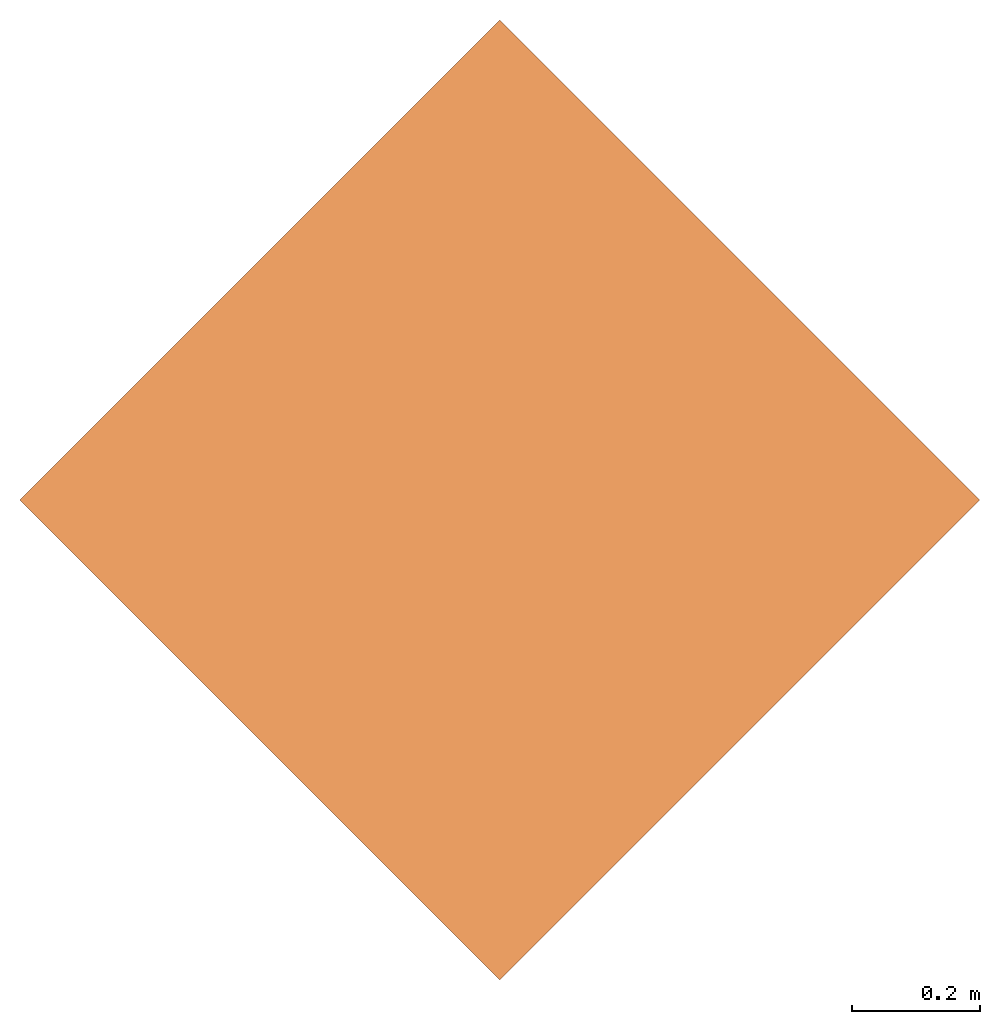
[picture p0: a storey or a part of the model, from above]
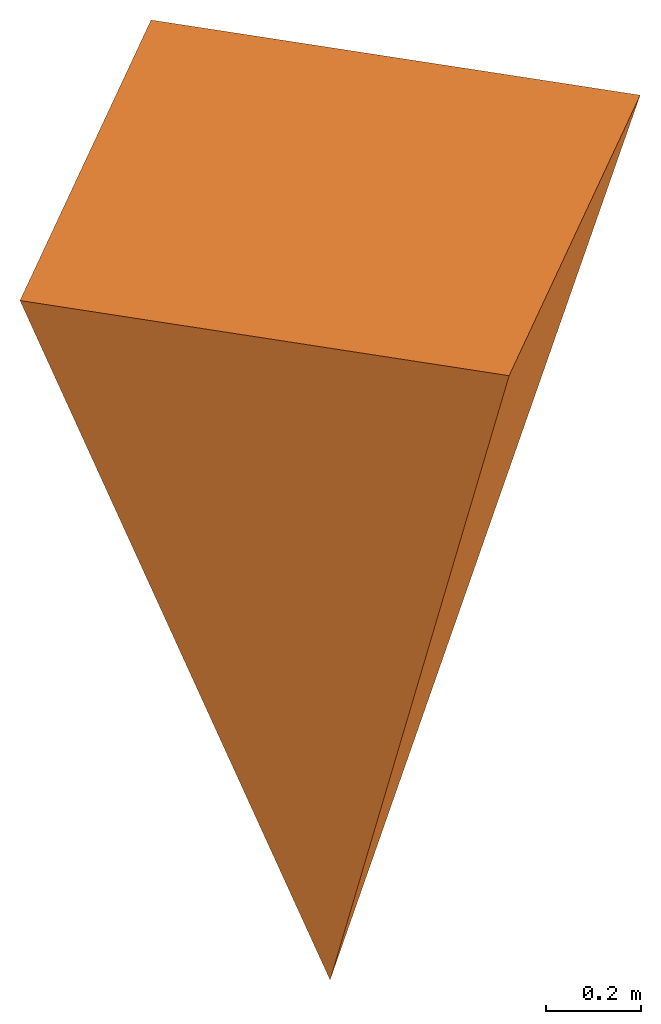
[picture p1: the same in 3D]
Properties of the parts of a building model (IFC4), part 1 of 4

# File
Description: no view
File name: 6-300-WUN-H1-000-000-FMO-V-00#260608.ifc
Time: 2026-06-08T13:36:47
Author: Tschörner Christoph, a|sh
Organization: No Organization
Written by: ODA SDAI 25.4
Authorization: christoph.tschoerner

# IfcProject, 40271-01 Psychiatrie Neubau Wunstorf LPH5
AllplanAttributes - Normalhöhennull: 43.1 m; Projektvorlage: ash_20210624

# IfcSite, Psychiatrie Neubau Wunstorf
RefLatitude: 48, 8, 10, 320000; RefLongitude: 11, 41, 19, 320000; RefElevation: 43.1 m

# IfcBuildingStorey (3)
In: Neubau H1 Sozialzentrum
Name | Elevation (m)
H1 Ebene +1 | 4.45
H1 Ebene 0 | 0.7
H1 Gründung | 0.2

# IfcSpace (38)
AllplanAttributes - Raumumschließung: R; Flächenart_DIN277: N; Flächenart_Wohnfläche: WO; Ortscode_Geschoßbezeichnung: Ebene 0; Raum unter Treppe (Wohnfl erst ab 2m): 0; Faktor_Wohnfläche_Raum: 1; Faktor_DIN277: 1; Bauteil: H2; Raumzone (nach DIN 18599): Ne; Raumprogramm Soll: 0 m2; Abrechnungsart: m²; Objektname: Raum
Name | In | LongName | Status | Nutzungsart_Din277 | ash_lichte Raumhöhe | OKFF | Allright_Bauteil_ID
WUN-H1-E01 | H1 Ebene +1 | Technik hoch | Neubau | TF | 6.455376 | 0 | 1616Rau0000076425 | AllplanAttributes - Raumnr. Bauherr: Technik
WUN-H1-E01 | H1 Ebene +1 | Hausanschluss |  | TF | 7.074000 | 0 | 1616Rau0000076258 | AllplanAttributes - Raumnr. Bauherr: Technik
WUN-H1-E01 | H1 Ebene +1 | AV | Neubau | TF | 7.074000 | 0 | 1616Rau0000076249 | AllplanAttributes - Raumnr. Bauherr: Technik
WUN-H1-E01 | H1 Ebene +1 | SV | Neubau | TF | 7.074000 | 0 | 1616Rau0000076252 | AllplanAttributes - Raumnr. Bauherr: Technik
WUN-H1-E01 | H1 Ebene +1 | EDV | Neubau | TF | 7.074000 | 0 | 1616Rau0000076301 | AllplanAttributes - Raumnr. Bauherr: Technik
WUN-H1-E01 | H1 Ebene +1 | Sicherheitsbeleuchtung | Neubau | TF | 7.074000 | 0 | 1616Rau0000076255 | AllplanAttributes - Raumnr. Bauherr: Technik
WUN-H1-E01 | H1 Ebene +1 | Flur | Neubau | TF | 7.074000 | 0 | 1616Rau0000076314
WUN-H1-E01 | H1 Ebene +1 | Luft | Neubau | TF | 7.224589 | 0 | 1616Rau0000076370 | AllplanAttributes - Raumnr. Bauherr: Technik
WUN-H1-E00 | H1 Ebene 0 | Flur | Neubau | TF | 3.450000 | 0.7 | 1565Rau0000038403
WUN-H1-E00 | H1 Ebene 0 | Flur | Neubau | TF | 4.100000 | 0.7 | 1565Rau0000038449
WUN-H1-E00 | H1 Ebene 0 | Mehrzweckraum | Neubau | TF | 5.221026 | 0.7 | 1566Rau0811551557
WUN-H1-E00 | H1 Ebene 0 | Speiseraum | Neubau | TF | 6.938287 | 0.7 | 1566Rau0811551560
WUN-H1-E00 | H1 Ebene 0 | Ausgabe | Neubau | TF | 5.361132 | 0.7 | 1566Rau0811551551
WUN-H1-E00 | H1 Ebene 0 | Windfang | Neubau | TF | 3.450000 | 0.7 | 1566Rau0811551566
WUN-H1-E00 | H1 Ebene 0 | WC BH | Neubau | TF | 3.477853 | 0.7 | 1566Rau0811551610
WUN-H1-E00 | H1 Ebene 0 | WC Pers. |  | NUF | (4100-36+764+100)/1000- | 0.7 | 1566Rau0811551584
WUN-H1-E00 | H1 Ebene 0 | WC H |  | TF | 3.200000 | 0.7 | 1566Rau0811551572
WUN-H1-E00 | H1 Ebene 0 | WC D |  | TF | 3.200000 | 0.7 | 1566Rau0811551575
WUN-H1-E00 | H1 Ebene 0 | WC BH |  | TF | 3.200000 | 0.7 | 1566Rau0811551599
WUN-H1-E00 | H1 Ebene 0 | Umkleideraum |  | NUF | (4100-36+514+100)/1000- | 0.7 | 1566Rau0811551545
WUN-H1-E00 | H1 Ebene 0 | PuMi. |  | TF | (4100-36+614+100)/1000- | 0.7 | 1566Rau0811551542
WUN-H1-E00 | H1 Ebene 0 | Büro | Neubau | NUF | 3.450000 | 0.7 | 1566Rau0811551524
WUN-H1-E00 | H1 Ebene 0 | Anlieferung | Neubau | NUF | 3.450000 | 0.7 | 1566Rau0811551563
WUN-H1-E00 | H1 Ebene 0 | Lager |  | NUF | (4100-36+514+100)/1000- | 0.7 | 1566Rau0811551536
WUN-H1-E00 | H1 Ebene 0 | Leergutlager | Neubau | NUF | (4100-36+514+100)/1000- | 0.7 | 1566Rau0811551530
WUN-H1-E00 | H1 Ebene 0 | Getränkelager | Neubau | NUF | (4100-36+514+100)/1000- | 0.7 | 1566Rau0811551596
WUN-H1-E00 | H1 Ebene 0 | Konfiskatkühler | Neubau | TF | 3.450000 | 0.7 | 1566Rau0811551539
WUN-H1-E00 | H1 Ebene 0 | Hausanschluss |  | TF | (4100-36+614+100)/1000- | 0.7 | 1566Rau0811551548 | AllplanAttributes - Raumnr. Bauherr: Technik
WUN-H1-E00 | H1 Ebene 0 | Abst. Stühle / Tische | Neubau | TF | 4.005791 | 0.7 | 1566Rau0811551607
WUN-H1-E00 | H1 Ebene 0 | Therapiegerät | Neubau | TF | 4.334275 | 0.7 | 1566Rau0811551601
WUN-H1-E00 | H1 Ebene 0 | Abst. Stühle / Tische |  | TF | (4100-36+764+100)/1000- | 0.7 | 1566Rau0811551554
WUN-H1-E00 | H1 Ebene 0 | Garderobe | Neubau | TF | 3.717910 | 0.7 | 1566Rau0811551604
WUN-H1-E00 | H1 Ebene 0 | Enzo | Neubau | TF | 3.500000 | 0.7 | 1566Rau0811551578
WUN-H1-E00 | H1 Ebene 0 | Küche | Neubau | TF | 3.500000 | 0.7 | 1566Rau0811551527
WUN-H1-E00 | H1 Ebene 0 | Mini Bakery | Neubau | TF | 3.500000 | 0.7 | 1566Rau0811551533
WUN-H1-E00 | H1 Ebene 0 | Spülraum |  | TF | 4.580000 | 0.7 | 1566Rau0811551581 | AllplanAttributes - Raumnr. Bauherr: Technik
WUN-H1-E00 | H1 Ebene 0 | NK | Neubau | NUF | (4100-36+514+100)/1000- | 0.7 | 1566Rau0811551593
WUN-H1-E00 | H1 Ebene 0 | TK | Neubau | NUF | (4100-36+514+100)/1000- | 0.7 | 1566Rau0811551590

# IfcBeam (2)
In: H1 Ebene 0
Material: Holz
AllplanAttributes - 2D Interaktion: yes; Gewerk: Zimmer- und Holzbauarbeiten; Material: Holz; OKFF: 0; Abrechnungsart: m³; Objektname: Unterzug
Pset_BeamCommon - Status: NEW; IsExternal: no; ThermalTransmittance: 0 W/K/m2
Name | Allright_Bauteil_ID
 | 1564Unz0000004217
 | 1564Unz0000004201

# IfcBuildingElementProxy, Nullpunkt
In: Modellreferenzen
AllplanAttributes - UK: 0 m; OK: 0 m; V6: 0 m; V7: 0 m; V8: 0 m; V9: 0; Bezeichnung: Nullpunkt; Allright_Bauteil_ID: 5981Mak0000010864; Abrechnungsart: St; Objektname: Makro

# IfcColumn (14)
PredefinedType: COLUMN
AllplanAttributes - Gewerk: Zimmer- und Holzbauarbeiten; Abrechnungsart: m; Objektname: Stütze
Name | In | Material = AllplanAttributes, Material | 2D Interaktion | Codetext = Reference | OKFF | Allright_Bauteil_ID | Status | LoadBearing = IsExternal | FireRating | ThermalTransmittance (W/K/m2)
 | H1 Ebene +1 | ST-H | yes | Codetext | 5.11 | 1613St 2005708406 | NEW | no | REI 60-A1 - D,s2-d0 /A1 | 0
 | H1 Ebene +1 | ST-H | yes | Codetext | 5.11 | 1613St 2005708246 | NEW | no | REI 60-A1 - D,s2-d0 /A1 | 0
 | H1 Ebene +1 | ST-H | yes | Codetext | 5.11 | 1613St 2005708252 | NEW | no | REI 60-A1 - D,s2-d0 /A1 | 0
 | H1 Ebene +1 | ST-H | yes | Codetext | 5.11 | 1613St 2005708254 | NEW | no | REI 60-A1 - D,s2-d0 /A1 | 0
 | H1 Ebene +1 | ST-Stahl | yes | Codetext | 5.11 | 1613St 2005708322 | NEW | no | REI 60-A1 - D,s2-d0 /A1 | 0
 | H1 Ebene +1 | ST-Stahl | yes | Codetext | 5.11 | 1613St 2005708312 | NEW | no | REI 60-A1 - D,s2-d0 /A1 | 0
 | H1 Ebene +1 | ST-Stahl | yes | Codetext | 5.11 | 1613St 2005708325 | NEW | no | REI 60-A1 - D,s2-d0 /A1 | 0
 | H1 Ebene +1 | ST-H | yes | Codetext | 5.11 | 1613St 2005708331 | NEW | no | REI 60-A1 - D,s2-d0 /A1 | 0
 | H1 Ebene +1 | ST-Stahl | yes | Codetext | 5.11 | 1613St 2005708383 | NEW | no | REI 60-A1 - D,s2-d0 /A1 | 0
 | H1 Ebene 0 | ST-H | yes | Codetext | 5.11 | 1563St 0813612477 | NEW | no | REI 60-A1 - D,s2-d0 /A1 | 0
 | H1 Ebene 0 | ST-ST |  |  |  | 1563St 0813612442
 | H1 Ebene 0 | ST-ST |  |  |  | 1563St 0813612436
 | H1 Ebene 0 | ST-ST |  |  |  | 1563St 0813612299
 | H1 Ebene 0 | ST-ST |  |  |  | 1563St 0813612460

# IfcCovering (135)
Name | In | PredefinedType | Material | Allright_Bauteil_ID | Abrechnungsart | Schichtnummer | Schichtdicke (m) | Dicke (m) = Bezugshöhe = Deltahöhe | Faktor | Objektname | AllplanAttributes, Material | Status | Gewerk | Bezeichnung | D_lichte Raumhöhe [Zahl] (m)
 | WUN-H1-E01 | FLOORING | FB 0.15 m | 1616Bfl0000076427/01 | m² | 1 | 0.15 | 0 | 1 | Bodenfläche | FB | NEW | AllplanAttributes - Bauteil-ID: 301
Gipsfaserplatten 2-lagig (BSK) | WUN-H1-E01 | CEILING | C/C 0.036 m | 1616Dfl0000076426/01 | m² | 1 | 0.036 | 0 | 1 | Deckenfläche | C/C | NEW | Trockenbauarbeiten | Gipsfaserplatten 2-lagig (BSK) | 3.364 | AllplanAttributes - RoomName: SV
Gipsfaserplatten 2-lagig (BSK) | WUN-H1-E01 | CEILING | D4 0.001 m | 1616Dfl0000076426/02 | m² | 2 | 0.001 | 0 | 1 | Deckenfläche | D4 | NEW | Maler- und Lackierarbeiten
PVC | WUN-H1-E01 | FLOORING | Ku3 0.15 m | 1616Bfl0000076357/01 | m² | 1 | 0.15 | 0 | 1 | Bodenfläche | Ku3 | NEW | Bodenbelagsarbeiten | PVC | AllplanAttributes - Bauteil-ID: 301; Raumnr. Bauherr: 2.11_A2_02; ash B_Aufbau: B1; ash B_Rutschhemmung: R9
Gipsfaserplatten 2-lagig (BSK) | WUN-H1-E01 | CEILING | C/C 0.036 m | 1616Dfl0000076418/01 | m² | 1 | 0.036 | 0 | 1 | Deckenfläche | C/C | NEW | Trockenbauarbeiten | Gipsfaserplatten 2-lagig (BSK) | 3.364 | AllplanAttributes - RoomName: SV
Gipsfaserplatten 2-lagig (BSK) | WUN-H1-E01 | CEILING | D4 0.001 m | 1616Dfl0000076418/02 | m² | 2 | 0.001 | 0 | 1 | Deckenfläche | D4 | NEW | Maler- und Lackierarbeiten
PVC | WUN-H1-E01 | FLOORING | Ku3 0.15 m | 1616Bfl0000076354/01 | m² | 1 | 0.15 | 0 | 1 | Bodenfläche | Ku3 | NEW | Bodenbelagsarbeiten | PVC | AllplanAttributes - Bauteil-ID: 301; Raumnr. Bauherr: 2.11_A2_02; ash B_Aufbau: B1; ash B_Rutschhemmung: R9
Gipsfaserplatten 2-lagig (BSK) | WUN-H1-E01 | CEILING | C/C 0.036 m | 1616Dfl0000076419/01 | m² | 1 | 0.036 | 0 | 1 | Deckenfläche | C/C | NEW | Trockenbauarbeiten | Gipsfaserplatten 2-lagig (BSK) | 3.364 | AllplanAttributes - RoomName: SV
Gipsfaserplatten 2-lagig (BSK) | WUN-H1-E01 | CEILING | D4 0.001 m | 1616Dfl0000076419/02 | m² | 2 | 0.001 | 0 | 1 | Deckenfläche | D4 | NEW | Maler- und Lackierarbeiten
PVC | WUN-H1-E01 | FLOORING | Ku3 0.15 m | 1616Bfl0000076355/01 | m² | 1 | 0.15 | 0 | 1 | Bodenfläche | Ku3 | NEW | Bodenbelagsarbeiten | PVC | AllplanAttributes - Bauteil-ID: 301; Raumnr. Bauherr: 2.11_A2_02; ash B_Aufbau: B1; ash B_Rutschhemmung: R9
Gipsfaserplatten 2-lagig (BSK) | WUN-H1-E01 | CEILING | C/C 0.036 m | 1616Dfl0000076420/01 | m² | 1 | 0.036 | 0 | 1 | Deckenfläche | C/C | NEW | Trockenbauarbeiten | Gipsfaserplatten 2-lagig (BSK) | 3.364 | AllplanAttributes - RoomName: SV
Gipsfaserplatten 2-lagig (BSK) | WUN-H1-E01 | CEILING | D4 0.001 m | 1616Dfl0000076420/02 | m² | 2 | 0.001 | 0 | 1 | Deckenfläche | D4 | NEW | Maler- und Lackierarbeiten
PVC | WUN-H1-E01 | FLOORING | Ku3 0.15 m | 1616Bfl0000076358/01 | m² | 1 | 0.15 | 0 | 1 | Bodenfläche | Ku3 | NEW | Bodenbelagsarbeiten | PVC | AllplanAttributes - Bauteil-ID: 301; Raumnr. Bauherr: 2.11_A2_02; ash B_Aufbau: B1; ash B_Rutschhemmung: R9
Gipsfaserplatten 2-lagig (BSK) | WUN-H1-E01 | CEILING | C/C 0.036 m | 1616Dfl0000076421/01 | m² | 1 | 0.036 | 0 | 1 | Deckenfläche | C/C | NEW | Trockenbauarbeiten | Gipsfaserplatten 2-lagig (BSK) | 3.364 | AllplanAttributes - RoomName: SV
Gipsfaserplatten 2-lagig (BSK) | WUN-H1-E01 | CEILING | D4 0.001 m | 1616Dfl0000076421/02 | m² | 2 | 0.001 | 0 | 1 | Deckenfläche | D4 | NEW | Maler- und Lackierarbeiten
PVC | WUN-H1-E01 | FLOORING | Ku3 0.15 m | 1616Bfl0000076356/01 | m² | 1 | 0.15 | 0 | 1 | Bodenfläche | Ku3 | NEW | Bodenbelagsarbeiten | PVC | AllplanAttributes - Bauteil-ID: 301; Raumnr. Bauherr: 2.11_A2_02; ash B_Aufbau: B1; ash B_Rutschhemmung: R9
Gipsfaserplatten 2-lagig (BSK) | WUN-H1-E01 | CEILING | C/C 0.036 m | 1616Dfl0000076422/01 | m² | 1 | 0.036 | 0 | 1 | Deckenfläche | C/C | NEW | Trockenbauarbeiten | Gipsfaserplatten 2-lagig (BSK) | 3.364 | AllplanAttributes - RoomName: SV
Gipsfaserplatten 2-lagig (BSK) | WUN-H1-E01 | CEILING | D4 0.001 m | 1616Dfl0000076422/02 | m² | 2 | 0.001 | 0 | 1 | Deckenfläche | D4 | NEW | Maler- und Lackierarbeiten
PVC | WUN-H1-E01 | FLOORING | Ku3 0.15 m | 1616Bfl0000076359/01 | m² | 1 | 0.15 | 0 | 1 | Bodenfläche | Ku3 | NEW | Bodenbelagsarbeiten | PVC | AllplanAttributes - Bauteil-ID: 301; Raumnr. Bauherr: 2.11_A2_02; ash B_Aufbau: B1; ash B_Rutschhemmung: R9
Gipsfaserplatten 2-lagig (BSK) | WUN-H1-E01 | CEILING | C/C 0.036 m | 1616Dfl0000076424/01 | m² | 1 | 0.036 | 0 | 1 | Deckenfläche | C/C | NEW | Trockenbauarbeiten | Gipsfaserplatten 2-lagig (BSK) | 3.364 | AllplanAttributes - RoomName: SV
Gipsfaserplatten 2-lagig (BSK) | WUN-H1-E01 | CEILING | D4 0.001 m | 1616Dfl0000076424/02 | m² | 2 | 0.001 | 0 | 1 | Deckenfläche | D4 | NEW | Maler- und Lackierarbeiten
PVC | WUN-H1-E01 | FLOORING | Ku3 0.15 m | 1616Bfl0000076371/01 | m² | 1 | 0.15 | 0 | 1 | Bodenfläche | Ku3 | NEW | Bodenbelagsarbeiten | PVC | AllplanAttributes - Bauteil-ID: 301; Raumnr. Bauherr: 2.11_A2_02; ash B_Aufbau: B1; ash B_Rutschhemmung: R9
Gipsfaserplatten 2-lagig (BSK) | WUN-H1-E01 | CEILING | C/C 0.036 m | 1616Dfl0000076423/01 | m² | 1 | 0.036 | 0 | 1 | Deckenfläche | C/C | NEW | Trockenbauarbeiten | Gipsfaserplatten 2-lagig (BSK) | 3.364 | AllplanAttributes - RoomName: SV
Gipsfaserplatten 2-lagig (BSK) | WUN-H1-E01 | CEILING | D4 0.001 m | 1616Dfl0000076423/02 | m² | 2 | 0.001 | 0 | 1 | Deckenfläche | D4 | NEW | Maler- und Lackierarbeiten
Gipsfaserplatten 2-lagig (BSK) | H1 Ebene 0 | CEILING | layer 0.036 m | 1565Dfl0000038394/01 | m² | 1 | 0.036 | 0 | 1 | Deckenfläche |  | NEW | Trockenbauarbeiten | Gipsfaserplatten 2-lagig (BSK) | 2.5
Gipsfaserplatten 2-lagig (BSK) | H1 Ebene 0 | CEILING | Installationshöhe 0.994 m | 1565Dfl0000038394/02 | m² | 2 | 0.994 | 0 | 1 | Bekleidung | Installationshöhe | NEW | Trockenbauarbeiten |  | 2.5 | AllplanAttributes - ash_lichte Raumhöhe: 2.750000; OKFF: 0; Pset_CoveringCommon - FireRating: für korrekte FläVisu
Gipsfaserplatten 2-lagig (BSK) | H1 Ebene 0 | CEILING | A1 0.1 m | 1565Dfl0000038394/03 | m² | 3 | 0.1 | 0 | 1 | Bekleidung | A1 | NEW | Trockenbauarbeiten |  | 2.5 | AllplanAttributes - ash_lichte Raumhöhe: 2.750000; OKFF: 0; Pset_CoveringCommon - FireRating: -; AcousticRating: -
Gipsfaserplatten 2-lagig (BSK) | H1 Ebene 0 | CEILING | D1 0.001 m | 1565Dfl0000038394/04 | m² | 4 | 0.001 | 0 | 1 | Bekleidung | D1 | NEW | Maler- und Lackierarbeiten |  | 2.5 | AllplanAttributes - ash_lichte Raumhöhe: 2.750000; OKFF: 0
Fliesen Großformat | WUN-H1-E00 | FLOORING | Fl12 0.2 m | 1565Bfl0000038399/01 | m² | 1 | 0.2 | 0 | 1 | Bodenfläche | Fl12 | NEW | Bodenbelagsarbeiten | Fliesen Großformat | AllplanAttributes - Bauteil-ID: 301; Raumnr. Bauherr: 2.11_A2_02; ash B_Aufbau: B4; ash B_Rutschhemmung: R10
Gipsfaserplatten 2-lagig (BSK) | WUN-H1-E00 | CEILING | layer 0.036 m | 1565Dfl0000038401/01 | m² | 1 | 0.036 | 0 | 1 | Deckenfläche |  | NEW | Trockenbauarbeiten | Gipsfaserplatten 2-lagig (BSK) | 2.5
 | WUN-H1-E00 | CEILING | Installationshöhe 0.514 m | 1565Dfl0000038401/02 | m² | 2 | 0.514 | 0 | 1 | Bekleidung | Installationshöhe | NEW | Trockenbauarbeiten |  | 2.5 | AllplanAttributes - ash_lichte Raumhöhe: 2.750000; Pset_CoveringCommon - FireRating: für korrekte FläVisu
 | WUN-H1-E00 | CEILING | A1 0.1 m | 1565Dfl0000038401/03 | m² | 3 | 0.1 | 0 | 1 | Bekleidung | A1 | NEW | Trockenbauarbeiten |  | 2.5 | AllplanAttributes - ash_lichte Raumhöhe: 2.750000; Pset_CoveringCommon - AcousticRating: -
 | WUN-H1-E00 | CEILING | D1 0.001 m | 1565Dfl0000038401/04 | m² | 4 | 0.001 | 0 | 1 | Bekleidung | D1 | NEW | Maler- und Lackierarbeiten |  | 2.5 | AllplanAttributes - ash_lichte Raumhöhe: 2.750000
Gipsfaserplatten 2-lagig (BSK) | WUN-H1-E00 | CEILING | layer 0.036 m | 1565Dfl0000038357/01 | m² | 1 | 0.036 | 0 | 1 | Deckenfläche |  | NEW | Trockenbauarbeiten | Gipsfaserplatten 2-lagig (BSK) | 2.5
Gipsfaserplatten 2-lagig (BSK) | WUN-H1-E00 | CEILING | Installationshöhe 0.514 m | 1565Dfl0000038357/02 | m² | 2 | 0.514 | 0 | 1 | Bekleidung | Installationshöhe | NEW | Trockenbauarbeiten |  | 2.5 | AllplanAttributes - ash_lichte Raumhöhe: 2.750000; OKFF: 0; Pset_CoveringCommon - FireRating: für korrekte FläVisu
Gipsfaserplatten 2-lagig (BSK) | WUN-H1-E00 | CEILING | A1 0.1 m | 1565Dfl0000038357/03 | m² | 3 | 0.1 | 0 | 1 | Bekleidung | A1 | NEW | Trockenbauarbeiten |  | 2.5 | AllplanAttributes - ash_lichte Raumhöhe: 2.750000; OKFF: 0; Pset_CoveringCommon - FireRating: -; AcousticRating: -
Gipsfaserplatten 2-lagig (BSK) | WUN-H1-E00 | CEILING | D1 0.001 m | 1565Dfl0000038357/04 | m² | 4 | 0.001 | 0 | 1 | Bekleidung | D1 | NEW | Maler- und Lackierarbeiten |  | 2.5 | AllplanAttributes - ash_lichte Raumhöhe: 2.750000; OKFF: 0
PVC Bahnenware Uni | WUN-H1-E00 | FLOORING | Ku2 0.2 m | 1565Bfl0000038447/01 | m² | 1 | 0.2 | 0 | 1 | Bodenfläche | Ku2 | NEW | Bodenbelagsarbeiten | PVC Bahnenware Uni | AllplanAttributes - Bauteil-ID: 301; Raumnr. Bauherr: 2.11_A2_02; ash B_Aufbau: B1; ash B_Rutschhemmung: R9
Fliesen Großformat | WUN-H1-E00 | FLOORING | Fl12 0.2 m | 1566Bfl0811551861/01 | m² | 1 | 0.2 | 0 | 1 | Bodenfläche | Fl12 | NEW | Bodenbelagsarbeiten | Fliesen Großformat | AllplanAttributes - Bauteil-ID: 301; Raumnr. Bauherr: 2.11_A2_02; ash B_Aufbau: B4; ash B_Rutschhemmung: R10
Fliesen Großformat | WUN-H1-E00 | FLOORING | Fl12 0.2 m | 1566Bfl0811551866/01 | m² | 1 | 0.2 | 0 | 1 | Bodenfläche | Fl12 | NEW | Bodenbelagsarbeiten | Fliesen Großformat | AllplanAttributes - Bauteil-ID: 301; Raumnr. Bauherr: 2.11_A2_02; ash B_Aufbau: B4; ash B_Rutschhemmung: R10
Fliesen Großformat | WUN-H1-E00 | FLOORING | Fl12 0.2 m | 1566Bfl0811551889/01 | m² | 1 | 0.2 | 0 | 1 | Bodenfläche | Fl12 | NEW | Bodenbelagsarbeiten | Fliesen Großformat | AllplanAttributes - Bauteil-ID: 301; Raumnr. Bauherr: 2.11_A2_02; ash B_Aufbau: B4; ash B_Rutschhemmung: R10
Fliesen Großformat | WUN-H1-E00 | FLOORING | Fl12 0.2 m | 1566Bfl0811551860/01 | m² | 1 | 0.2 | 0 | 1 | Bodenfläche | Fl12 | NEW | Bodenbelagsarbeiten | Fliesen Großformat | AllplanAttributes - Bauteil-ID: 301; Raumnr. Bauherr: 2.11_A2_02; ash B_Aufbau: B4; ash B_Rutschhemmung: R10
Fliesen | WUN-H1-E00 | FLOORING | Fl1 0.2 m | 1566Bfl0811551862/01 | m² | 1 | 0.2 | 0 | 1 | Bodenfläche | Fl1 | NEW | Bodenbelagsarbeiten | Fliesen | AllplanAttributes - Bauteil-ID: 301; Raumnr. Bauherr: 2.11_A2_02; ash B_Aufbau: B2; ash B_Rutschhemmung: R10
Fliesen | WUN-H1-E00 | FLOORING | Fl1 0.2 m | 1566Bfl0811551872/01 | m² | 1 | 0.2 | 0 | 1 | Bodenfläche | Fl1 | NEW | Bodenbelagsarbeiten | Fliesen | AllplanAttributes - Bauteil-ID: 301; Raumnr. Bauherr: 2.11_A2_02; ash B_Aufbau: B2; ash B_Rutschhemmung: R10
Gipsfaserplatten 2-lagig (BSK) | WUN-H1-E00 | CEILING | layer 0.036 m | 1566Dfl0811551925/01 | m² | 1 | 0.036 | 0 | 1 | Bekleidung |  | NEW | Trockenbauarbeiten | Gipsfaserplatten 2-lagig (BSK) | 2.5 | AllplanAttributes - ash_lichte Raumhöhe: 2.5; Attributset-Objekt: Covering; Pset_CoveringCommon - FireRating: für korrekte FläVisu
Gipsfaserplatten 2-lagig (BSK) | WUN-H1-E00 | CEILING | Installationshöhe 0.764 m | 1566Dfl0811551925/02 | m² | 2 | 0.764 | 0 | 1 | Bekleidung | Installationshöhe | NEW | Trockenbauarbeiten |  | 2.5 | AllplanAttributes - ash_lichte Raumhöhe: (4100-36+764+100)/1000-0.7; Attributset-Objekt: Covering; Pset_CoveringCommon - FireRating: für korrekte FläVisu; Reference: Reference
Rasterdecke | WUN-H1-E00 | CEILING | E3 0.1 m | 1566Dfl0811551925/03 | m² | 3 | 0.1 | 0 | 1 | Bekleidung | E3 | NEW | Trockenbauarbeiten | Rasterdecke | 2.5 | AllplanAttributes - ash_lichte Raumhöhe: (4100-36+764+100)/1000-0.7; Attributset-Objekt: Covering; Pset_CoveringCommon - FireRating: -; AcousticRating: -
Fliesen | WUN-H1-E00 | FLOORING | Fl1 0.2 m | 1566Bfl0811551874/01 | m² | 1 | 0.2 | 0 | 1 | Bodenfläche | Fl1 |  | Bodenbelagsarbeiten | Fliesen | AllplanAttributes - Bauteil-ID: 301; Raumnr. Bauherr: 2.11_A2_02; ash B_Aufbau: B2; ash B_Rutschhemmung: R10
Gipsfaserplatten 2-lagig (BSK) | WUN-H1-E00 | CEILING | layer 0.036 m | 1566Dfl0811551927/01 | m² | 1 | 0.036 | 0 | 1 | Deckenfläche |  |  | Trockenbauarbeiten | Gipsfaserplatten 2-lagig (BSK) | 2.5
Gipsfaserplatten 2-lagig (BSK) | WUN-H1-E00 | CEILING | Installationshöhe 0.764 m | 1566Dfl0811551927/02 | m² | 2 | 0.764 | 0 | 1 | Bekleidung | Installationshöhe |  | Trockenbauarbeiten |  | 2.5 | AllplanAttributes - ash_lichte Raumhöhe: 2.500000; OKFF: 0; Pset_CoveringCommon - FireRating: für korrekte FläVisu
Gipskarton, imprägniert | WUN-H1-E00 | CEILING | B 0.1 m | 1566Dfl0811551927/03 | m² | 3 | 0.1 | 0 | 1 | Bekleidung | B |  | Trockenbauarbeiten | Gipskarton, imprägniert | 2.5 | AllplanAttributes - ash_lichte Raumhöhe: 2.500000; OKFF: 0; Pset_CoveringCommon - FireRating: -; AcousticRating: -
Gipsfaserplatten 2-lagig (BSK) | WUN-H1-E00 | CEILING | D1 0.001 m | 1566Dfl0811551927/04 | m² | 4 | 0.001 | 0 | 1 | Bekleidung | D1 |  | Maler- und Lackierarbeiten |  | 2.5 | AllplanAttributes - ash_lichte Raumhöhe: 2.500000; OKFF: 0
Fliesen | WUN-H1-E00 | FLOORING | Fl1 0.2 m | 1566Bfl0811551873/01 | m² | 1 | 0.2 | 0 | 1 | Bodenfläche | Fl1 |  | Bodenbelagsarbeiten | Fliesen | AllplanAttributes - Bauteil-ID: 301; Raumnr. Bauherr: 2.11_A2_02; ash B_Aufbau: B2; ash B_Rutschhemmung: R10
Gipsfaserplatten 2-lagig (BSK) | WUN-H1-E00 | CEILING | layer 0.036 m | 1566Dfl0811551926/01 | m² | 1 | 0.036 | 0 | 1 | Deckenfläche |  |  | Trockenbauarbeiten | Gipsfaserplatten 2-lagig (BSK) | 2.5
Gipsfaserplatten 2-lagig (BSK) | WUN-H1-E00 | CEILING | Installationshöhe 0.764 m | 1566Dfl0811551926/02 | m² | 2 | 0.764 | 0 | 1 | Bekleidung | Installationshöhe |  | Trockenbauarbeiten |  | 2.5 | AllplanAttributes - ash_lichte Raumhöhe: 2.500000; OKFF: 0; Pset_CoveringCommon - FireRating: für korrekte FläVisu
Gipskarton, imprägniert | WUN-H1-E00 | CEILING | B 0.1 m | 1566Dfl0811551926/03 | m² | 3 | 0.1 | 0 | 1 | Bekleidung | B |  | Trockenbauarbeiten | Gipskarton, imprägniert | 2.5 | AllplanAttributes - ash_lichte Raumhöhe: 2.500000; OKFF: 0; Pset_CoveringCommon - FireRating: -; AcousticRating: -
Gipsfaserplatten 2-lagig (BSK) | WUN-H1-E00 | CEILING | D1 0.001 m | 1566Dfl0811551926/04 | m² | 4 | 0.001 | 0 | 1 | Bekleidung | D1 |  | Maler- und Lackierarbeiten |  | 2.5 | AllplanAttributes - ash_lichte Raumhöhe: 2.500000; OKFF: 0
Fliesen | WUN-H1-E00 | FLOORING | Fl1 0.2 m | 1566Bfl0811551867/01 | m² | 1 | 0.2 | 0 | 1 | Bodenfläche | Fl1 |  | Bodenbelagsarbeiten | Fliesen | AllplanAttributes - Bauteil-ID: 301; Raumnr. Bauherr: 2.11_A2_02; ash B_Aufbau: B2; ash B_Rutschhemmung: R10
Gipsfaserplatten 2-lagig (BSK) | WUN-H1-E00 | CEILING | layer 0.036 m | 1566Dfl0811551920/01 | m² | 1 | 0.036 | 0 | 1 | Deckenfläche |  |  | Trockenbauarbeiten | Gipsfaserplatten 2-lagig (BSK) | 2.5
Gipsfaserplatten 2-lagig (BSK) | WUN-H1-E00 | CEILING | Installationshöhe 0.764 m | 1566Dfl0811551920/02 | m² | 2 | 0.764 | 0 | 1 | Bekleidung | Installationshöhe |  | Trockenbauarbeiten |  | 2.5 | AllplanAttributes - ash_lichte Raumhöhe: 2.500000; OKFF: 0; Pset_CoveringCommon - FireRating: für korrekte FläVisu
Gipskarton, imprägniert | WUN-H1-E00 | CEILING | B 0.1 m | 1566Dfl0811551920/03 | m² | 3 | 0.1 | 0 | 1 | Bekleidung | B |  | Trockenbauarbeiten | Gipskarton, imprägniert | 2.5 | AllplanAttributes - ash_lichte Raumhöhe: 2.500000; OKFF: 0; Pset_CoveringCommon - FireRating: -; AcousticRating: -
Gipsfaserplatten 2-lagig (BSK) | WUN-H1-E00 | CEILING | D1 0.001 m | 1566Dfl0811551920/04 | m² | 4 | 0.001 | 0 | 1 | Bekleidung | D1 |  | Maler- und Lackierarbeiten |  | 2.5 | AllplanAttributes - ash_lichte Raumhöhe: 2.500000; OKFF: 0
PVC Bahnenware Uni | WUN-H1-E00 | FLOORING | Ku2 0.2 m | 1566Bfl0811551879/01 | m² | 1 | 0.2 | 0 | 1 | Bodenfläche | Ku2 | NEW | Bodenbelagsarbeiten | PVC Bahnenware Uni | AllplanAttributes - Bauteil-ID: 301; Raumnr. Bauherr: 2.11_A2_02; ash B_Aufbau: B1; ash B_Rutschhemmung: R9
Gipsfaserplatten 2-lagig (BSK) | WUN-H1-E00 | CEILING | layer 0.036 m | 1566Dfl0811551931/01 | m² | 1 | 0.036 | 0 | 1 | Bekleidung |  | NEW | Trockenbauarbeiten | Gipsfaserplatten 2-lagig (BSK) | 2.5 | AllplanAttributes - ash_lichte Raumhöhe: 2.75; Attributset-Objekt: Covering; Pset_CoveringCommon - FireRating: für korrekte FläVisu
Gipsfaserplatten 2-lagig (BSK) | WUN-H1-E00 | CEILING | Installationshöhe 0.514 m | 1566Dfl0811551931/02 | m² | 2 | 0.514 | 0 | 1 | Bekleidung | Installationshöhe | NEW | Trockenbauarbeiten |  | 2.5 | AllplanAttributes - ash_lichte Raumhöhe: (4100-36+514+100)/1000-0.7; Attributset-Objekt: Covering; Pset_CoveringCommon - FireRating: für korrekte FläVisu; Reference: Reference
Rasterdecke | WUN-H1-E00 | CEILING | E3 0.1 m | 1566Dfl0811551931/03 | m² | 3 | 0.1 | 0 | 1 | Bekleidung | E3 | NEW | Trockenbauarbeiten | Rasterdecke | 2.5 | AllplanAttributes - ash_lichte Raumhöhe: (4100-36+514+100)/1000-0.7; Attributset-Objekt: Covering; Pset_CoveringCommon - FireRating: -; AcousticRating: -
PVC Bahnenware Uni | WUN-H1-E00 | FLOORING | Ku2 0.2 m | 1566Bfl0811551880/01 | m² | 1 | 0.2 | 0 | 1 | Bodenfläche | Ku2 | NEW | Bodenbelagsarbeiten | PVC Bahnenware Uni | AllplanAttributes - Bauteil-ID: 301; Raumnr. Bauherr: 2.11_A2_02; ash B_Aufbau: B1; ash B_Rutschhemmung: R9
Gipsfaserplatten 2-lagig (BSK) | WUN-H1-E00 | CEILING | layer 0.036 m | 1566Dfl0811551932/01 | m² | 1 | 0.036 | 0 | 1 | Bekleidung |  | NEW | Trockenbauarbeiten | Gipsfaserplatten 2-lagig (BSK) | 2.5 | AllplanAttributes - ash_lichte Raumhöhe: 2.65; Attributset-Objekt: Covering; Pset_CoveringCommon - FireRating: für korrekte FläVisu
Gipsfaserplatten 2-lagig (BSK) | WUN-H1-E00 | CEILING | Installationshöhe 0.614 m | 1566Dfl0811551932/02 | m² | 2 | 0.614 | 0 | 1 | Bekleidung | Installationshöhe | NEW | Trockenbauarbeiten |  | 2.5 | AllplanAttributes - ash_lichte Raumhöhe: (4100-36+614+100)/1000-0.7; Attributset-Objekt: Covering; Pset_CoveringCommon - FireRating: für korrekte FläVisu; Reference: Reference
Rasterdecke | WUN-H1-E00 | CEILING | E3 0.1 m | 1566Dfl0811551932/03 | m² | 3 | 0.1 | 0 | 1 | Bekleidung | E3 | NEW | Trockenbauarbeiten | Rasterdecke | 2.5 | AllplanAttributes - ash_lichte Raumhöhe: (4100-36+614+100)/1000-0.7; Attributset-Objekt: Covering; Pset_CoveringCommon - FireRating: -; AcousticRating: -
PVC Bahnenware Uni | WUN-H1-E00 | FLOORING | Ku2 0.2 m | 1566Bfl0811551884/01 | m² | 1 | 0.2 | 0 | 1 | Bodenfläche | Ku2 | NEW | Bodenbelagsarbeiten | PVC Bahnenware Uni | AllplanAttributes - Bauteil-ID: 301; Raumnr. Bauherr: 2.11_A2_02; ash B_Aufbau: B1; ash B_Rutschhemmung: R9
Gipsfaserplatten 2-lagig (BSK) | WUN-H1-E00 | CEILING | layer 0.036 m | 1566Dfl0811551936/01 | m² | 1 | 0.036 | 0 | 1 | Deckenfläche |  | NEW | Trockenbauarbeiten | Gipsfaserplatten 2-lagig (BSK) | 2.5
Gipsfaserplatten 2-lagig (BSK) | WUN-H1-E00 | CEILING | Installationshöhe 0.514 m | 1566Dfl0811551936/02 | m² | 2 | 0.514 | 0 | 1 | Bekleidung | Installationshöhe | NEW | Trockenbauarbeiten |  | 2.5 | AllplanAttributes - ash_lichte Raumhöhe: 2.750000; OKFF: 0; Pset_CoveringCommon - FireRating: für korrekte FläVisu
Gipsfaserplatten 2-lagig (BSK) | WUN-H1-E00 | CEILING | A1 0.1 m | 1566Dfl0811551936/03 | m² | 3 | 0.1 | 0 | 1 | Bekleidung | A1 | NEW | Trockenbauarbeiten |  | 2.5 | AllplanAttributes - ash_lichte Raumhöhe: 2.750000; OKFF: 0; Pset_CoveringCommon - FireRating: -; AcousticRating: -
Gipsfaserplatten 2-lagig (BSK) | WUN-H1-E00 | CEILING | D1 0.001 m | 1566Dfl0811551936/04 | m² | 4 | 0.001 | 0 | 1 | Bekleidung | D1 | NEW | Maler- und Lackierarbeiten |  | 2.5 | AllplanAttributes - ash_lichte Raumhöhe: 2.750000; OKFF: 0
PVC Bahnenware Uni | WUN-H1-E00 | FLOORING | Ku2 0.2 m | 1566Bfl0811551876/01 | m² | 1 | 0.2 | 0 | 1 | Bodenfläche | Ku2 | NEW | Bodenbelagsarbeiten | PVC Bahnenware Uni | AllplanAttributes - Bauteil-ID: 301; Raumnr. Bauherr: 2.11_A2_02; ash B_Aufbau: B1; ash B_Rutschhemmung: R9
Gipsfaserplatten 2-lagig (BSK) | WUN-H1-E00 | CEILING | layer 0.036 m | 1566Dfl0811551928/01 | m² | 1 | 0.036 | 0 | 1 | Deckenfläche |  | NEW | Trockenbauarbeiten | Gipsfaserplatten 2-lagig (BSK) | 2.5
Gipsfaserplatten 2-lagig (BSK) | WUN-H1-E00 | CEILING | Installationshöhe 0.514 m | 1566Dfl0811551928/02 | m² | 2 | 0.514 | 0 | 1 | Bekleidung | Installationshöhe | NEW | Trockenbauarbeiten |  | 2.5 | AllplanAttributes - ash_lichte Raumhöhe: 2.750000; OKFF: 0; Pset_CoveringCommon - FireRating: für korrekte FläVisu
Gipsfaserplatten 2-lagig (BSK) | WUN-H1-E00 | CEILING | A1 0.1 m | 1566Dfl0811551928/03 | m² | 3 | 0.1 | 0 | 1 | Bekleidung | A1 | NEW | Trockenbauarbeiten |  | 2.5 | AllplanAttributes - ash_lichte Raumhöhe: 2.750000; OKFF: 0; Pset_CoveringCommon - FireRating: -; AcousticRating: -
Gipsfaserplatten 2-lagig (BSK) | WUN-H1-E00 | CEILING | D1 0.001 m | 1566Dfl0811551928/04 | m² | 4 | 0.001 | 0 | 1 | Bekleidung | D1 | NEW | Maler- und Lackierarbeiten |  | 2.5 | AllplanAttributes - ash_lichte Raumhöhe: 2.750000; OKFF: 0
PVC Bahnenware Uni | WUN-H1-E00 | FLOORING | Ku2 0.2 m | 1566Bfl0811551882/01 | m² | 1 | 0.2 | 0 | 1 | Bodenfläche | Ku2 | NEW | Bodenbelagsarbeiten | PVC Bahnenware Uni | AllplanAttributes - Bauteil-ID: 301; Raumnr. Bauherr: 2.11_A2_02; ash B_Aufbau: B1; ash B_Rutschhemmung: R9
Gipsfaserplatten 2-lagig (BSK) | WUN-H1-E00 | CEILING | layer 0.036 m | 1566Dfl0811551934/01 | m² | 1 | 0.036 | 0 | 1 | Bekleidung |  | NEW | Trockenbauarbeiten | Gipsfaserplatten 2-lagig (BSK) | 2.5 | AllplanAttributes - ash_lichte Raumhöhe: 2.75; Attributset-Objekt: Covering; Pset_CoveringCommon - FireRating: für korrekte FläVisu
Gipsfaserplatten 2-lagig (BSK) | WUN-H1-E00 | CEILING | Installationshöhe 0.514 m | 1566Dfl0811551934/02 | m² | 2 | 0.514 | 0 | 1 | Bekleidung | Installationshöhe | NEW | Trockenbauarbeiten |  | 2.5 | AllplanAttributes - ash_lichte Raumhöhe: (4100-36+514+100)/1000-0.7; Attributset-Objekt: Covering; Pset_CoveringCommon - FireRating: für korrekte FläVisu; Reference: Reference
Rasterdecke | WUN-H1-E00 | CEILING | E3 0.1 m | 1566Dfl0811551934/03 | m² | 3 | 0.1 | 0 | 1 | Bekleidung | E3 | NEW | Trockenbauarbeiten | Rasterdecke | 2.5 | AllplanAttributes - ash_lichte Raumhöhe: (4100-36+514+100)/1000-0.7; Attributset-Objekt: Covering; Pset_CoveringCommon - FireRating: -; AcousticRating: -
PVC Bahnenware Uni | WUN-H1-E00 | FLOORING | Ku2 0.2 m | 1566Bfl0811551883/01 | m² | 1 | 0.2 | 0 | 1 | Bodenfläche | Ku2 | NEW | Bodenbelagsarbeiten | PVC Bahnenware Uni | AllplanAttributes - Bauteil-ID: 301; Raumnr. Bauherr: 2.11_A2_02; ash B_Aufbau: B1; ash B_Rutschhemmung: R9
Gipsfaserplatten 2-lagig (BSK) | WUN-H1-E00 | CEILING | layer 0.036 m | 1566Dfl0811551935/01 | m² | 1 | 0.036 | 0 | 1 | Bekleidung |  | NEW | Trockenbauarbeiten | Gipsfaserplatten 2-lagig (BSK) | 2.5 | AllplanAttributes - ash_lichte Raumhöhe: 2.75; Attributset-Objekt: Covering; Pset_CoveringCommon - FireRating: für korrekte FläVisu
Gipsfaserplatten 2-lagig (BSK) | WUN-H1-E00 | CEILING | Installationshöhe 0.514 m | 1566Dfl0811551935/02 | m² | 2 | 0.514 | 0 | 1 | Bekleidung | Installationshöhe | NEW | Trockenbauarbeiten |  | 2.5 | AllplanAttributes - ash_lichte Raumhöhe: (4100-36+514+100)/1000-0.7; Attributset-Objekt: Covering; Pset_CoveringCommon - FireRating: für korrekte FläVisu; Reference: Reference
Rasterdecke | WUN-H1-E00 | CEILING | E3 0.1 m | 1566Dfl0811551935/03 | m² | 3 | 0.1 | 0 | 1 | Bekleidung | E3 | NEW | Trockenbauarbeiten | Rasterdecke | 2.5 | AllplanAttributes - ash_lichte Raumhöhe: (4100-36+514+100)/1000-0.7; Attributset-Objekt: Covering; Pset_CoveringCommon - FireRating: -; AcousticRating: -
PVC Bahnenware Uni | WUN-H1-E00 | FLOORING | Ku2 0.2 m | 1566Bfl0811551868/01 | m² | 1 | 0.2 | 0 | 1 | Bodenfläche | Ku2 | NEW | Bodenbelagsarbeiten | PVC Bahnenware Uni | AllplanAttributes - Bauteil-ID: 301; Raumnr. Bauherr: 2.11_A2_02; ash B_Aufbau: B1; ash B_Rutschhemmung: R9
Gipsfaserplatten 2-lagig (BSK) | WUN-H1-E00 | CEILING | layer 0.036 m | 1566Dfl0811551921/01 | m² | 1 | 0.036 | 0 | 1 | Bekleidung |  | NEW | Trockenbauarbeiten | Gipsfaserplatten 2-lagig (BSK) | 2.5 | AllplanAttributes - ash_lichte Raumhöhe: 2.75; Attributset-Objekt: Covering; Pset_CoveringCommon - FireRating: für korrekte FläVisu
Gipsfaserplatten 2-lagig (BSK) | WUN-H1-E00 | CEILING | Installationshöhe 0.514 m | 1566Dfl0811551921/02 | m² | 2 | 0.514 | 0 | 1 | Bekleidung | Installationshöhe | NEW | Trockenbauarbeiten |  | 2.5 | AllplanAttributes - ash_lichte Raumhöhe: (4100-36+514+100)/1000-0.7; Attributset-Objekt: Covering; Pset_CoveringCommon - FireRating: für korrekte FläVisu; Reference: Reference
Rasterdecke | WUN-H1-E00 | CEILING | E3 0.1 m | 1566Dfl0811551921/03 | m² | 3 | 0.1 | 0 | 1 | Bekleidung | E3 | NEW | Trockenbauarbeiten | Rasterdecke | 2.5 | AllplanAttributes - ash_lichte Raumhöhe: (4100-36+514+100)/1000-0.7; Attributset-Objekt: Covering; Pset_CoveringCommon - FireRating: -; AcousticRating: -
PVC | WUN-H1-E00 | FLOORING | Ku3 0.2 m | 1566Bfl0811551881/01 | m² | 1 | 0.2 | 0 | 1 | Bodenfläche | Ku3 | NEW | Bodenbelagsarbeiten | PVC | AllplanAttributes - Bauteil-ID: 301; Raumnr. Bauherr: 2.11_A2_02; ash B_Aufbau: B1; ash B_Rutschhemmung: R9
a-sh Deckenbelag | WUN-H1-E00 | CEILING | Installationshöhe 0.55 m | 1566Dfl0811551933/01 | m² | 1 | 0.55 | 0 | 1 | Bekleidung | Installationshöhe | NEW | Trockenbauarbeiten | a-sh Deckenbelag | AllplanAttributes - ash_lichte Raumhöhe: 2.75; Attributset-Objekt: Covering; Pset_CoveringCommon - FireRating: für korrekte FläVisu
a-sh Deckenbelag | WUN-H1-E00 | CEILING | A 0.1 m | 1566Dfl0811551933/02 | m² | 2 | 0.1 | 0 | 1 | Bekleidung | A | NEW | Trockenbauarbeiten | a-sh Deckenbelag | Pset_CoveringCommon - FireRating: -; Reference: Reference; AllplanAttributes - Attributset-Objekt: Covering
a-sh Deckenbelag | WUN-H1-E00 | CEILING | - 0.001 m | 1566Dfl0811551933/03 | m² | 3 | 0.001 | 0 | 1 | Bekleidung | - | NEW | Maler- und Lackierarbeiten | a-sh Deckenbelag | Pset_CoveringCommon - FireRating: -; AllplanAttributes - Attributset-Objekt: Covering
PVC | WUN-H1-E00 | FLOORING | Ku3 0.2 m | 1566Bfl0811551878/01 | m² | 1 | 0.2 | 0 | 1 | Bodenfläche | Ku3 | NEW | Bodenbelagsarbeiten | PVC | AllplanAttributes - Bauteil-ID: 301; Raumnr. Bauherr: 2.11_A2_02; ash B_Aufbau: B1; ash B_Rutschhemmung: R9
Gipsfaserplatten 2-lagig (BSK) | WUN-H1-E00 | CEILING | layer 0.036 m | 1566Dfl0811551930/01 | m² | 1 | 0.036 | 0 | 1 | Bekleidung |  | NEW | Trockenbauarbeiten | Gipsfaserplatten 2-lagig (BSK) | 2.5 | AllplanAttributes - ash_lichte Raumhöhe: 2.65; Attributset-Objekt: Covering; Pset_CoveringCommon - FireRating: für korrekte FläVisu
Gipsfaserplatten 2-lagig (BSK) | WUN-H1-E00 | CEILING | Installationshöhe 0.614 m | 1566Dfl0811551930/02 | m² | 2 | 0.614 | 0 | 1 | Bekleidung | Installationshöhe | NEW | Trockenbauarbeiten |  | 2.5 | AllplanAttributes - ash_lichte Raumhöhe: (4100-36+614+100)/1000-0.7; Attributset-Objekt: Covering; Pset_CoveringCommon - FireRating: für korrekte FläVisu; Reference: Reference
Rasterdecke | WUN-H1-E00 | CEILING | E3 0.1 m | 1566Dfl0811551930/03 | m² | 3 | 0.1 | 0 | 1 | Bekleidung | E3 | NEW | Trockenbauarbeiten | Rasterdecke | 2.5 | AllplanAttributes - ash_lichte Raumhöhe: (4100-36+614+100)/1000-0.7; Attributset-Objekt: Covering; Pset_CoveringCommon - FireRating: -; AcousticRating: -
PVC Bahnenware Uni | WUN-H1-E00 | FLOORING | Ku2 0.2 m | 1566Bfl0811551863/01 | m² | 1 | 0.2 | 0 | 1 | Bodenfläche | Ku2 | NEW | Bodenbelagsarbeiten | PVC Bahnenware Uni | AllplanAttributes - Bauteil-ID: 301; Raumnr. Bauherr: 2.11_A2_02; ash B_Aufbau: B1; ash B_Rutschhemmung: R9
PVC Bahnenware Uni | WUN-H1-E00 | FLOORING | Ku2 0.2 m | 1566Bfl0811551865/01 | m² | 1 | 0.2 | 0 | 1 | Bodenfläche | Ku2 | NEW | Bodenbelagsarbeiten | PVC Bahnenware Uni | AllplanAttributes - Bauteil-ID: 301; Raumnr. Bauherr: 2.11_A2_02; ash B_Aufbau: B1; ash B_Rutschhemmung: R9
PVC Bahnenware Uni | WUN-H1-E00 | FLOORING | Ku2 0.2 m | 1566Bfl0811551877/01 | m² | 1 | 0.2 | 0 | 1 | Bodenfläche | Ku2 | NEW | Bodenbelagsarbeiten | PVC Bahnenware Uni | AllplanAttributes - Bauteil-ID: 301; Raumnr. Bauherr: 2.11_A2_02; ash B_Aufbau: B1; ash B_Rutschhemmung: R9
Gipsfaserplatten 2-lagig (BSK) | WUN-H1-E00 | CEILING | layer 0.036 m | 1566Dfl0811551929/01 | m² | 1 | 0.036 | 0 | 1 | Bekleidung |  | NEW | Trockenbauarbeiten | Gipsfaserplatten 2-lagig (BSK) | 2.5 | AllplanAttributes - ash_lichte Raumhöhe: 2.5; Attributset-Objekt: Covering; Pset_CoveringCommon - FireRating: für korrekte FläVisu
Gipsfaserplatten 2-lagig (BSK) | WUN-H1-E00 | CEILING | Installationshöhe 0.764 m | 1566Dfl0811551929/02 | m² | 2 | 0.764 | 0 | 1 | Bekleidung | Installationshöhe | NEW | Trockenbauarbeiten |  | 2.5 | AllplanAttributes - ash_lichte Raumhöhe: (4100-36+764+100)/1000-0.7; Attributset-Objekt: Covering; Pset_CoveringCommon - FireRating: für korrekte FläVisu; Reference: Reference
Rasterdecke | WUN-H1-E00 | CEILING | E3 0.1 m | 1566Dfl0811551929/03 | m² | 3 | 0.1 | 0 | 1 | Bekleidung | E3 | NEW | Trockenbauarbeiten | Rasterdecke | 2.5 | AllplanAttributes - ash_lichte Raumhöhe: (4100-36+764+100)/1000-0.7; Attributset-Objekt: Covering; Pset_CoveringCommon - FireRating: -; AcousticRating: -
Fliesen Großformat | WUN-H1-E00 | FLOORING | Fl12 0.2 m | 1566Bfl0811551864/01 | m² | 1 | 0.2 | 0 | 1 | Bodenfläche | Fl12 | NEW | Bodenbelagsarbeiten | Fliesen Großformat | AllplanAttributes - Bauteil-ID: 301; Raumnr. Bauherr: 2.11_A2_02; ash B_Aufbau: B4; ash B_Rutschhemmung: R10
Fliesen Großformat | WUN-H1-E00 | FLOORING | Fl12 0.2 m | 1566Bfl0811551886/01 | m² | 1 | 0.2 | 0 | 1 | Bodenfläche | Fl12 | NEW | Bodenbelagsarbeiten | Fliesen Großformat | AllplanAttributes - Bauteil-ID: 301; Raumnr. Bauherr: 2.11_A2_02; ash B_Aufbau: B4; ash B_Rutschhemmung: R10
a-sh Deckenbelag | WUN-H1-E00 | CEILING | Installationshöhe 0.73 m | 1566Dfl0811551938/01 | m² | 1 | 0.73 | 0 | 1 | Bekleidung | Installationshöhe | NEW | Trockenbauarbeiten | a-sh Deckenbelag | AllplanAttributes - ash_lichte Raumhöhe: 2.8; Attributset-Objekt: Covering; Pset_CoveringCommon - FireRating: für korrekte FläVisu
a-sh Deckenbelag | WUN-H1-E00 | CEILING | A 0.35 m | 1566Dfl0811551938/02 | m² | 2 | 0.35 | 0 | 1 | Bekleidung | A | NEW | Trockenbauarbeiten | a-sh Deckenbelag | Pset_CoveringCommon - FireRating: -; Reference: Reference; AllplanAttributes - Attributset-Objekt: Covering
a-sh Deckenbelag | WUN-H1-E00 | CEILING | - 0.001 m | 1566Dfl0811551938/03 | m² | 3 | 0.001 | 0 | 1 | Bekleidung | - | NEW | Maler- und Lackierarbeiten | a-sh Deckenbelag | Pset_CoveringCommon - FireRating: -; AllplanAttributes - Attributset-Objekt: Covering
Fliesen Großformat | WUN-H1-E00 | FLOORING | Fl12 0.2 m | 1566Bfl0811551888/01 | m² | 1 | 0.2 | 0 | 1 | Bodenfläche | Fl12 | NEW | Bodenbelagsarbeiten | Fliesen Großformat | AllplanAttributes - Bauteil-ID: 301; Raumnr. Bauherr: 2.11_A2_02; ash B_Aufbau: B4; ash B_Rutschhemmung: R10
a-sh Deckenbelag | WUN-H1-E00 | CEILING | Installationshöhe 0.73 m | 1566Dfl0811551940/01 | m² | 1 | 0.73 | 0 | 1 | Bekleidung | Installationshöhe | NEW | Trockenbauarbeiten | a-sh Deckenbelag | AllplanAttributes - ash_lichte Raumhöhe: 2.8; Attributset-Objekt: Covering; Pset_CoveringCommon - FireRating: für korrekte FläVisu
a-sh Deckenbelag | WUN-H1-E00 | CEILING | A 0.35 m | 1566Dfl0811551940/02 | m² | 2 | 0.35 | 0 | 1 | Bekleidung | A | NEW | Trockenbauarbeiten | a-sh Deckenbelag | Pset_CoveringCommon - FireRating: -; Reference: Reference; AllplanAttributes - Attributset-Objekt: Covering
a-sh Deckenbelag | WUN-H1-E00 | CEILING | - 0.001 m | 1566Dfl0811551940/03 | m² | 3 | 0.001 | 0 | 1 | Bekleidung | - | NEW | Maler- und Lackierarbeiten | a-sh Deckenbelag | Pset_CoveringCommon - FireRating: -; AllplanAttributes - Attributset-Objekt: Covering
Fliesen Großformat | WUN-H1-E00 | FLOORING | Fl12 0.2 m | 1566Bfl0811551885/01 | m² | 1 | 0.2 | 0 | 1 | Bodenfläche | Fl12 | NEW | Bodenbelagsarbeiten | Fliesen Großformat | AllplanAttributes - Bauteil-ID: 301; Raumnr. Bauherr: 2.11_A2_02; ash B_Aufbau: B4; ash B_Rutschhemmung: R10
a-sh Deckenbelag | WUN-H1-E00 | CEILING | Installationshöhe 0.73 m | 1566Dfl0811551937/01 | m² | 1 | 0.73 | 0 | 1 | Bekleidung | Installationshöhe | NEW | Trockenbauarbeiten | a-sh Deckenbelag | AllplanAttributes - ash_lichte Raumhöhe: 2.8; Attributset-Objekt: Covering; Pset_CoveringCommon - FireRating: für korrekte FläVisu
a-sh Deckenbelag | WUN-H1-E00 | CEILING | A 0.35 m | 1566Dfl0811551937/02 | m² | 2 | 0.35 | 0 | 1 | Bekleidung | A | NEW | Trockenbauarbeiten | a-sh Deckenbelag | Pset_CoveringCommon - FireRating: -; Reference: Reference; AllplanAttributes - Attributset-Objekt: Covering
a-sh Deckenbelag | WUN-H1-E00 | CEILING | - 0.001 m | 1566Dfl0811551937/03 | m² | 3 | 0.001 | 0 | 1 | Bekleidung | - | NEW | Maler- und Lackierarbeiten | a-sh Deckenbelag | Pset_CoveringCommon - FireRating: -; AllplanAttributes - Attributset-Objekt: Covering
Gipsfaserplatten 2-lagig (BSK) | WUN-H1-E00 | CEILING | layer 0.036 m | 1566Dfl0811554171/01 | m² | 1 | 0.036 | 0 | 1 | Bekleidung |  | NEW | Trockenbauarbeiten | Gipsfaserplatten 2-lagig (BSK) | 2.5 | AllplanAttributes - ash_lichte Raumhöhe: 2.75; Attributset-Objekt: Covering; Pset_CoveringCommon - FireRating: für korrekte FläVisu
Gipsfaserplatten 2-lagig (BSK) | WUN-H1-E00 | CEILING | Installationshöhe 0.514 m | 1566Dfl0811554171/02 | m² | 2 | 0.514 | 0 | 1 | Bekleidung | Installationshöhe | NEW | Trockenbauarbeiten |  | 2.5 | AllplanAttributes - ash_lichte Raumhöhe: (4100-36+514+100)/1000-0.7; Attributset-Objekt: Covering; Pset_CoveringCommon - FireRating: für korrekte FläVisu; Reference: Reference
Rasterdecke | WUN-H1-E00 | CEILING | E3 0.1 m | 1566Dfl0811554171/03 | m² | 3 | 0.1 | 0 | 1 | Bekleidung | E3 | NEW | Trockenbauarbeiten | Rasterdecke | 2.5 | AllplanAttributes - ash_lichte Raumhöhe: (4100-36+514+100)/1000-0.7; Attributset-Objekt: Covering; Pset_CoveringCommon - FireRating: -; AcousticRating: -
Gipsfaserplatten 2-lagig (BSK) | WUN-H1-E00 | CEILING | layer 0.036 m | 1566Dfl0811554168/01 | m² | 1 | 0.036 | 0 | 1 | Bekleidung |  | NEW | Trockenbauarbeiten | Gipsfaserplatten 2-lagig (BSK) | 2.5 | AllplanAttributes - ash_lichte Raumhöhe: 2.75; Attributset-Objekt: Covering; Pset_CoveringCommon - FireRating: für korrekte FläVisu
Gipsfaserplatten 2-lagig (BSK) | WUN-H1-E00 | CEILING | Installationshöhe 0.994 m | 1566Dfl0811554168/02 | m² | 2 | 0.994 | 0 | 1 | Bekleidung | Installationshöhe | NEW | Trockenbauarbeiten |  | 2.5 | AllplanAttributes - ash_lichte Raumhöhe: (4580-36+994+100)/1000-0.7; Attributset-Objekt: Covering; Pset_CoveringCommon - FireRating: für korrekte FläVisu; Reference: Reference
Rasterdecke | WUN-H1-E00 | CEILING | E3 0.1 m | 1566Dfl0811554168/03 | m² | 3 | 0.1 | 0 | 1 | Bekleidung | E3 | NEW | Trockenbauarbeiten | Rasterdecke | 2.5 | AllplanAttributes - ash_lichte Raumhöhe: (4580-36+994+100)/1000-0.7; Attributset-Objekt: Covering; Pset_CoveringCommon - FireRating: -; AcousticRating: -
PVC Bahnenware Uni | WUN-H1-E00 | FLOORING | Ku2 0.2 m | 1566Bfl0811551887/01 | m² | 1 | 0.2 | 0 | 1 | Bodenfläche | Ku2 | NEW | Bodenbelagsarbeiten | PVC Bahnenware Uni | AllplanAttributes - Bauteil-ID: 301; Raumnr. Bauherr: 2.11_A2_02; ash B_Aufbau: B1; ash B_Rutschhemmung: R9
PVC Bahnenware Uni | WUN-H1-E00 | FLOORING | Ku2 0.2 m | 1566Bfl0811551869/01 | m² | 1 | 0.2 | 0 | 1 | Bodenfläche | Ku2 | NEW | Bodenbelagsarbeiten | PVC Bahnenware Uni | AllplanAttributes - Bauteil-ID: 301; Raumnr. Bauherr: 2.11_A2_02; ash B_Aufbau: B1; ash B_Rutschhemmung: R9
Gipsfaserplatten 2-lagig (BSK) | WUN-H1-E00 | CEILING | layer 0.036 m | 1566Dfl0811551922/01 | m² | 1 | 0.036 | 0 | 1 | Bekleidung |  | NEW | Trockenbauarbeiten | Gipsfaserplatten 2-lagig (BSK) | 2.5 | AllplanAttributes - ash_lichte Raumhöhe: 2.75; Attributset-Objekt: Covering; Pset_CoveringCommon - FireRating: für korrekte FläVisu
Gipsfaserplatten 2-lagig (BSK) | WUN-H1-E00 | CEILING | Installationshöhe 0.514 m | 1566Dfl0811551922/02 | m² | 2 | 0.514 | 0 | 1 | Bekleidung | Installationshöhe | NEW | Trockenbauarbeiten |  | 2.5 | AllplanAttributes - ash_lichte Raumhöhe: (4100-36+514+100)/1000-0.7; Attributset-Objekt: Covering; Pset_CoveringCommon - FireRating: für korrekte FläVisu; Reference: Reference
Rasterdecke | WUN-H1-E00 | CEILING | E3 0.1 m | 1566Dfl0811551922/03 | m² | 3 | 0.1 | 0 | 1 | Bekleidung | E3 | NEW | Trockenbauarbeiten | Rasterdecke | 2.5 | AllplanAttributes - ash_lichte Raumhöhe: (4100-36+514+100)/1000-0.7; Attributset-Objekt: Covering; Pset_CoveringCommon - FireRating: -; AcousticRating: -
PVC Bahnenware Uni | WUN-H1-E00 | FLOORING | Ku2 0.2 m | 1566Bfl0811551870/01 | m² | 1 | 0.2 | 0 | 1 | Bodenfläche | Ku2 | NEW | Bodenbelagsarbeiten | PVC Bahnenware Uni | AllplanAttributes - Bauteil-ID: 301; Raumnr. Bauherr: 2.11_A2_02; ash B_Aufbau: B1; ash B_Rutschhemmung: R9
Gipsfaserplatten 2-lagig (BSK) | WUN-H1-E00 | CEILING | layer 0.036 m | 1566Dfl0811551923/01 | m² | 1 | 0.036 | 0 | 1 | Bekleidung |  | NEW | Trockenbauarbeiten | Gipsfaserplatten 2-lagig (BSK) | 2.5 | AllplanAttributes - ash_lichte Raumhöhe: 2.75; Attributset-Objekt: Covering; Pset_CoveringCommon - FireRating: für korrekte FläVisu
Gipsfaserplatten 2-lagig (BSK) | WUN-H1-E00 | CEILING | Installationshöhe 0.514 m | 1566Dfl0811551923/02 | m² | 2 | 0.514 | 0 | 1 | Bekleidung | Installationshöhe | NEW | Trockenbauarbeiten |  | 2.5 | AllplanAttributes - ash_lichte Raumhöhe: (4100-36+514+100)/1000-0.7; Attributset-Objekt: Covering; Pset_CoveringCommon - FireRating: für korrekte FläVisu; Reference: Reference
Rasterdecke | WUN-H1-E00 | CEILING | E3 0.1 m | 1566Dfl0811551923/03 | m² | 3 | 0.1 | 0 | 1 | Bekleidung | E3 | NEW | Trockenbauarbeiten | Rasterdecke | 2.5 | AllplanAttributes - ash_lichte Raumhöhe: (4100-36+514+100)/1000-0.7; Attributset-Objekt: Covering; Pset_CoveringCommon - FireRating: -; AcousticRating: -
Streifenfundament | H1 Gründung |  | STB | 1511SFu0000003843 | m |  |  |  |  | Fundament | STB | NEW | Betonarbeiten | Streifenfundament | Pset_CoveringCommon - Reference: Codetext; IsExternal: yes; AllplanAttributes - 2D Interaktion: yes; Codetext: Codetext; Tragendes Bauteil: yes

# IfcDoor (2)
In: H1 Ebene 0
PredefinedType: DOOR; OperationType: USERDEFINED; Material: TI-1F-UZ-ZK
AllplanAttributes (SMT) - Gewerk: Metallbau-, Schlosserarbeiten; V6: 0 m; V7: 0 m; V8: 0 m; V9: 0; Ortscode_Geschoßbezeichnung: E00; Programmversion: 3.1; Objektname: Türmakro; Text1: 39; Bezeichnung: SMT; Material: TI-1F-UZ-ZK; Plugin_Bezeichnung: MainObject; Plugin_Objektname: SmartPartCompressed; Glasanteil_berücksichtigen: 100; Version: 7.21; ash T_Sichtschutz: -; ash R_Verweis Wandansicht: -; ash T_Zulage Schachttür: no; ash T_Dichtschließend: no; ash T_Panik: -; ash T_Zarge_Typ: UZ; ash T_Türschließer: OTS; ash T_Gewerk Los: -; ash T_Erforderl. Durchgangsbreite: 0 m; ash T_Türblatt sichtbar 2D: ja; ash T_Zusatzfunktion Panikschloss: -; ash T_Fluchtwegsicherung: -; ash T_Standflügel-Betätigung: -; ash T_Zusatzfunktion Türschließer: -; ash T_Türschließer-Montage: -; ash T_Feststellanlage (FSA): -; ash T_Zusätzliche Rauchmelder: -; ash T_Zusätzl. Anschluss an BMA: -; ash T_Impulsgeber: -; ash T_Sicherheits-Sensorleisten: -; ash T_Anschl. an Einbruchmeld.anl.: -; ash T_Klemmschutz: -; ash T_LV-Positions-Nr.: -; ash T_Plan-Nr.: -; ash T_Sonstiges, Bemerkungen: -; OKFF: 0; ash T_Bodentürstopper: -; ash T_nicht abschließbar: no; ash T_Material Seitenteil: -; ash T_Strahlenschutz: 0.000000; ash T_Tür-Nr.: E00-028-001-39; ash T_Kantengeometrie: 2F; ash T_Kantenmaterial: PU; ash T_Blatt_Oberfläche: HPL; ash T_Erford. Durgangshöhe: 0 m; ash T_Rammschutz: BL; ash T_Fluchtwegrichtung: -; ash T_Anschlag Gangflügel: -; ash T_Bodendichtung: -; ash T_Lüftungsgitter: 0 m2; ash T_Feuchtebeständigkeit: -; ash T_E_Öffner: -; ash T_Automatik_Antrieb: -; ash T_Sturz: -; ash T_Blatt_Material: HO; ash T_Schlossfunktion: -; ash T_Schliesszylinder: PZ; ash T_Beschlag: KD; ash T_Glasausschnitt: -; ash T_Sonder_Wandmaterial: -; ash T_Anz_Reedkontakte: 0; ash T_Anz_Riegelkontakte: 0; ash T_Schallschutz: -; ash T_Zarge_Material: ST; ash T_Bodeneinstand: -; ash T_Raum zugehörigkeit: BGS; ash T_Blatt_Farbe: -; Positionsnummer_Text: S68; Attributset-Objekt: Door; P_ID: 1115Rau0000005119; Abrechnungsart: St
AllplanQuantities - HeightWindowSillOutside: 0; HeightWindowSillInside: 0; OffsetOpeningBottom: 200; OffsetOpeningTop: 0; OffsetOpeningLeft: 0; OffsetOpeningRight: 0; DeductionOpeningBottom: 100; DeductionOpeningLeft: 40; DeductionOpeningRight: 40; DeductionOpeningTop: 40
Pset_DoorCommon - Status: NEW; IsExternal: no; FireRating: EI2 30; ThermalTransmittance: 0 W/K/m2; HandicapAccessible: no; SmokeStop: yes; SelfClosing: yes; FireExit: no
Name | OverallHeight (m) | OverallWidth (m) | Allright_Bauteil_ID | GlassSurface
SMT | 2.75 | 1.99997 | 1555Mak0811456250 | 4.00115
SMT | 2.95 | 2.99999 | 1555Mak0811452219 | 6.90699

# IfcDoor: SMT
In: H1 Ebene 0
Type - PredefinedType: DOOR; OperationType: DOUBLE_DOOR_SINGLE_SWING; ParameterTakesPrecedence: no
Type - IfcDoorLiningProperties - LiningDepth: 0.15 m; LiningThickness: 0.07 m
OverallHeight: 2.95 m; OverallWidth: 2.5 m; Material: TI-1F-UZ-ZK
AllplanAttributes (SMT) - Gewerk: Metallbau-, Schlosserarbeiten; V6: 0 m; V7: 0 m; V8: 0 m; V9: 0; Ortscode_Geschoßbezeichnung: E00; Programmversion: 3.1; Objektname: Türmakro; Text1: 39; Bezeichnung: SMT; Material: TI-1F-UZ-ZK; Plugin_Bezeichnung: MainObject; Plugin_Objektname: SmartPartCompressed; Glasanteil_berücksichtigen: 100; Version: 7.21; ash T_Sichtschutz: -; ash R_Verweis Wandansicht: -; ash T_Zulage Schachttür: no; ash T_Dichtschließend: no; ash T_Panik: -; ash T_Zarge_Typ: UZ; ash T_Türschließer: OTS; ash T_Gewerk Los: -; ash T_Erforderl. Durchgangsbreite: 0 m; ash T_Türblatt sichtbar 2D: ja; ash T_Zusatzfunktion Panikschloss: -; ash T_Fluchtwegsicherung: -; ash T_Standflügel-Betätigung: -; ash T_Zusatzfunktion Türschließer: -; ash T_Türschließer-Montage: -; ash T_Feststellanlage (FSA): -; ash T_Zusätzliche Rauchmelder: -; ash T_Zusätzl. Anschluss an BMA: -; ash T_Impulsgeber: -; ash T_Sicherheits-Sensorleisten: -; ash T_Anschl. an Einbruchmeld.anl.: -; ash T_Klemmschutz: -; ash T_LV-Positions-Nr.: -; ash T_Plan-Nr.: -; ash T_Sonstiges, Bemerkungen: -; OKFF: 0; ash T_Bodentürstopper: -; ash T_nicht abschließbar: no; ash T_Material Seitenteil: -; ash T_Strahlenschutz: 0.000000; ash T_Tür-Nr.: E00-028-001-39; ash T_Kantengeometrie: 2F; ash T_Kantenmaterial: PU; ash T_Blatt_Oberfläche: HPL; ash T_Erford. Durgangshöhe: 0 m; ash T_Rammschutz: BL; ash T_Fluchtwegrichtung: -; ash T_Anschlag Gangflügel: -; ash T_Bodendichtung: -; ash T_Lüftungsgitter: 0 m2; ash T_Feuchtebeständigkeit: -; ash T_E_Öffner: -; ash T_Automatik_Antrieb: -; ash T_Sturz: -; ash T_Blatt_Material: HO; ash T_Schlossfunktion: -; ash T_Schliesszylinder: PZ; ash T_Beschlag: KD; ash T_Glasausschnitt: -; ash T_Sonder_Wandmaterial: -; ash T_Anz_Reedkontakte: 0; ash T_Anz_Riegelkontakte: 0; ash T_Schallschutz: -; ash T_Zarge_Material: ST; ash T_Bodeneinstand: -; ash T_Raum zugehörigkeit: BGS; ash T_Blatt_Farbe: -; Positionsnummer_Text: S68; Attributset-Objekt: Door; P_ID: 1115Rau0000005119; Allright_Bauteil_ID: 1555Mak0811452218; Abrechnungsart: St
AllplanQuantities - GlassSurface: 5.84379; HeightWindowSillOutside: 0; HeightWindowSillInside: 0; OffsetOpeningBottom: 200; OffsetOpeningTop: 0; OffsetOpeningLeft: 0; OffsetOpeningRight: 0; DeductionOpeningBottom: 100; DeductionOpeningLeft: 40; DeductionOpeningRight: 40; DeductionOpeningTop: 40
Pset_DoorCommon - Status: NEW; IsExternal: no; FireRating: EI2 30; ThermalTransmittance: 0 W/K/m2; HandicapAccessible: no; SmokeStop: yes; SelfClosing: yes; FireExit: no

# IfcDoor: SMT
In: H1 Ebene 0
Type - PredefinedType: DOOR; OperationType: SINGLE_SWING_LEFT; ParameterTakesPrecedence: no
Type - IfcDoorLiningProperties - LiningDepth: 0.262 m; LiningThickness: 0.04 m
OverallHeight: 2.46 m; OverallWidth: 1.135 m; Material: TI-1F-UZ-ZK
AllplanAttributes (SMT) - Gewerk: Metallbau-, Schlosserarbeiten; V6: 0 m; V7: 0 m; V8: 0 m; V9: 0; Ortscode_Geschoßbezeichnung: E00; Programmversion: 3.1; Objektname: Türmakro; Text1: 39; Bezeichnung: SMT; Material: TI-1F-UZ-ZK; Plugin_Bezeichnung: MainObject; Plugin_Objektname: SmartPartCompressed; Glasanteil_berücksichtigen: 100; Version: 7.21; ash T_Sichtschutz: -; ash R_Verweis Wandansicht: -; ash T_Zulage Schachttür: no; ash T_Dichtschließend: no; ash T_Panik: -; ash T_Zarge_Typ: UZ; ash T_Türschließer: OTS; ash T_Gewerk Los: -; ash T_Erforderl. Durchgangsbreite: 0 m; ash T_Türblatt sichtbar 2D: ja; ash T_Zusatzfunktion Panikschloss: -; ash T_Fluchtwegsicherung: -; ash T_Standflügel-Betätigung: -; ash T_Zusatzfunktion Türschließer: -; ash T_Türschließer-Montage: -; ash T_Feststellanlage (FSA): -; ash T_Zusätzliche Rauchmelder: -; ash T_Zusätzl. Anschluss an BMA: -; ash T_Impulsgeber: -; ash T_Sicherheits-Sensorleisten: -; ash T_Anschl. an Einbruchmeld.anl.: -; ash T_Klemmschutz: -; ash T_LV-Positions-Nr.: -; ash T_Plan-Nr.: -; ash T_Sonstiges, Bemerkungen: -; OKFF: 0; ash T_Bodentürstopper: -; ash T_nicht abschließbar: no; ash T_Material Seitenteil: -; ash T_Strahlenschutz: 0.000000; ash T_Tür-Nr.: E00-028-001-39; ash T_Kantengeometrie: 2F; ash T_Kantenmaterial: PU; ash T_Blatt_Oberfläche: HPL; ash T_Erford. Durgangshöhe: 0 m; ash T_Rammschutz: BL; ash T_Fluchtwegrichtung: -; ash T_Anschlag Gangflügel: -; ash T_Bodendichtung: -; ash T_Lüftungsgitter: 0 m2; ash T_Feuchtebeständigkeit: -; ash T_E_Öffner: -; ash T_Automatik_Antrieb: -; ash T_Sturz: -; ash T_Blatt_Material: HO; ash T_Schlossfunktion: -; ash T_Schliesszylinder: PZ; ash T_Beschlag: KD; ash T_Glasausschnitt: -; ash T_Sonder_Wandmaterial: -; ash T_Anz_Reedkontakte: 0; ash T_Anz_Riegelkontakte: 0; ash T_Schallschutz: -; ash T_Zarge_Material: ST; ash T_Bodeneinstand: -; ash T_Raum zugehörigkeit: BGS; ash T_Blatt_Farbe: -; Positionsnummer_Text: S68; Attributset-Objekt: Door; P_ID: 1115Rau0000005119; Allright_Bauteil_ID: 1563Mak0813612187; Abrechnungsart: St
AllplanQuantities - GlassSurface: 0; HeightWindowSillOutside: 0; HeightWindowSillInside: 0; OffsetOpeningBottom: 200; OffsetOpeningTop: 0; OffsetOpeningLeft: 0; OffsetOpeningRight: 0; DeductionOpeningBottom: 100; DeductionOpeningLeft: 40; DeductionOpeningRight: 40; DeductionOpeningTop: 40
Pset_DoorCommon - Status: NEW; IsExternal: no; FireRating: EI2 30; ThermalTransmittance: 0 W/K/m2; HandicapAccessible: no; SmokeStop: yes; SelfClosing: yes; FireExit: no

# IfcDoor: SMT (3)
In: H1 Ebene 0
Type - PredefinedType: DOOR; OperationType: SINGLE_SWING_RIGHT; ParameterTakesPrecedence: no
Type - IfcDoorLiningProperties - LiningDepth: 0.07 m; LiningThickness: 0.04 m
OverallHeight: 2.46 m; OverallWidth: 0.76 m; Material: TI-1F-UZ-ZK
AllplanAttributes (SMT) - Gewerk: Metallbau-, Schlosserarbeiten; V6: 0 m; V7: 0 m; V8: 0 m; V9: 0; Ortscode_Geschoßbezeichnung: E00; Programmversion: 3.1; Objektname: Türmakro; Text1: 39; Bezeichnung: SMT; Material: TI-1F-UZ-ZK; Plugin_Bezeichnung: MainObject; Plugin_Objektname: SmartPartCompressed; Glasanteil_berücksichtigen: 100; Version: 7.21; ash T_Sichtschutz: -; ash R_Verweis Wandansicht: -; ash T_Zulage Schachttür: no; ash T_Dichtschließend: no; ash T_Panik: -; ash T_Zarge_Typ: UZ; ash T_Türschließer: OTS; ash T_Gewerk Los: -; ash T_Erforderl. Durchgangsbreite: 0 m; ash T_Türblatt sichtbar 2D: ja; ash T_Zusatzfunktion Panikschloss: -; ash T_Fluchtwegsicherung: -; ash T_Standflügel-Betätigung: -; ash T_Zusatzfunktion Türschließer: -; ash T_Türschließer-Montage: -; ash T_Feststellanlage (FSA): -; ash T_Zusätzliche Rauchmelder: -; ash T_Zusätzl. Anschluss an BMA: -; ash T_Impulsgeber: -; ash T_Sicherheits-Sensorleisten: -; ash T_Anschl. an Einbruchmeld.anl.: -; ash T_Klemmschutz: -; ash T_LV-Positions-Nr.: -; ash T_Plan-Nr.: -; ash T_Sonstiges, Bemerkungen: -; OKFF: 0; ash T_Bodentürstopper: -; ash T_nicht abschließbar: no; ash T_Material Seitenteil: -; ash T_Strahlenschutz: 0.000000; ash T_Tür-Nr.: E00-028-001-39; ash T_Kantengeometrie: 2F; ash T_Kantenmaterial: PU; ash T_Blatt_Oberfläche: HPL; ash T_Erford. Durgangshöhe: 0 m; ash T_Rammschutz: BL; ash T_Fluchtwegrichtung: -; ash T_Anschlag Gangflügel: -; ash T_Bodendichtung: -; ash T_Lüftungsgitter: 0 m2; ash T_Feuchtebeständigkeit: -; ash T_E_Öffner: -; ash T_Automatik_Antrieb: -; ash T_Sturz: -; ash T_Blatt_Material: HO; ash T_Schlossfunktion: -; ash T_Schliesszylinder: PZ; ash T_Beschlag: KD; ash T_Glasausschnitt: -; ash T_Sonder_Wandmaterial: -; ash T_Anz_Reedkontakte: 0; ash T_Anz_Riegelkontakte: 0; ash T_Schallschutz: -; ash T_Zarge_Material: ST; ash T_Bodeneinstand: -; ash T_Raum zugehörigkeit: BGS; ash T_Blatt_Farbe: -; Positionsnummer_Text: S68; Attributset-Objekt: Door; P_ID: 1115Rau0000005119; Abrechnungsart: St
AllplanQuantities - GlassSurface: 0; HeightWindowSillOutside: 0; HeightWindowSillInside: 0; OffsetOpeningBottom: 200; OffsetOpeningTop: 0; OffsetOpeningLeft: 0; OffsetOpeningRight: 0; DeductionOpeningBottom: 100; DeductionOpeningLeft: 40; DeductionOpeningRight: 40; DeductionOpeningTop: 40
Pset_DoorCommon - Status: NEW; IsExternal: no; FireRating: EI2 30; ThermalTransmittance: 0 W/K/m2; HandicapAccessible: no; SmokeStop: yes; SelfClosing: yes; FireExit: no
Name | Allright_Bauteil_ID
SMT | 1563Mak0813612195
SMT | 1563Mak0813612198
SMT | 1563Mak0813612191

# IfcDoor: SMT (4)
In: H1 Ebene 0
Type - PredefinedType: DOOR; OperationType: SINGLE_SWING_RIGHT; ParameterTakesPrecedence: no
Type - IfcDoorLiningProperties - LiningDepth: 0.08 m; LiningThickness: 0.07 m
Material: TA-1F-AG-D
AllplanAttributes (SMT) - Gewerk: Metallbau-, Schlosserarbeiten; V6: 0 m; V7: 0 m; V8: 0 m; V9: 0; Ortscode_Geschoßbezeichnung: E00; Programmversion: 3.1; Objektname: Türmakro; Text1: 3; Bezeichnung: SMT; Material: TA-1F-AG-D; Plugin_Bezeichnung: MainObject; Plugin_Objektname: SmartPartCompressed; Glasanteil_berücksichtigen: 100; Version: 7.21; ash T_Sichtschutz: -; ash T_Zulage Schachttür: no; ash T_Dichtschließend: no; ash T_Panik: -; ash T_Zarge_Typ: -; ash T_Türschließer: OTS; ash T_Gewerk Los: -; ash T_Erforderl. Durchgangsbreite: 0 m; ash T_Türblatt sichtbar 2D: ja; ash T_Zusatzfunktion Panikschloss: -; ash T_Fluchtwegsicherung: -; ash T_Standflügel-Betätigung: -; ash T_Zusatzfunktion Türschließer: -; ash T_Türschließer-Montage: -; ash T_Feststellanlage (FSA): -; ash T_Zusätzliche Rauchmelder: -; ash T_Zusätzl. Anschluss an BMA: -; ash T_Impulsgeber: -; ash T_Sicherheits-Sensorleisten: -; ash T_Anschl. an Zuttrittskontrolle: -; ash T_Anschl. an Einbruchmeld.anl.: -; ash T_Klemmschutz: -; ash T_LV-Positions-Nr.: -; ash T_Plan-Nr.: -; ash T_Sonstiges, Bemerkungen: -; OKFF: 0; ash T_Bodentürstopper: -; ash T_nicht abschließbar: no; ash T_Türtyp Nr.: -; ash T_Material Seitenteil: -; ash T_Strahlenschutz: 0.000000; ash T_Tür-Nr.: TA-1FL-D-E00-011; ash T_Kantengeometrie: -; ash T_Kantenmaterial: -; ash T_Blatt_Oberfläche: -; ash T_Erford. Durgangshöhe: 0 m; ash T_Laserschutz: -; ash T_Rammschutz: -; ash T_Fluchtwegrichtung: -; ash T_Anschlag Gangflügel: -; ash T_Bodendichtung: -; ash T_Lüftungsgitter: 0 m2; ash T_Feuchtebeständigkeit: -; ash T_E_Öffner: -; ash T_Automatik_Antrieb: -; ash T_Sturz: -; ash T_Blatt_Material: -; ash T_Schlossfunktion: SVP; ash T_Schliesszylinder: PZ; ash T_Beschlag: KD; ash T_Material Oberlicht: -; ash T_Glasausschnitt: -; ash T_Sonder_Wandmaterial: -; ash T_Anz_Reedkontakte: 0; ash T_Anz_Riegelkontakte: 0; ash T_Schallschutz: -; ash T_Zarge_Material: S; ash T_Bodeneinstand: -; ash T_Raum zugehörigkeit: BS; ash T_Blatt_Farbe: -; ash D_Detailverweis: Typ9; ash D_Plannummer: D1756; g-Wert: 0,51; Positionsnummer_Text: U23; Attributset-Objekt: Door; P_ID: 1115Rau0000005069; Abrechnungsart: St
AllplanQuantities - HeightWindowSillOutside: 0; HeightWindowSillInside: 0; OffsetOpeningBottom: 200; OffsetOpeningTop: 0; OffsetOpeningLeft: 0; OffsetOpeningRight: 0; DeductionOpeningBottom: 10; DeductionOpeningLeft: 70; DeductionOpeningRight: 70; DeductionOpeningTop: 70
Pset_DoorCommon - Status: NEW; IsExternal: yes; FireRating: 0; ThermalTransmittance: 1 W/K/m2; AcousticRating: 32; SmokeStop: no; SelfClosing: no; SecurityRating: RC 2; Reference: T_Typ9
Name | OverallHeight (m) | OverallWidth (m) | Allright_Bauteil_ID | GlassSurface
SMT | 2.95 | 1.26 | 1555Mak0811452140 | 2.4
SMT | 2.95 | 1.26 | 1555Mak0811452144 | 2.4
SMT | 3.85 | 1.85 | 1555Mak0811452226 | 5.1292
SMT | 3.85 | 1.85 | 1555Mak0811452227 | 5.1292

# IfcDoor: SMT
In: H1 Ebene 0
Type - PredefinedType: DOOR; OperationType: SINGLE_SWING_RIGHT; ParameterTakesPrecedence: no
Type - IfcDoorLiningProperties - LiningDepth: 0.13 m; LiningThickness: 0.04 m
OverallHeight: 2.46 m; OverallWidth: 1 m; Material: TI-1F-UZ-ZK
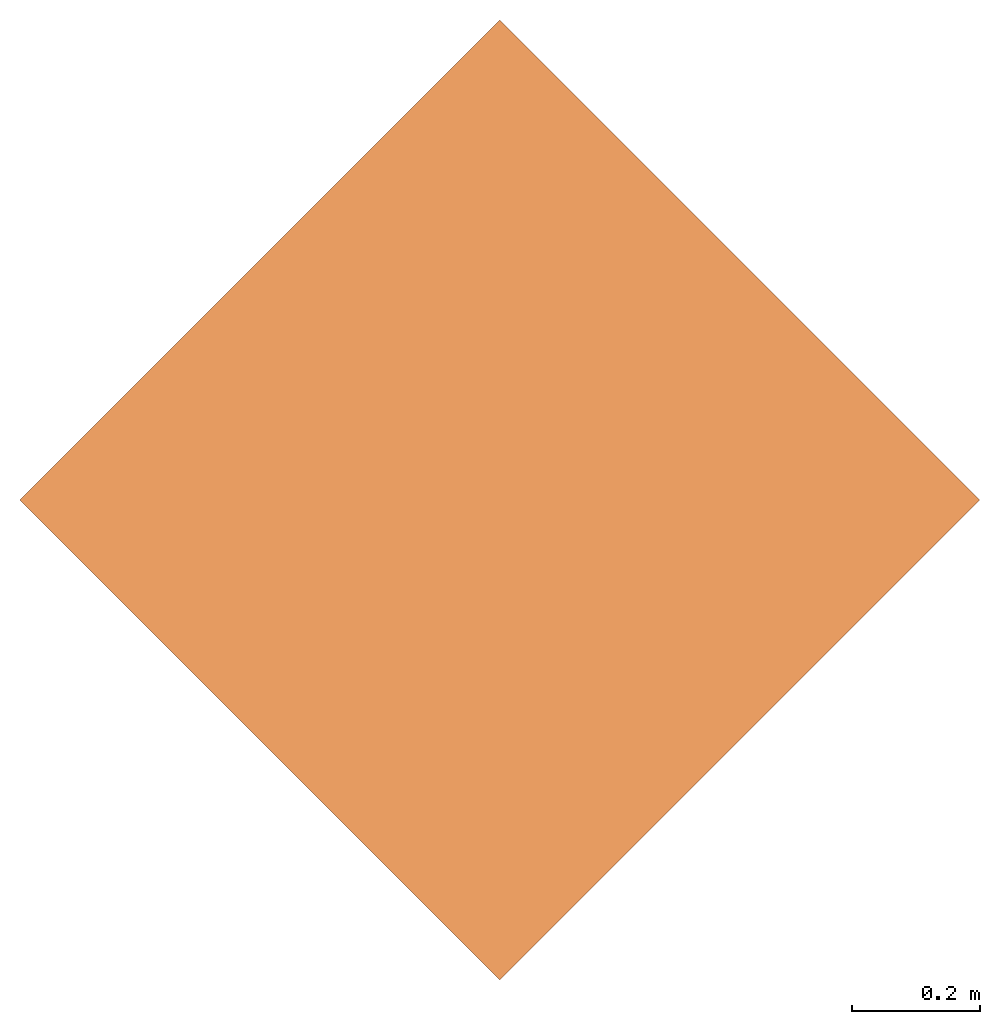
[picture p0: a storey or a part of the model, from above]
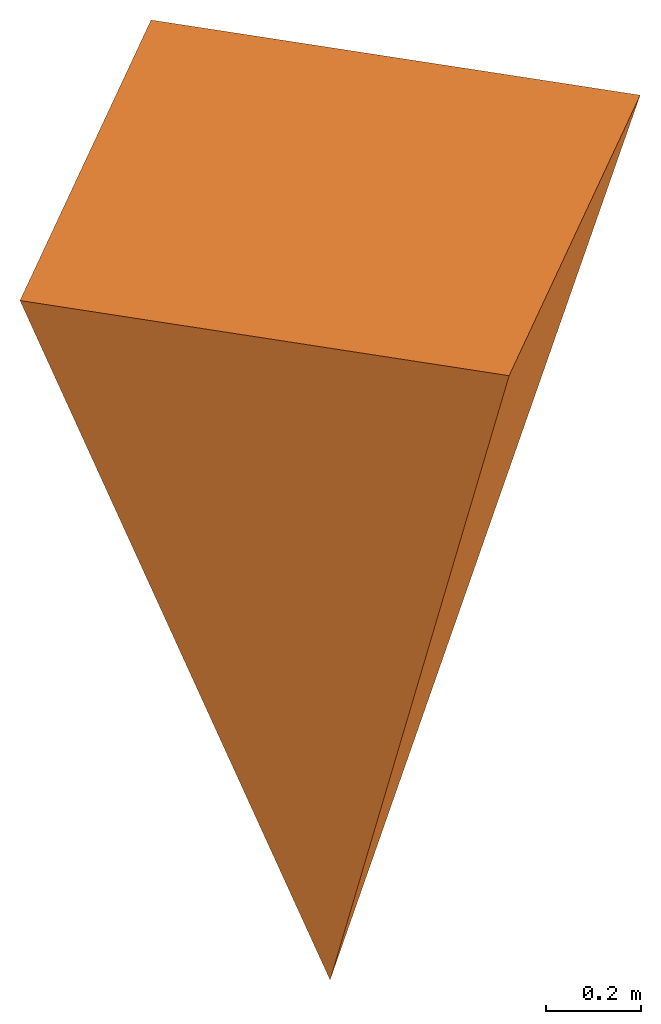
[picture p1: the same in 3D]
Properties of the parts of a building model (IFC4), part 2 of 4

# IfcDoor: SMT
AllplanAttributes (SMT) - Gewerk: Metallbau-, Schlosserarbeiten; V6: 0 m; V7: 0 m; V8: 0 m; V9: 0; Ortscode_Geschoßbezeichnung: E00; Programmversion: 3.1; Objektname: Türmakro; Text1: 39; Bezeichnung: SMT; Material: TI-1F-UZ-ZK; Plugin_Bezeichnung: MainObject; Plugin_Objektname: SmartPartCompressed; Glasanteil_berücksichtigen: 100; Version: 7.21; ash T_Sichtschutz: -; ash R_Verweis Wandansicht: -; ash T_Zulage Schachttür: no; ash T_Dichtschließend: no; ash T_Panik: -; ash T_Zarge_Typ: UZ; ash T_Türschließer: OTS; ash T_Gewerk Los: -; ash T_Erforderl. Durchgangsbreite: 0 m; ash T_Türblatt sichtbar 2D: ja; ash T_Zusatzfunktion Panikschloss: -; ash T_Fluchtwegsicherung: -; ash T_Standflügel-Betätigung: -; ash T_Zusatzfunktion Türschließer: -; ash T_Türschließer-Montage: -; ash T_Feststellanlage (FSA): -; ash T_Zusätzliche Rauchmelder: -; ash T_Zusätzl. Anschluss an BMA: -; ash T_Impulsgeber: -; ash T_Sicherheits-Sensorleisten: -; ash T_Anschl. an Einbruchmeld.anl.: -; ash T_Klemmschutz: -; ash T_LV-Positions-Nr.: -; ash T_Plan-Nr.: -; ash T_Sonstiges, Bemerkungen: -; OKFF: 0; ash T_Bodentürstopper: -; ash T_nicht abschließbar: no; ash T_Material Seitenteil: -; ash T_Strahlenschutz: 0.000000; ash T_Tür-Nr.: E00-028-001-39; ash T_Kantengeometrie: 2F; ash T_Kantenmaterial: PU; ash T_Blatt_Oberfläche: HPL; ash T_Erford. Durgangshöhe: 0 m; ash T_Rammschutz: BL; ash T_Fluchtwegrichtung: -; ash T_Anschlag Gangflügel: -; ash T_Bodendichtung: -; ash T_Lüftungsgitter: 0 m2; ash T_Feuchtebeständigkeit: -; ash T_E_Öffner: -; ash T_Automatik_Antrieb: -; ash T_Sturz: -; ash T_Blatt_Material: HO; ash T_Schlossfunktion: -; ash T_Schliesszylinder: PZ; ash T_Beschlag: KD; ash T_Glasausschnitt: -; ash T_Sonder_Wandmaterial: -; ash T_Anz_Reedkontakte: 0; ash T_Anz_Riegelkontakte: 0; ash T_Schallschutz: -; ash T_Zarge_Material: ST; ash T_Bodeneinstand: -; ash T_Raum zugehörigkeit: BGS; ash T_Blatt_Farbe: -; Positionsnummer_Text: S68; Attributset-Objekt: Door; P_ID: 1115Rau0000005119; Allright_Bauteil_ID: 1563Mak0813612252; Abrechnungsart: St
AllplanQuantities - GlassSurface: 0; HeightWindowSillOutside: 0; HeightWindowSillInside: 0; OffsetOpeningBottom: 200; OffsetOpeningTop: 0; OffsetOpeningLeft: 0; OffsetOpeningRight: 0; DeductionOpeningBottom: 100; DeductionOpeningLeft: 40; DeductionOpeningRight: 40; DeductionOpeningTop: 40
Pset_DoorCommon - Status: NEW; IsExternal: no; FireRating: EI2 30; ThermalTransmittance: 0 W/K/m2; HandicapAccessible: no; SmokeStop: yes; SelfClosing: yes; FireExit: no

# IfcDoor: SMT (27)
Type - PredefinedType: DOOR; OperationType: SINGLE_SWING_RIGHT; ParameterTakesPrecedence: no
Type - IfcDoorLiningProperties - LiningDepth: 0.18 m; LiningThickness: 0.04 m
Material: TI-1F-UZ-ZK
AllplanAttributes (SMT) - Gewerk: Metallbau-, Schlosserarbeiten; V6: 0 m; V7: 0 m; V8: 0 m; V9: 0; Programmversion: 3.1; Objektname: Türmakro; Bezeichnung: SMT; Material: TI-1F-UZ-ZK; Plugin_Bezeichnung: MainObject; Plugin_Objektname: SmartPartCompressed; Glasanteil_berücksichtigen: 100; Version: 7.21; ash T_Sichtschutz: -; ash R_Verweis Wandansicht: -; ash T_Zulage Schachttür: no; ash T_Panik: -; ash T_Zarge_Typ: UZ; ash T_Gewerk Los: -; ash T_Erforderl. Durchgangsbreite: 0 m; ash T_Türblatt sichtbar 2D: ja; ash T_Zusatzfunktion Panikschloss: -; ash T_Fluchtwegsicherung: -; ash T_Standflügel-Betätigung: -; ash T_Zusatzfunktion Türschließer: -; ash T_Türschließer-Montage: -; ash T_Feststellanlage (FSA): -; ash T_Zusätzliche Rauchmelder: -; ash T_Zusätzl. Anschluss an BMA: -; ash T_Impulsgeber: -; ash T_Sicherheits-Sensorleisten: -; ash T_Anschl. an Einbruchmeld.anl.: -; ash T_Klemmschutz: -; ash T_LV-Positions-Nr.: -; ash T_Plan-Nr.: -; ash T_Sonstiges, Bemerkungen: -; ash T_Bodentürstopper: -; ash T_nicht abschließbar: no; ash T_Material Seitenteil: -; ash T_Strahlenschutz: 0.000000; ash T_Kantengeometrie: 2F; ash T_Kantenmaterial: PU; ash T_Blatt_Oberfläche: HPL; ash T_Erford. Durgangshöhe: 0 m; ash T_Rammschutz: BL; ash T_Fluchtwegrichtung: -; ash T_Anschlag Gangflügel: -; ash T_Lüftungsgitter: 0 m2; ash T_Feuchtebeständigkeit: -; ash T_E_Öffner: -; ash T_Automatik_Antrieb: -; ash T_Sturz: -; ash T_Blatt_Material: HO; ash T_Schlossfunktion: -; ash T_Schliesszylinder: PZ; ash T_Glasausschnitt: -; ash T_Sonder_Wandmaterial: -; ash T_Anz_Reedkontakte: 0; ash T_Anz_Riegelkontakte: 0; ash T_Zarge_Material: ST; ash T_Bodeneinstand: -; ash T_Blatt_Farbe: -; Attributset-Objekt: Door; Abrechnungsart: St
AllplanQuantities - GlassSurface: 0; HeightWindowSillOutside: 0; HeightWindowSillInside: 0; OffsetOpeningTop: 0; OffsetOpeningLeft: 0; OffsetOpeningRight: 0; DeductionOpeningBottom: 100; DeductionOpeningLeft: 40; DeductionOpeningRight: 40; DeductionOpeningTop: 40
Pset_DoorCommon - Status: NEW; IsExternal: no; ThermalTransmittance: 0 W/K/m2; HandicapAccessible: no; FireExit: no
Name | In | OverallHeight (m) | OverallWidth (m) | Ortscode_Geschoßbezeichnung | Text1 | ash T_Dichtschließend | ash T_Türschließer | OKFF | ash T_Tür-Nr. | ash T_Bodendichtung | ash T_Beschlag | ash T_Schallschutz | ash T_Raum zugehörigkeit | Positionsnummer_Text | P_ID | Allright_Bauteil_ID | OffsetOpeningBottom | SmokeStop = SelfClosing | FireRating
SMT | H1 Ebene +1 | 2.41 | 1.01 | E01 | 41 | yes | - | 3.75 | E01-037-001-41 | Ja | DK | 27 dB | BS | U100 | 1166Rau0000033512 | 1613Mak2005708159 | 150 | no | AllplanAttributes (SMT) - ash T_Anschl. an Zuttrittskontrolle: -
SMT | H1 Ebene +1 | 2.41 | 0.885 | E00 | 39 | no | OTS | 0 | E00-028-001-39 | - | KD | - | BGS | S68 | 1115Rau0000005119 | 1613Mak2005707907 | 150 | yes | EI2 30
SMT | H1 Ebene +1 | 2.41 | 0.885 | E00 | 39 | no | OTS | 0 | E00-028-001-39 | - | KD | - | BGS | S68 | 1115Rau0000005119 | 1613Mak2005707910 | 150 | yes | EI2 30
SMT | H1 Ebene +1 | 2.41 | 0.885 | E00 | 39 | no | OTS | 0 | E00-028-001-39 | - | KD | - | BGS | S68 | 1115Rau0000005119 | 1613Mak2005707913 | 150 | yes | EI2 30
SMT | H1 Ebene +1 | 2.41 | 1.01 | E01 | 41 | yes | - | 3.75 | E01-037-001-41 | Ja | DK | 27 dB | BS | U100 | 1166Rau0000033512 | 1613Mak2005708163 | 150 | no | AllplanAttributes (SMT) - ash T_Anschl. an Zuttrittskontrolle: -
SMT | H1 Ebene 0 | 2.46 | 1.01 | E00 | 39 | no | OTS | 0 | E00-028-001-39 | - | KD | - | BGS | S68 | 1115Rau0000005119 | 1563Mak0813612281 | 200 | yes | EI2 30
SMT | H1 Ebene 0 | 2.46 | 1.135 | E00 | 39 | no | OTS | 0 | E00-028-001-39 | - | KD | - | BGS | S68 | 1115Rau0000005119 | 1563Mak0813612267 | 200 | yes | EI2 30
SMT | H1 Ebene 0 | 2.46 | 0.885 | E00 | 39 | no | OTS | 0 | E00-028-001-39 | - | KD | - | BGS | S68 | 1115Rau0000005119 | 1563Mak0813612270 | 200 | yes | EI2 30
SMT | H1 Ebene 0 | 2.46 | 0.885 | E00 | 39 | no | OTS | 0 | E00-028-001-39 | - | KD | - | BGS | S68 | 1115Rau0000005119 | 1563Mak0813612274 | 200 | yes | EI2 30
SMT | H1 Ebene 0 | 2.46 | 0.885 | E00 | 39 | no | OTS | 0 | E00-028-001-39 | - | KD | - | BGS | S68 | 1115Rau0000005119 | 1563Mak0813612277 | 200 | yes | EI2 30
SMT | H1 Ebene 0 | 2.46 | 0.885 | E00 | 39 | no | OTS | 0 | E00-028-001-39 | - | KD | - | BGS | S68 | 1115Rau0000005119 | 1563Mak0813612228 | 200 | yes | EI2 30
SMT | H1 Ebene 0 | 2.46 | 1.01 | E00 | 39 | no | OTS | 0 | E00-028-001-39 | - | KD | - | BGS | S68 | 1115Rau0000005119 | 1563Mak0813612225 | 200 | yes | EI2 30
SMT | H1 Ebene 0 | 2.46 | 1.01 | E00 | 39 | no | OTS | 0 | E00-028-001-39 | - | KD | - | BGS | S68 | 1115Rau0000005119 | 1563Mak0813612264 | 200 | yes | EI2 30
SMT | H1 Ebene 0 | 2.46 | 1.15 | E00 | 39 | no | OTS | 0 | E00-028-001-39 | - | KD | - | BGS | S68 | 1115Rau0000005119 | 1563Mak0813612248 | 200 | yes | EI2 30
SMT | H1 Ebene 0 | 2.46 | 1.01 | E00 | 39 | no | OTS | 0 | E00-028-001-39 | - | KD | - | BGS | S68 | 1115Rau0000005119 | 1563Mak0813612244 | 200 | yes | EI2 30
SMT | H1 Ebene 0 | 2.46 | 1.01 | E00 | 39 | no | OTS | 0 | E00-028-001-39 | - | KD | - | BGS | S68 | 1115Rau0000005119 | 1563Mak0813612241 | 200 | yes | EI2 30
SMT | H1 Ebene 0 | 2.46 | 0.885 | E00 | 39 | no | OTS | 0 | E00-028-001-39 | - | KD | - | BGS | S68 | 1115Rau0000005119 | 1563Mak0813612221 | 200 | yes | EI2 30
SMT | H1 Ebene 0 | 2.46 | 0.885 | E00 | 39 | no | OTS | 0 | E00-028-001-39 | - | KD | - | BGS | S68 | 1115Rau0000005119 | 1563Mak0813612217 | 200 | yes | EI2 30
SMT | H1 Ebene 0 | 2.46 | 1.135 | E00 | 39 | no | OTS | 0 | E00-028-001-39 | - | KD | - | BGS | S68 | 1115Rau0000005119 | 1563Mak0813612202 | 200 | yes | EI2 30
SMT | H1 Ebene 0 | 2.46 | 1.135 | E00 | 39 | no | OTS | 0 | E00-028-001-39 | - | KD | - | BGS | S68 | 1115Rau0000005119 | 1563Mak0813612206 | 200 | yes | EI2 30
SMT | H1 Ebene 0 | 2.46 | 1.135 | E00 | 39 | no | OTS | 0 | E00-028-001-39 | - | KD | - | BGS | S68 | 1115Rau0000005119 | 1563Mak0813612209 | 200 | yes | EI2 30
SMT | H1 Ebene 0 | 2.46 | 1.135 | E00 | 39 | no | OTS | 0 | E00-028-001-39 | - | KD | - | BGS | S68 | 1115Rau0000005119 | 1563Mak0813612213 | 200 | yes | EI2 30
SMT | H1 Ebene 0 | 2.46 | 0.885 | E00 | 39 | no | OTS | 0 | E00-028-001-39 | - | KD | - | BGS | S68 | 1115Rau0000005119 | 1563Mak0813612238 | 200 | yes | EI2 30
SMT | H1 Ebene 0 | 2.46 | 1.01 | E00 | 39 | no | OTS | 0 | E00-028-001-39 | - | KD | - | BGS | S68 | 1115Rau0000005119 | 1563Mak0813612235 | 200 | yes | EI2 30
SMT | H1 Ebene 0 | 2.46 | 1.01 | E00 | 39 | no | OTS | 0 | E00-028-001-39 | - | KD | - | BGS | S68 | 1115Rau0000005119 | 1563Mak0813612232 | 200 | yes | EI2 30
SMT | H1 Ebene 0 | 2.46 | 1 | E00 | 39 | no | OTS | 0 | E00-028-001-39 | - | KD | - | BGS | S68 | 1115Rau0000005119 | 1563Mak0813612260 | 200 | yes | EI2 30
SMT | H1 Ebene 0 | 2.46 | 1.01 | E00 | 39 | no | OTS | 0 | E00-028-001-39 | - | KD | - | BGS | S68 | 1115Rau0000005119 | 1563Mak0813612256 | 200 | yes | EI2 30

# IfcElementAssembly (4)
Name | In
Fachwerkträger | H1 Ebene +1 | AllplanAttributes - Allright_Bauteil_ID: 1613Elg2005708133; Abrechnungsart: St; Objektname: Elementgruppe
2 x Innenwand 1-Schalig | H1 Ebene 0
 | H1 Ebene 0 | AllplanAttributes - Allright_Bauteil_ID: 1563Elg0813612177; Abrechnungsart: St; Objektname: Elementgruppe

# IfcFooting (17)
In: H1 Gründung
PredefinedType: STRIP_FOOTING; Material: STB
AllplanAttributes - 2D Interaktion: yes; Codetext: Codetext; Gewerk: Betonarbeiten; Objektname: Fundament; Bezeichnung: Streifenfundament; Material: STB; Außenliegend: yes; Abrechnungsart: m
Pset_FootingCommon - Status: NEW; LoadBearing: yes; Reference: Codetext
Name | Allright_Bauteil_ID
Streifenfundament | 1511SFu0000003841
Streifenfundament | 1511SFu0000003839
Streifenfundament | 1511SFu0000003899
Streifenfundament | 1511SFu0000003888
Streifenfundament | 1511SFu0000003886
Streifenfundament | 1511SFu0000003884
Streifenfundament | 1511SFu0000003882
Streifenfundament | 1511SFu0000003880
Streifenfundament | 1511SFu0000003872
Streifenfundament | 1511SFu0000003865
Streifenfundament | 1511SFu0000003863
Streifenfundament | 1511SFu0000003837
Streifenfundament | 1511SFu0000003835
Streifenfundament | 1511SFu0000003813
Streifenfundament | 1511SFu0000003811
Streifenfundament | 1511SFu0000003809
Streifenfundament | 1511SFu0000003791

# IfcOpeningElement: Opening (238)
Pset_OpeningElementCommon - Status: NEW
Name | In | Allright_Bauteil_ID | Abrechnungsart | Gewerk | Objektname | OKFF | Versatz_oben = Versatz_unten
7 x Fensteröffnung | H1 Ebene +1 | AllplanAttributes - Object Layer Attributes #1, Gewerk: Wärmedämm-Verbundsysteme; Object Layer Attributes #1, Objektname: Wand; Object Layer Attributes #1, Material: Fensterelement; Object Layer Attributes #1, Tragendes Bauteil: no; Object Layer Attributes #1, OKFF: -4.5; Object Layer Attributes #1, Allright_Bauteil_ID: 1605Fen0000069415; Object Layer Attributes #1, Abrechnungsart: m²; Object Layer Attributes #2, Status: Neubau; Object Layer Attributes #2, Versatz_oben: 0; Object Layer Attributes #2, Gewerk: Wärmedämm-Verbundsysteme; Object Layer Attributes #2, Material: Fensterelement; Object Layer Attributes #2, Außenliegend: yes; Object Layer Attributes #2, Feuerwiderstandsklasse: 0; Object Layer Attributes #2, U-Wert: 0.9; Object Layer Attributes #2, Versatz_unten: 0; Object Layer Attributes #2, Schallschutzklasse: -; Object Layer Attributes #2, Sicherheitsklasse: -; Object Layer Attributes #2, OKFF: 7.5; Object Layer Attributes #2, Sonnenschutztyp: Movable; Object Layer Attributes #2, g-Wert: 0,51; Object Layer Attributes #2, Allright_Bauteil_ID: 1605Fen0000069414; Object Layer Attributes #2, Abrechnungsart: m³; Object Layer Attributes #2, Objektname: Fensteröffnung; Object Layer Attributes #3, Status: Neubau; Object Layer Attributes #3, Versatz_oben: 0; Object Layer Attributes #3, Gewerk: Wärmedämm-Verbundsysteme; Object Layer Attributes #3, Feuerwiderstandsklasse: 0; Object Layer Attributes #3, U-Wert: 0.9; Object Layer Attributes #3, Versatz_unten: 0; Object Layer Attributes #3, Schallschutzklasse: -; Object Layer Attributes #3, Sicherheitsklasse: -; Object Layer Attributes #3, OKFF: 7.5; Object Layer Attributes #3, Sonnenschutztyp: Movable; Object Layer Attributes #3, g-Wert: 0,51; Object Layer Attributes #3, Allright_Bauteil_ID: 1605Fen0000069413; Object Layer Attributes #3, Abrechnungsart: m³; Object Layer Attributes #3, Objektname: Fensteröffnung; Object Layer Attributes #4, Status: Neubau; Object Layer Attributes #4, Versatz_oben: 0; Object Layer Attributes #4, Gewerk: Wärmedämm-Verbundsysteme; Object Layer Attributes #4, Feuerwiderstandsklasse: 0; Object Layer Attributes #4, U-Wert: 0.9; Object Layer Attributes #4, Versatz_unten: 0; Object Layer Attributes #4, Schallschutzklasse: -; Object Layer Attributes #4, Sicherheitsklasse: -; Object Layer Attributes #4, OKFF: 7.5; Object Layer Attributes #4, Sonnenschutztyp: Movable; Object Layer Attributes #4, g-Wert: 0,51; Object Layer Attributes #4, Allright_Bauteil_ID: 1605Fen0000069412; Object Layer Attributes #4, Abrechnungsart: m²; Object Layer Attributes #4, Objektname: Fensteröffnung; Object Layer Attributes #5, Status: Neubau; Object Layer Attributes #5, Versatz_oben: 0; Object Layer Attributes #5, Gewerk: Wärmedämm-Verbundsysteme; Object Layer Attributes #5, Feuerwiderstandsklasse: 0; Object Layer Attributes #5, U-Wert: 0.9; Object Layer Attributes #5, Versatz_unten: 0; Object Layer Attributes #5, Schallschutzklasse: -; Object Layer Attributes #5, Sicherheitsklasse: -; Object Layer Attributes #5, OKFF: 7.5; Object Layer Attributes #5, Sonnenschutztyp: Movable; Object Layer Attributes #5, g-Wert: 0,51; Object Layer Attributes #5, Allright_Bauteil_ID: 1605Fen0000069411; Object Layer Attributes #5, Abrechnungsart: m²; Object Layer Attributes #5, Objektname: Fensteröffnung; Object Layer Attributes #6, Status: Neubau; Object Layer Attributes #6, Versatz_oben: 0; Object Layer Attributes #6, Gewerk: Wärmedämm-Verbundsysteme; Object Layer Attributes #6, Feuerwiderstandsklasse: 0; Object Layer Attributes #6, U-Wert: 0.9; Object Layer Attributes #6, Versatz_unten: 0; Object Layer Attributes #6, Schallschutzklasse: -; Object Layer Attributes #6, Sicherheitsklasse: -; Object Layer Attributes #6, OKFF: 7.5; Object Layer Attributes #6, Sonnenschutztyp: Movable; Object Layer Attributes #6, g-Wert: 0,51; Object Layer Attributes #6, Allright_Bauteil_ID: 1605Fen0000069410; Object Layer Attributes #6, Abrechnungsart: m²; Object Layer Attributes #6, Objektname: Fensteröffnung; Object Layer Attributes #7, Status: Neubau; Object Layer Attributes #7, Versatz_oben: 0; Object Layer Attributes #7, Gewerk: Wärmedämm-Verbundsysteme; Object Layer Attributes #7, Feuerwiderstandsklasse: 0; Object Layer Attributes #7, U-Wert: 0.9; Object Layer Attributes #7, Versatz_unten: 0; Object Layer Attributes #7, Schallschutzklasse: -; Object Layer Attributes #7, Sicherheitsklasse: -; Object Layer Attributes #7, OKFF: 7.5; Object Layer Attributes #7, Sonnenschutztyp: Movable; Object Layer Attributes #7, g-Wert: 0,51; Object Layer Attributes #7, Allright_Bauteil_ID: 1605Fen0000069409; Object Layer Attributes #7, Abrechnungsart: m²; Object Layer Attributes #7, Objektname: Fensteröffnung
7 x Fensteröffnung | H1 Ebene +1 | AllplanAttributes - Object Layer Attributes #1, Gewerk: Wärmedämm-Verbundsysteme; Object Layer Attributes #1, Objektname: Wand; Object Layer Attributes #1, Material: Fensterelement; Object Layer Attributes #1, Tragendes Bauteil: no; Object Layer Attributes #1, OKFF: -4.5; Object Layer Attributes #1, Allright_Bauteil_ID: 1605Fen0000069893; Object Layer Attributes #1, Abrechnungsart: m²; Object Layer Attributes #2, Status: Neubau; Object Layer Attributes #2, Versatz_oben: 0; Object Layer Attributes #2, Gewerk: Wärmedämm-Verbundsysteme; Object Layer Attributes #2, Material: Fensterelement; Object Layer Attributes #2, Außenliegend: yes; Object Layer Attributes #2, Feuerwiderstandsklasse: 0; Object Layer Attributes #2, U-Wert: 0.9; Object Layer Attributes #2, Versatz_unten: 0; Object Layer Attributes #2, Schallschutzklasse: -; Object Layer Attributes #2, Sicherheitsklasse: -; Object Layer Attributes #2, OKFF: 7.5; Object Layer Attributes #2, Sonnenschutztyp: Movable; Object Layer Attributes #2, g-Wert: 0,51; Object Layer Attributes #2, Allright_Bauteil_ID: 1605Fen0000069892; Object Layer Attributes #2, Abrechnungsart: m³; Object Layer Attributes #2, Objektname: Fensteröffnung; Object Layer Attributes #3, Status: Neubau; Object Layer Attributes #3, Versatz_oben: 0; Object Layer Attributes #3, Gewerk: Wärmedämm-Verbundsysteme; Object Layer Attributes #3, Feuerwiderstandsklasse: 0; Object Layer Attributes #3, U-Wert: 0.9; Object Layer Attributes #3, Versatz_unten: 0; Object Layer Attributes #3, Schallschutzklasse: -; Object Layer Attributes #3, Sicherheitsklasse: -; Object Layer Attributes #3, OKFF: 7.5; Object Layer Attributes #3, Sonnenschutztyp: Movable; Object Layer Attributes #3, g-Wert: 0,51; Object Layer Attributes #3, Allright_Bauteil_ID: 1605Fen0000069891; Object Layer Attributes #3, Abrechnungsart: m³; Object Layer Attributes #3, Objektname: Fensteröffnung; Object Layer Attributes #4, Status: Neubau; Object Layer Attributes #4, Versatz_oben: 0; Object Layer Attributes #4, Gewerk: Wärmedämm-Verbundsysteme; Object Layer Attributes #4, Feuerwiderstandsklasse: 0; Object Layer Attributes #4, U-Wert: 0.9; Object Layer Attributes #4, Versatz_unten: 0; Object Layer Attributes #4, Schallschutzklasse: -; Object Layer Attributes #4, Sicherheitsklasse: -; Object Layer Attributes #4, OKFF: 7.5; Object Layer Attributes #4, Sonnenschutztyp: Movable; Object Layer Attributes #4, g-Wert: 0,51; Object Layer Attributes #4, Allright_Bauteil_ID: 1605Fen0000069890; Object Layer Attributes #4, Abrechnungsart: m²; Object Layer Attributes #4, Objektname: Fensteröffnung; Object Layer Attributes #5, Status: Neubau; Object Layer Attributes #5, Versatz_oben: 0; Object Layer Attributes #5, Gewerk: Wärmedämm-Verbundsysteme; Object Layer Attributes #5, Feuerwiderstandsklasse: 0; Object Layer Attributes #5, U-Wert: 0.9; Object Layer Attributes #5, Versatz_unten: 0; Object Layer Attributes #5, Schallschutzklasse: -; Object Layer Attributes #5, Sicherheitsklasse: -; Object Layer Attributes #5, OKFF: 7.5; Object Layer Attributes #5, Sonnenschutztyp: Movable; Object Layer Attributes #5, g-Wert: 0,51; Object Layer Attributes #5, Allright_Bauteil_ID: 1605Fen0000069889; Object Layer Attributes #5, Abrechnungsart: m²; Object Layer Attributes #5, Objektname: Fensteröffnung; Object Layer Attributes #6, Status: Neubau; Object Layer Attributes #6, Versatz_oben: 0; Object Layer Attributes #6, Gewerk: Wärmedämm-Verbundsysteme; Object Layer Attributes #6, Feuerwiderstandsklasse: 0; Object Layer Attributes #6, U-Wert: 0.9; Object Layer Attributes #6, Versatz_unten: 0; Object Layer Attributes #6, Schallschutzklasse: -; Object Layer Attributes #6, Sicherheitsklasse: -; Object Layer Attributes #6, OKFF: 7.5; Object Layer Attributes #6, Sonnenschutztyp: Movable; Object Layer Attributes #6, g-Wert: 0,51; Object Layer Attributes #6, Allright_Bauteil_ID: 1605Fen0000069888; Object Layer Attributes #6, Abrechnungsart: m²; Object Layer Attributes #6, Objektname: Fensteröffnung; Object Layer Attributes #7, Status: Neubau; Object Layer Attributes #7, Versatz_oben: 0; Object Layer Attributes #7, Gewerk: Wärmedämm-Verbundsysteme; Object Layer Attributes #7, Feuerwiderstandsklasse: 0; Object Layer Attributes #7, U-Wert: 0.9; Object Layer Attributes #7, Versatz_unten: 0; Object Layer Attributes #7, Schallschutzklasse: -; Object Layer Attributes #7, Sicherheitsklasse: -; Object Layer Attributes #7, OKFF: 7.5; Object Layer Attributes #7, Sonnenschutztyp: Movable; Object Layer Attributes #7, g-Wert: 0,51; Object Layer Attributes #7, Allright_Bauteil_ID: 1605Fen0000069887; Object Layer Attributes #7, Abrechnungsart: m²; Object Layer Attributes #7, Objektname: Fensteröffnung
7 x Fensteröffnung | H1 Ebene +1 | AllplanAttributes - Object Layer Attributes #1, Gewerk: Wärmedämm-Verbundsysteme; Object Layer Attributes #1, Objektname: Wand; Object Layer Attributes #1, Material: Fensterelement; Object Layer Attributes #1, Tragendes Bauteil: no; Object Layer Attributes #1, OKFF: -4.5; Object Layer Attributes #1, Allright_Bauteil_ID: 1605Fen0000070814; Object Layer Attributes #1, Abrechnungsart: m²; Object Layer Attributes #2, Status: Neubau; Object Layer Attributes #2, Versatz_oben: 0; Object Layer Attributes #2, Gewerk: Wärmedämm-Verbundsysteme; Object Layer Attributes #2, Material: Fensterelement; Object Layer Attributes #2, Außenliegend: yes; Object Layer Attributes #2, Feuerwiderstandsklasse: 0; Object Layer Attributes #2, U-Wert: 0.9; Object Layer Attributes #2, Versatz_unten: 0; Object Layer Attributes #2, Schallschutzklasse: -; Object Layer Attributes #2, Sicherheitsklasse: -; Object Layer Attributes #2, OKFF: 7.5; Object Layer Attributes #2, Sonnenschutztyp: Movable; Object Layer Attributes #2, g-Wert: 0,51; Object Layer Attributes #2, Allright_Bauteil_ID: 1605Fen0000070815; Object Layer Attributes #2, Abrechnungsart: m³; Object Layer Attributes #2, Objektname: Fensteröffnung; Object Layer Attributes #3, Status: Neubau; Object Layer Attributes #3, Versatz_oben: 0; Object Layer Attributes #3, Gewerk: Wärmedämm-Verbundsysteme; Object Layer Attributes #3, Feuerwiderstandsklasse: 0; Object Layer Attributes #3, U-Wert: 0.9; Object Layer Attributes #3, Versatz_unten: 0; Object Layer Attributes #3, Schallschutzklasse: -; Object Layer Attributes #3, Sicherheitsklasse: -; Object Layer Attributes #3, OKFF: 7.5; Object Layer Attributes #3, Sonnenschutztyp: Movable; Object Layer Attributes #3, g-Wert: 0,51; Object Layer Attributes #3, Allright_Bauteil_ID: 1605Fen0000070816; Object Layer Attributes #3, Abrechnungsart: m³; Object Layer Attributes #3, Objektname: Fensteröffnung; Object Layer Attributes #4, Status: Neubau; Object Layer Attributes #4, Versatz_oben: 0; Object Layer Attributes #4, Gewerk: Wärmedämm-Verbundsysteme; Object Layer Attributes #4, Feuerwiderstandsklasse: 0; Object Layer Attributes #4, U-Wert: 0.9; Object Layer Attributes #4, Versatz_unten: 0; Object Layer Attributes #4, Schallschutzklasse: -; Object Layer Attributes #4, Sicherheitsklasse: -; Object Layer Attributes #4, OKFF: 7.5; Object Layer Attributes #4, Sonnenschutztyp: Movable; Object Layer Attributes #4, g-Wert: 0,51; Object Layer Attributes #4, Allright_Bauteil_ID: 1605Fen0000070817; Object Layer Attributes #4, Abrechnungsart: m²; Object Layer Attributes #4, Objektname: Fensteröffnung; Object Layer Attributes #5, Status: Neubau; Object Layer Attributes #5, Versatz_oben: 0; Object Layer Attributes #5, Gewerk: Wärmedämm-Verbundsysteme; Object Layer Attributes #5, Feuerwiderstandsklasse: 0; Object Layer Attributes #5, U-Wert: 0.9; Object Layer Attributes #5, Versatz_unten: 0; Object Layer Attributes #5, Schallschutzklasse: -; Object Layer Attributes #5, Sicherheitsklasse: -; Object Layer Attributes #5, OKFF: 7.5; Object Layer Attributes #5, Sonnenschutztyp: Movable; Object Layer Attributes #5, g-Wert: 0,51; Object Layer Attributes #5, Allright_Bauteil_ID: 1605Fen0000070818; Object Layer Attributes #5, Abrechnungsart: m²; Object Layer Attributes #5, Objektname: Fensteröffnung; Object Layer Attributes #6, Status: Neubau; Object Layer Attributes #6, Versatz_oben: 0; Object Layer Attributes #6, Gewerk: Wärmedämm-Verbundsysteme; Object Layer Attributes #6, Feuerwiderstandsklasse: 0; Object Layer Attributes #6, U-Wert: 0.9; Object Layer Attributes #6, Versatz_unten: 0; Object Layer Attributes #6, Schallschutzklasse: -; Object Layer Attributes #6, Sicherheitsklasse: -; Object Layer Attributes #6, OKFF: 7.5; Object Layer Attributes #6, Sonnenschutztyp: Movable; Object Layer Attributes #6, g-Wert: 0,51; Object Layer Attributes #6, Allright_Bauteil_ID: 1605Fen0000070819; Object Layer Attributes #6, Abrechnungsart: m²; Object Layer Attributes #6, Objektname: Fensteröffnung; Object Layer Attributes #7, Status: Neubau; Object Layer Attributes #7, Versatz_oben: 0; Object Layer Attributes #7, Gewerk: Wärmedämm-Verbundsysteme; Object Layer Attributes #7, Feuerwiderstandsklasse: 0; Object Layer Attributes #7, U-Wert: 0.9; Object Layer Attributes #7, Versatz_unten: 0; Object Layer Attributes #7, Schallschutzklasse: -; Object Layer Attributes #7, Sicherheitsklasse: -; Object Layer Attributes #7, OKFF: 7.5; Object Layer Attributes #7, Sonnenschutztyp: Movable; Object Layer Attributes #7, g-Wert: 0,51; Object Layer Attributes #7, Allright_Bauteil_ID: 1605Fen0000070820; Object Layer Attributes #7, Abrechnungsart: m²; Object Layer Attributes #7, Objektname: Fensteröffnung
7 x Fensteröffnung | H1 Ebene +1 | AllplanAttributes - Object Layer Attributes #1, Gewerk: Trockenbauarbeiten; Object Layer Attributes #1, Objektname: Fensteröffnung; Object Layer Attributes #1, Allright_Bauteil_ID: 1605Fen0000070870; Object Layer Attributes #1, Abrechnungsart: m²; Object Layer Attributes #2, Status: Neubau; Object Layer Attributes #2, Versatz_oben: 0; Object Layer Attributes #2, Gewerk: Trockenbauarbeiten; Object Layer Attributes #2, Versatz_unten: 0; Object Layer Attributes #2, Allright_Bauteil_ID: 1605Fen0000070869; Object Layer Attributes #2, Abrechnungsart: m³; Object Layer Attributes #2, Objektname: Fensteröffnung; Object Layer Attributes #3, Status: Neubau; Object Layer Attributes #3, Versatz_oben: 0; Object Layer Attributes #3, Gewerk: Trockenbauarbeiten; Object Layer Attributes #3, Versatz_unten: 0; Object Layer Attributes #3, Allright_Bauteil_ID: 1605Fen0000070868; Object Layer Attributes #3, Abrechnungsart: m³; Object Layer Attributes #3, Objektname: Fensteröffnung; Object Layer Attributes #4, Status: Neubau; Object Layer Attributes #4, Versatz_oben: 0; Object Layer Attributes #4, Gewerk: Trockenbauarbeiten; Object Layer Attributes #4, Versatz_unten: 0; Object Layer Attributes #4, Allright_Bauteil_ID: 1605Fen0000070867; Object Layer Attributes #4, Abrechnungsart: m²; Object Layer Attributes #4, Objektname: Fensteröffnung; Object Layer Attributes #5, Status: Neubau; Object Layer Attributes #5, Versatz_oben: 0; Object Layer Attributes #5, Gewerk: Trockenbauarbeiten; Object Layer Attributes #5, Versatz_unten: 0; Object Layer Attributes #5, Allright_Bauteil_ID: 1605Fen0000070866; Object Layer Attributes #5, Abrechnungsart: m²; Object Layer Attributes #5, Objektname: Fensteröffnung; Object Layer Attributes #6, Status: Neubau; Object Layer Attributes #6, Versatz_oben: 0; Object Layer Attributes #6, Gewerk: Trockenbauarbeiten; Object Layer Attributes #6, Versatz_unten: 0; Object Layer Attributes #6, Allright_Bauteil_ID: 1605Fen0000070865; Object Layer Attributes #6, Abrechnungsart: m²; Object Layer Attributes #6, Objektname: Fensteröffnung; Object Layer Attributes #7, Status: Neubau; Object Layer Attributes #7, Versatz_oben: 0; Object Layer Attributes #7, Gewerk: Trockenbauarbeiten; Object Layer Attributes #7, Versatz_unten: 0; Object Layer Attributes #7, Allright_Bauteil_ID: 1605Fen0000071236; Object Layer Attributes #7, Abrechnungsart: m²; Object Layer Attributes #7, Objektname: Fensteröffnung
7 x Fensteröffnung | H1 Ebene +1 | AllplanAttributes - Object Layer Attributes #1, Gewerk: Wärmedämm-Verbundsysteme; Object Layer Attributes #1, Objektname: Wand; Object Layer Attributes #1, Material: Fensterelement; Object Layer Attributes #1, Tragendes Bauteil: no; Object Layer Attributes #1, OKFF: -4.5; Object Layer Attributes #1, Allright_Bauteil_ID: 1605Fen0000070585; Object Layer Attributes #1, Abrechnungsart: m²; Object Layer Attributes #2, Status: Neubau; Object Layer Attributes #2, Versatz_oben: 0; Object Layer Attributes #2, Gewerk: Wärmedämm-Verbundsysteme; Object Layer Attributes #2, Material: Fensterelement; Object Layer Attributes #2, Außenliegend: yes; Object Layer Attributes #2, Feuerwiderstandsklasse: 0; Object Layer Attributes #2, U-Wert: 0.9; Object Layer Attributes #2, Versatz_unten: 0; Object Layer Attributes #2, Schallschutzklasse: -; Object Layer Attributes #2, Sicherheitsklasse: -; Object Layer Attributes #2, OKFF: 7.5; Object Layer Attributes #2, Sonnenschutztyp: Movable; Object Layer Attributes #2, g-Wert: 0,51; Object Layer Attributes #2, Allright_Bauteil_ID: 1605Fen0000070584; Object Layer Attributes #2, Abrechnungsart: m³; Object Layer Attributes #2, Objektname: Fensteröffnung; Object Layer Attributes #3, Status: Neubau; Object Layer Attributes #3, Versatz_oben: 0; Object Layer Attributes #3, Gewerk: Wärmedämm-Verbundsysteme; Object Layer Attributes #3, Feuerwiderstandsklasse: 0; Object Layer Attributes #3, U-Wert: 0.9; Object Layer Attributes #3, Versatz_unten: 0; Object Layer Attributes #3, Schallschutzklasse: -; Object Layer Attributes #3, Sicherheitsklasse: -; Object Layer Attributes #3, OKFF: 7.5; Object Layer Attributes #3, Sonnenschutztyp: Movable; Object Layer Attributes #3, g-Wert: 0,51; Object Layer Attributes #3, Allright_Bauteil_ID: 1605Fen0000070583; Object Layer Attributes #3, Abrechnungsart: m³; Object Layer Attributes #3, Objektname: Fensteröffnung; Object Layer Attributes #4, Status: Neubau; Object Layer Attributes #4, Versatz_oben: 0; Object Layer Attributes #4, Gewerk: Wärmedämm-Verbundsysteme; Object Layer Attributes #4, Feuerwiderstandsklasse: 0; Object Layer Attributes #4, U-Wert: 0.9; Object Layer Attributes #4, Versatz_unten: 0; Object Layer Attributes #4, Schallschutzklasse: -; Object Layer Attributes #4, Sicherheitsklasse: -; Object Layer Attributes #4, OKFF: 7.5; Object Layer Attributes #4, Sonnenschutztyp: Movable; Object Layer Attributes #4, g-Wert: 0,51; Object Layer Attributes #4, Allright_Bauteil_ID: 1605Fen0000070582; Object Layer Attributes #4, Abrechnungsart: m²; Object Layer Attributes #4, Objektname: Fensteröffnung; Object Layer Attributes #5, Status: Neubau; Object Layer Attributes #5, Versatz_oben: 0; Object Layer Attributes #5, Gewerk: Wärmedämm-Verbundsysteme; Object Layer Attributes #5, Feuerwiderstandsklasse: 0; Object Layer Attributes #5, U-Wert: 0.9; Object Layer Attributes #5, Versatz_unten: 0; Object Layer Attributes #5, Schallschutzklasse: -; Object Layer Attributes #5, Sicherheitsklasse: -; Object Layer Attributes #5, OKFF: 7.5; Object Layer Attributes #5, Sonnenschutztyp: Movable; Object Layer Attributes #5, g-Wert: 0,51; Object Layer Attributes #5, Allright_Bauteil_ID: 1605Fen0000070581; Object Layer Attributes #5, Abrechnungsart: m²; Object Layer Attributes #5, Objektname: Fensteröffnung; Object Layer Attributes #6, Status: Neubau; Object Layer Attributes #6, Versatz_oben: 0; Object Layer Attributes #6, Gewerk: Wärmedämm-Verbundsysteme; Object Layer Attributes #6, Feuerwiderstandsklasse: 0; Object Layer Attributes #6, U-Wert: 0.9; Object Layer Attributes #6, Versatz_unten: 0; Object Layer Attributes #6, Schallschutzklasse: -; Object Layer Attributes #6, Sicherheitsklasse: -; Object Layer Attributes #6, OKFF: 7.5; Object Layer Attributes #6, Sonnenschutztyp: Movable; Object Layer Attributes #6, g-Wert: 0,51; Object Layer Attributes #6, Allright_Bauteil_ID: 1605Fen0000070580; Object Layer Attributes #6, Abrechnungsart: m²; Object Layer Attributes #6, Objektname: Fensteröffnung; Object Layer Attributes #7, Status: Neubau; Object Layer Attributes #7, Versatz_oben: 0; Object Layer Attributes #7, Gewerk: Wärmedämm-Verbundsysteme; Object Layer Attributes #7, Feuerwiderstandsklasse: 0; Object Layer Attributes #7, U-Wert: 0.9; Object Layer Attributes #7, Versatz_unten: 0; Object Layer Attributes #7, Schallschutzklasse: -; Object Layer Attributes #7, Sicherheitsklasse: -; Object Layer Attributes #7, OKFF: 7.5; Object Layer Attributes #7, Sonnenschutztyp: Movable; Object Layer Attributes #7, g-Wert: 0,51; Object Layer Attributes #7, Allright_Bauteil_ID: 1605Fen0000070579; Object Layer Attributes #7, Abrechnungsart: m²; Object Layer Attributes #7, Objektname: Fensteröffnung
14 x Fensteröffnung | H1 Ebene +1 | AllplanAttributes - Object Layer Attributes #1, Gewerk: Trockenbauarbeiten; Object Layer Attributes #1, Objektname: Fensteröffnung; Object Layer Attributes #1, Allright_Bauteil_ID: 1605Fen0000070925; Object Layer Attributes #1, Abrechnungsart: m²; Object Layer Attributes #2, Status: Neubau; Object Layer Attributes #2, Versatz_oben: 0; Object Layer Attributes #2, Gewerk: Zimmer- und Holzbauarbeiten; Object Layer Attributes #2, Versatz_unten: 0; Object Layer Attributes #2, Allright_Bauteil_ID: 1605Fen0000070924; Object Layer Attributes #2, Abrechnungsart: m³; Object Layer Attributes #2, Objektname: Fensteröffnung; Object Layer Attributes #3, Status: Neubau; Object Layer Attributes #3, Versatz_oben: 0; Object Layer Attributes #3, Gewerk: Zimmer- und Holzbauarbeiten; Object Layer Attributes #3, Versatz_unten: 0; Object Layer Attributes #3, Allright_Bauteil_ID: 1605Fen0000070923; Object Layer Attributes #3, Abrechnungsart: m³; Object Layer Attributes #3, Objektname: Fensteröffnung; Object Layer Attributes #4, Status: Neubau; Object Layer Attributes #4, Versatz_oben: 0; Object Layer Attributes #4, Gewerk: Trockenbauarbeiten; Object Layer Attributes #4, Versatz_unten: 0; Object Layer Attributes #4, Allright_Bauteil_ID: 1605Fen0000070922; Object Layer Attributes #4, Abrechnungsart: m²; Object Layer Attributes #4, Objektname: Fensteröffnung; Object Layer Attributes #5, Status: Neubau; Object Layer Attributes #5, Versatz_oben: 0; Object Layer Attributes #5, Gewerk: Zimmer- und Holzbauarbeiten; Object Layer Attributes #5, Versatz_unten: 0; Object Layer Attributes #5, Allright_Bauteil_ID: 1605Fen0000070921; Object Layer Attributes #5, Abrechnungsart: m²; Object Layer Attributes #5, Objektname: Fensteröffnung; Object Layer Attributes #6, Status: Neubau; Object Layer Attributes #6, Versatz_oben: 0; Object Layer Attributes #6, Gewerk: Zimmer- und Holzbauarbeiten; Object Layer Attributes #6, Versatz_unten: 0; Object Layer Attributes #6, Allright_Bauteil_ID: 1605Fen0000070920; Object Layer Attributes #6, Abrechnungsart: m²; Object Layer Attributes #6, Objektname: Fensteröffnung; Object Layer Attributes #7, Status: Neubau; Object Layer Attributes #7, Versatz_oben: 0; Object Layer Attributes #7, Gewerk: Zimmer- und Holzbauarbeiten; Object Layer Attributes #7, Versatz_unten: 0; Object Layer Attributes #7, Allright_Bauteil_ID: 1605Fen0000070919; Object Layer Attributes #7, Abrechnungsart: m²; Object Layer Attributes #7, Objektname: Fensteröffnung
Türöffnung | H1 Ebene +1 | 1613Tür2005708157 | m² | Trockenbauarbeiten | Türöffnung | 3.75 | AllplanAttributes - Codetext: Codetext; Türanschlag: DIN R; Positionsnummer_Text: U100; Attributset-Objekt: OpeningElement; P_ID: 1163Wa 0812444047; Pset_OpeningElementCommon - FireExit: no; Reference: Codetext
Türöffnung | H1 Ebene +1 | 1613Tür2005707905 | m² | Trockenbauarbeiten | Türöffnung | 0 | AllplanAttributes - Codetext: Codetext; Türanschlag: DIN L; Positionsnummer_Text: S68; Attributset-Objekt: OpeningElement; P_ID: 1113Wa 0812742684; Feuerwiderstandsklasse: EI2 30; Rauchschutz: yes; Selbstschließend: yes; ash T_Zulage Schachttür: no; ash T_Dichtschließend: no; ash T_Feststellanlage (FSA): -; ash T_nicht abschließbar: no; W_Deckenanschluss: Gleitender Deckenanschluss Fall 01; Pset_OpeningElementCommon - FireExit: no; Reference: Codetext
Türöffnung | H1 Ebene +1 | 1613Tür2005707909 | m² | Trockenbauarbeiten | Türöffnung | 0 | AllplanAttributes - Codetext: Codetext; Türanschlag: DIN L; Positionsnummer_Text: S68; Attributset-Objekt: OpeningElement; P_ID: 1113Wa 0812742684; Feuerwiderstandsklasse: EI2 30; Rauchschutz: yes; Selbstschließend: yes; ash T_Zulage Schachttür: no; ash T_Dichtschließend: no; ash T_Feststellanlage (FSA): -; ash T_nicht abschließbar: no; W_Deckenanschluss: Gleitender Deckenanschluss Fall 01; Pset_OpeningElementCommon - FireExit: no; Reference: Codetext
Türöffnung | H1 Ebene +1 | 1613Tür2005707912 | m² | Trockenbauarbeiten | Türöffnung | 0 | AllplanAttributes - Codetext: Codetext; Türanschlag: DIN L; Positionsnummer_Text: S68; Attributset-Objekt: OpeningElement; P_ID: 1113Wa 0812742684; Feuerwiderstandsklasse: EI2 30; Rauchschutz: yes; Selbstschließend: yes; ash T_Zulage Schachttür: no; ash T_Dichtschließend: no; ash T_Feststellanlage (FSA): -; ash T_nicht abschließbar: no; W_Deckenanschluss: Gleitender Deckenanschluss Fall 01; Pset_OpeningElementCommon - FireExit: no; Reference: Codetext
Türöffnung | H1 Ebene +1 | 1613Tür2005708161 | m² | Trockenbauarbeiten | Türöffnung | 3.75 | AllplanAttributes - Codetext: Codetext; Türanschlag: DIN L; Positionsnummer_Text: U100; Attributset-Objekt: OpeningElement; P_ID: 1163Wa 0812444047; Pset_OpeningElementCommon - FireExit: no; Reference: Codetext
Türöffnung | H1 Ebene +1 | 1613Tür2005711600 | m² | Trockenbauarbeiten | Türöffnung | 3.75 | AllplanAttributes - Codetext: Codetext; Türanschlag: -; Positionsnummer_Text: U100; Attributset-Objekt: OpeningElement; P_ID: 1163Wa 0812444047; Pset_OpeningElementCommon - FireExit: no; Reference: Codetext
Türöffnung | H1 Ebene 0 | 1555Tür0811452284 | m² | Trockenbauarbeiten | Türöffnung | 0 | AllplanAttributes - Codetext: Codetext; Türanschlag: DIN R; Positionsnummer_Text: S68; Attributset-Objekt: OpeningElement; P_ID: 1113Wa 0812742684; Feuerwiderstandsklasse: EI2 30; Rauchschutz: yes; Selbstschließend: yes; ash T_Zulage Schachttür: no; ash T_Dichtschließend: no; ash T_Feststellanlage (FSA): -; ash T_nicht abschließbar: no; W_Deckenanschluss: Gleitender Deckenanschluss Fall 01; Pset_OpeningElementCommon - FireExit: no; Reference: Codetext
Türöffnung | H1 Ebene 0 | 1555Tür0811452283 | m³ | Trockenbauarbeiten | Türöffnung | 0 | 0 | AllplanAttributes - Türanschlag: DIN R; Positionsnummer_Text: U23; P_ID: 1105Wa 0000035817; Feuerwiderstandsklasse: 0; ash T_Feststellanlage (FSA): -; Sicherheitsklasse: RC 1; g-Wert: 0,51
Türöffnung | H1 Ebene 0 | 1555Tür0811452282 | m³ | Trockenbauarbeiten | Türöffnung | 0 | 0 | AllplanAttributes - Türanschlag: DIN R; Positionsnummer_Text: U23; P_ID: 1105Wa 0000035818; Feuerwiderstandsklasse: 0; ash T_Feststellanlage (FSA): -; Sicherheitsklasse: RC 1; g-Wert: 0,51
Türöffnung | H1 Ebene 0 | 1555Tür0811452281 | m² | Trockenbauarbeiten | Türöffnung | 0 | 0 | AllplanAttributes - Türanschlag: DIN R; Positionsnummer_Text: U23; P_ID: 1105Wa 0000035819; Feuerwiderstandsklasse: 0; ash T_Feststellanlage (FSA): -; Sicherheitsklasse: RC 1; g-Wert: 0,51
Türöffnung | H1 Ebene 0 | 1555Tür0811452280 | m² | Trockenbauarbeiten | Türöffnung | 0 | 0 | AllplanAttributes - Türanschlag: DIN R; Positionsnummer_Text: U23; P_ID: 1105Wa 0000035820; Feuerwiderstandsklasse: 0; ash T_Feststellanlage (FSA): -; Sicherheitsklasse: RC 1; g-Wert: 0,51
Türöffnung | H1 Ebene 0 | 1555Tür0811452279 | m² | Trockenbauarbeiten | Türöffnung |  | 0 | AllplanAttributes - Türanschlag: DIN R; Positionsnummer_Text: U23; P_ID: 1105Wa 0000159880; Feuerwiderstandsklasse: 0; Sicherheitsklasse: RC 1; g-Wert: 0,51
Türöffnung | H1 Ebene 0 | 1555Tür0811452278 | m² | Trockenbauarbeiten | Türöffnung |  | 0 | AllplanAttributes - Türanschlag: DIN R
Türöffnung | H1 Ebene 0 | 1555Tür0811452277 | m² | Zimmer- und Holzbauarbeiten | Türöffnung | 0 | AllplanAttributes - Türanschlag: DIN L; Positionsnummer_Text: U23; P_ID: 1105Wa 0000035816; Feuerwiderstandsklasse: 0; ash T_Feststellanlage (FSA): -; Sicherheitsklasse: RC 1; g-Wert: 0,51
Türöffnung | H1 Ebene 0 | 1555Tür0811452276 | m³ | Zimmer- und Holzbauarbeiten | Türöffnung | 0 | 0 | AllplanAttributes - Türanschlag: DIN L; Positionsnummer_Text: U23; P_ID: 1105Wa 0000035817; Feuerwiderstandsklasse: 0; ash T_Feststellanlage (FSA): -; Sicherheitsklasse: RC 1; g-Wert: 0,51
Türöffnung | H1 Ebene 0 | 1555Tür0811452275 | m³ | Zimmer- und Holzbauarbeiten | Türöffnung | 0 | 0 | AllplanAttributes - Türanschlag: DIN L; Positionsnummer_Text: U23; P_ID: 1105Wa 0000035818; Feuerwiderstandsklasse: 0; ash T_Feststellanlage (FSA): -; Sicherheitsklasse: RC 1; g-Wert: 0,51
Türöffnung | H1 Ebene 0 | 1555Tür0811452274 | m² | Zimmer- und Holzbauarbeiten | Türöffnung | 0 | 0 | AllplanAttributes - Türanschlag: DIN L; Positionsnummer_Text: U23; P_ID: 1105Wa 0000035819; Feuerwiderstandsklasse: 0; ash T_Feststellanlage (FSA): -; Sicherheitsklasse: RC 1; g-Wert: 0,51
Türöffnung | H1 Ebene 0 | 1555Tür0811452273 | m² | Zimmer- und Holzbauarbeiten | Türöffnung | 0 | 0 | AllplanAttributes - Türanschlag: DIN L; Positionsnummer_Text: U23; P_ID: 1105Wa 0000035820; Feuerwiderstandsklasse: 0; ash T_Feststellanlage (FSA): -; Sicherheitsklasse: RC 1; g-Wert: 0,51
Türöffnung | H1 Ebene 0 | 1555Tür0811452272 | m² | Zimmer- und Holzbauarbeiten | Türöffnung |  | 0 | AllplanAttributes - Türanschlag: DIN L; Positionsnummer_Text: U23; P_ID: 1105Wa 0000159880; Feuerwiderstandsklasse: 0; Sicherheitsklasse: RC 1; g-Wert: 0,51
Türöffnung | H1 Ebene 0 | 1555Tür0811452271 | m² | Zimmer- und Holzbauarbeiten | Türöffnung |  | 0 | AllplanAttributes - Türanschlag: DIN L
Fensteröffnung | H1 Ebene 0 | 1555Fen0811452326 | m² | Fensterarbeiten | Fensteröffnung | 3.75
Fensteröffnung | H1 Ebene 0 | 1555Fen0811452327 | m² | Fensterarbeiten | Fensteröffnung | 3.75
Fensteröffnung | H1 Ebene 0 | 1555Fen0811452334 | m² | Fensterarbeiten | Fensteröffnung | 3.75
Fensteröffnung | H1 Ebene 0 | 1555Fen0811452311 | m³ | Fensterarbeiten | Fensteröffnung | 7.5 | 0 | AllplanAttributes - Feuerwiderstandsklasse: 0; Sicherheitsklasse: -; g-Wert: 0,51; Material: Fensterelement; Außenliegend: yes; U-Wert: 0.9; Schallschutzklasse: -; Sonnenschutztyp: Movable
Fensteröffnung | H1 Ebene 0 | 1555Fen0811452310 | m³ | Fensterarbeiten | Fensteröffnung | 7.5 | 0 | AllplanAttributes - Feuerwiderstandsklasse: 0; Sicherheitsklasse: -; g-Wert: 0,51; Material: Fensterelement; Außenliegend: yes; U-Wert: 0.9; Schallschutzklasse: -; Sonnenschutztyp: Movable
Fensteröffnung | H1 Ebene 0 | 1555Fen0811452307 | m³ | Fensterarbeiten | Fensteröffnung | 7.5 | 0 | AllplanAttributes - Feuerwiderstandsklasse: 0; Sicherheitsklasse: -; g-Wert: 0,51; Material: Fensterelement; Außenliegend: yes; U-Wert: 0.9; Schallschutzklasse: -; Sonnenschutztyp: Movable
Fensteröffnung | H1 Ebene 0 | 1555Fen0811452315 | m³ | Fensterarbeiten | Fensteröffnung | 7.5 | 0 | AllplanAttributes - Feuerwiderstandsklasse: 0; Sicherheitsklasse: -; g-Wert: 0,51; U-Wert: 0.9; Schallschutzklasse: -; Sonnenschutztyp: Movable
Fensteröffnung | H1 Ebene 0 | 1555Fen0811452314 | m³ | Fensterarbeiten | Fensteröffnung | 7.5 | 0 | AllplanAttributes - Feuerwiderstandsklasse: 0; Sicherheitsklasse: -; g-Wert: 0,51; U-Wert: 0.9; Schallschutzklasse: -; Sonnenschutztyp: Movable
Fensteröffnung | H1 Ebene 0 | 1555Fen0811452313 | m³ | Fensterarbeiten | Fensteröffnung | 7.5 | 0 | AllplanAttributes - Feuerwiderstandsklasse: 0; Sicherheitsklasse: -; g-Wert: 0,51; U-Wert: 0.9; Schallschutzklasse: -; Sonnenschutztyp: Movable
Fensteröffnung | H1 Ebene 0 | 1555Fen0811452312 | m² | Fensterarbeiten | Fensteröffnung | 7.5 | 0 | AllplanAttributes - Feuerwiderstandsklasse: 0; Sicherheitsklasse: -; g-Wert: 0,51; U-Wert: 0.9; Schallschutzklasse: -; Sonnenschutztyp: Movable
Fensteröffnung | H1 Ebene 0 | 1555Fen0811452309 | m² | Fensterarbeiten | Fensteröffnung | 7.5 | 0 | AllplanAttributes - Feuerwiderstandsklasse: 0; Sicherheitsklasse: -; g-Wert: 0,51; U-Wert: 0.9; Schallschutzklasse: -; Sonnenschutztyp: Movable
Fensteröffnung | H1 Ebene 0 | 1555Fen0811452308 | m² | Fensterarbeiten | Fensteröffnung | 7.5 | 0 | AllplanAttributes - Feuerwiderstandsklasse: 0; Sicherheitsklasse: -; g-Wert: 0,51; U-Wert: 0.9; Schallschutzklasse: -; Sonnenschutztyp: Movable
Fensteröffnung | H1 Ebene 0 | 1555Fen0811452325 | m² | Fensterarbeiten | Fensteröffnung | 7.5 | 0 | AllplanAttributes - Feuerwiderstandsklasse: 0; Sicherheitsklasse: -; g-Wert: 0,51; U-Wert: 0.9; Schallschutzklasse: -; Sonnenschutztyp: Movable
Fensteröffnung | H1 Ebene 0 | 1555Fen0811452328 | m² | Fensterarbeiten | Fensteröffnung | 7.5 | 0 | AllplanAttributes - Feuerwiderstandsklasse: 0; Sicherheitsklasse: -; g-Wert: 0,51; U-Wert: 0.9; Schallschutzklasse: -; Sonnenschutztyp: Movable
Fensteröffnung | H1 Ebene 0 | 1555Fen0811452333 | m² | Fensterarbeiten | Fensteröffnung | 7.5 | 0 | AllplanAttributes - Feuerwiderstandsklasse: 0; Sicherheitsklasse: -; g-Wert: 0,51; U-Wert: 0.9; Schallschutzklasse: -; Sonnenschutztyp: Movable
Fensteröffnung | H1 Ebene 0 | 1555Fen0811452324 | m² | Fensterarbeiten | Fensteröffnung | 7.5 | 0 | AllplanAttributes - Feuerwiderstandsklasse: 0; Sicherheitsklasse: -; g-Wert: 0,51; U-Wert: 0.9; Schallschutzklasse: -; Sonnenschutztyp: Movable
Fensteröffnung | H1 Ebene 0 | 1555Fen0811452329 | m² | Fensterarbeiten | Fensteröffnung | 7.5 | 0 | AllplanAttributes - Feuerwiderstandsklasse: 0; Sicherheitsklasse: -; g-Wert: 0,51; U-Wert: 0.9; Schallschutzklasse: -; Sonnenschutztyp: Movable
Fensteröffnung | H1 Ebene 0 | 1555Fen0811452332 | m² | Fensterarbeiten | Fensteröffnung | 7.5 | 0 | AllplanAttributes - Feuerwiderstandsklasse: 0; Sicherheitsklasse: -; g-Wert: 0,51; U-Wert: 0.9; Schallschutzklasse: -; Sonnenschutztyp: Movable
Fensteröffnung | H1 Ebene 0 | 1555Fen0811452323 | m² | Fensterarbeiten | Fensteröffnung | 7.5 | 0 | AllplanAttributes - Feuerwiderstandsklasse: 0; Sicherheitsklasse: -; g-Wert: 0,51; U-Wert: 0.9; Schallschutzklasse: -; Sonnenschutztyp: Movable
Fensteröffnung | H1 Ebene 0 | 1555Fen0811452330 | m² | Fensterarbeiten | Fensteröffnung | 7.5 | 0 | AllplanAttributes - Feuerwiderstandsklasse: 0; Sicherheitsklasse: -; g-Wert: 0,51; U-Wert: 0.9; Schallschutzklasse: -; Sonnenschutztyp: Movable
Fensteröffnung | H1 Ebene 0 | 1555Fen0811452331 | m² | Fensterarbeiten | Fensteröffnung | 7.5 | 0 | AllplanAttributes - Feuerwiderstandsklasse: 0; Sicherheitsklasse: -; g-Wert: 0,51; U-Wert: 0.9; Schallschutzklasse: -; Sonnenschutztyp: Movable
Fensteröffnung | H1 Ebene 0 | 1555Fen0811455901 | m² | Fensterarbeiten | Fensteröffnung | 3.75
Fensteröffnung | H1 Ebene 0 | 1555Fen0811455880 | m² | Fensterarbeiten | Fensteröffnung | 3.75
Türöffnung | H1 Ebene 0 | 1555Tür0811456249 | m² | Trockenbauarbeiten | Türöffnung | 0 | AllplanAttributes - Codetext: Codetext; Türanschlag: DIN R; Positionsnummer_Text: S68; Attributset-Objekt: OpeningElement; P_ID: 1113Wa 0812742684; Feuerwiderstandsklasse: EI2 30; Rauchschutz: yes; Selbstschließend: yes; ash T_Zulage Schachttür: no; ash T_Dichtschließend: no; ash T_Feststellanlage (FSA): -; ash T_nicht abschließbar: no; W_Deckenanschluss: Gleitender Deckenanschluss Fall 01; Pset_OpeningElementCommon - FireExit: no; Reference: Codetext
Fensteröffnung | H1 Ebene 0 | 1555Fen0811455899 | m³ | Fensterarbeiten | Fensteröffnung | 7.5 | 0 | AllplanAttributes - Feuerwiderstandsklasse: 0; Sicherheitsklasse: -; g-Wert: 0,51; Material: Fensterelement; Außenliegend: yes; U-Wert: 0.9; Schallschutzklasse: -; Sonnenschutztyp: Movable
Fensteröffnung | H1 Ebene 0 | 1555Fen0811455881 | m³ | Fensterarbeiten | Fensteröffnung | 7.5 | 0 | AllplanAttributes - Feuerwiderstandsklasse: 0; Sicherheitsklasse: -; g-Wert: 0,51; Material: Fensterelement; Außenliegend: yes; U-Wert: 0.9; Schallschutzklasse: -; Sonnenschutztyp: Movable
Türöffnung | H1 Ebene 0 | 1555Tür0811456251 | m³ | Trockenbauarbeiten | Türöffnung |  | 0 | AllplanAttributes - Türanschlag: DIN R
Fensteröffnung | H1 Ebene 0 | 1555Fen0811455900 | m³ | Fensterarbeiten | Fensteröffnung | 7.5 | 0 | AllplanAttributes - Feuerwiderstandsklasse: 0; Sicherheitsklasse: -; g-Wert: 0,51; U-Wert: 0.9; Schallschutzklasse: -; Sonnenschutztyp: Movable
Fensteröffnung | H1 Ebene 0 | 1555Fen0811455882 | m³ | Fensterarbeiten | Fensteröffnung | 7.5 | 0 | AllplanAttributes - Feuerwiderstandsklasse: 0; Sicherheitsklasse: -; g-Wert: 0,51; U-Wert: 0.9; Schallschutzklasse: -; Sonnenschutztyp: Movable
Türöffnung | H1 Ebene 0 | 1555Tür0811456252 | m³ | Trockenbauarbeiten | Türöffnung |  | 0 | AllplanAttributes - Türanschlag: DIN R
Fensteröffnung | H1 Ebene 0 | 1555Fen0811455887 | m² | Fensterarbeiten | Fensteröffnung | 7.5 | 0 | AllplanAttributes - Feuerwiderstandsklasse: 0; Sicherheitsklasse: -; g-Wert: 0,51; U-Wert: 0.9; Schallschutzklasse: -; Sonnenschutztyp: Movable
Fensteröffnung | H1 Ebene 0 | 1555Fen0811455883 | m² | Fensterarbeiten | Fensteröffnung | 7.5 | 0 | AllplanAttributes - Feuerwiderstandsklasse: 0; Sicherheitsklasse: -; g-Wert: 0,51; U-Wert: 0.9; Schallschutzklasse: -; Sonnenschutztyp: Movable
Türöffnung | H1 Ebene 0 | 1555Tür0811456253 | m² | Trockenbauarbeiten | Türöffnung |  | 0 | AllplanAttributes - Türanschlag: DIN R
Fensteröffnung | H1 Ebene 0 | 1555Fen0811455888 | m² | Fensterarbeiten | Fensteröffnung | 7.5 | 0 | AllplanAttributes - Feuerwiderstandsklasse: 0; Sicherheitsklasse: -; g-Wert: 0,51; U-Wert: 0.9; Schallschutzklasse: -; Sonnenschutztyp: Movable
Fensteröffnung | H1 Ebene 0 | 1555Fen0811455884 | m² | Fensterarbeiten | Fensteröffnung | 7.5 | 0 | AllplanAttributes - Feuerwiderstandsklasse: 0; Sicherheitsklasse: -; g-Wert: 0,51; U-Wert: 0.9; Schallschutzklasse: -; Sonnenschutztyp: Movable
Türöffnung | H1 Ebene 0 | 1555Tür0811456254 | m² | Trockenbauarbeiten | Türöffnung |  | 0 | AllplanAttributes - Türanschlag: DIN R
Fensteröffnung | H1 Ebene 0 | 1555Fen0811455889 | m² | Fensterarbeiten | Fensteröffnung | 7.5 | 0 | AllplanAttributes - Feuerwiderstandsklasse: 0; Sicherheitsklasse: -; g-Wert: 0,51; U-Wert: 0.9; Schallschutzklasse: -; Sonnenschutztyp: Movable
Fensteröffnung | H1 Ebene 0 | 1555Fen0811455885 | m² | Fensterarbeiten | Fensteröffnung | 7.5 | 0 | AllplanAttributes - Feuerwiderstandsklasse: 0; Sicherheitsklasse: -; g-Wert: 0,51; U-Wert: 0.9; Schallschutzklasse: -; Sonnenschutztyp: Movable
Türöffnung | H1 Ebene 0 | 1555Tür0811456255 | m² | Trockenbauarbeiten | Türöffnung |  | 0 | AllplanAttributes - Türanschlag: DIN R
Fensteröffnung | H1 Ebene 0 | 1555Fen0811455890 | m² | Fensterarbeiten | Fensteröffnung | 7.5 | 0 | AllplanAttributes - Feuerwiderstandsklasse: 0; Sicherheitsklasse: -; g-Wert: 0,51; U-Wert: 0.9; Schallschutzklasse: -; Sonnenschutztyp: Movable
Fensteröffnung | H1 Ebene 0 | 1555Fen0811455886 | m² | Fensterarbeiten | Fensteröffnung | 7.5 | 0 | AllplanAttributes - Feuerwiderstandsklasse: 0; Sicherheitsklasse: -; g-Wert: 0,51; U-Wert: 0.9; Schallschutzklasse: -; Sonnenschutztyp: Movable
Türöffnung | H1 Ebene 0 | 1555Tür0811456256 | m² | Trockenbauarbeiten | Türöffnung |  | 0 | AllplanAttributes - Türanschlag: DIN R
Türöffnung | H1 Ebene 0 | 1555Tür0811452213 | m² | Trockenbauarbeiten | Türöffnung | 0 | AllplanAttributes - Codetext: Codetext; Türanschlag: -; Positionsnummer_Text: S68; Attributset-Objekt: OpeningElement; P_ID: 1113Wa 0812742684; Feuerwiderstandsklasse: EI2 30; Rauchschutz: yes; Selbstschließend: yes; ash T_Zulage Schachttür: no; ash T_Dichtschließend: no; ash T_Feststellanlage (FSA): -; ash T_nicht abschließbar: no; W_Deckenanschluss: Gleitender Deckenanschluss Fall 01; Pset_OpeningElementCommon - FireExit: no; Reference: Codetext
Fensteröffnung | H1 Ebene 0 | 1555Fen0811452250 | m² | Fensterarbeiten | Fensteröffnung | 3.75
Fensteröffnung | H1 Ebene 0 | 1555Fen0811452242 | m² | Fensterarbeiten | Fensteröffnung | 3.75
Fensteröffnung | H1 Ebene 0 | 1555Fen0811452243 | m² | Fensterarbeiten | Fensteröffnung | 3.75
Türöffnung | H1 Ebene 0 | 1555Tür0811452270 | m² | Trockenbauarbeiten | Türöffnung | 0 | AllplanAttributes - Codetext: Codetext; Türanschlag: DIN R; Positionsnummer_Text: S68; Attributset-Objekt: OpeningElement; P_ID: 1113Wa 0812742684; Feuerwiderstandsklasse: EI2 30; Rauchschutz: yes; Selbstschließend: yes; ash T_Zulage Schachttür: no; ash T_Dichtschließend: no; ash T_Feststellanlage (FSA): -; ash T_nicht abschließbar: no; W_Deckenanschluss: Gleitender Deckenanschluss Fall 01; Pset_OpeningElementCommon - FireExit: no; Reference: Codetext
Türöffnung | H1 Ebene 0 | 1555Tür0811452257 | m² | Trockenbauarbeiten | Türöffnung | 0 | AllplanAttributes - Codetext: Codetext; Türanschlag: DIN R; Positionsnummer_Text: S68; Attributset-Objekt: OpeningElement; P_ID: 1113Wa 0812742684; Feuerwiderstandsklasse: EI2 30; Rauchschutz: yes; Selbstschließend: yes; ash T_Zulage Schachttür: no; ash T_Dichtschließend: no; ash T_Feststellanlage (FSA): -; ash T_nicht abschließbar: no; W_Deckenanschluss: Gleitender Deckenanschluss Fall 01; Pset_OpeningElementCommon - FireExit: no; Reference: Codetext
Fensteröffnung | H1 Ebene 0 | 1555Fen0811452251 | m³ | Fensterarbeiten | Fensteröffnung | 7.5 | 0 | AllplanAttributes - Feuerwiderstandsklasse: 0; Sicherheitsklasse: -; g-Wert: 0,51; Material: Fensterelement; Außenliegend: yes; U-Wert: 0.9; Schallschutzklasse: -; Sonnenschutztyp: Movable
Fensteröffnung | H1 Ebene 0 | 1555Fen0811452241 | m³ | Fensterarbeiten | Fensteröffnung | 7.5 | 0 | AllplanAttributes - Feuerwiderstandsklasse: 0; Sicherheitsklasse: -; g-Wert: 0,51; Material: Fensterelement; Außenliegend: yes; U-Wert: 0.9; Schallschutzklasse: -; Sonnenschutztyp: Movable
Fensteröffnung | H1 Ebene 0 | 1555Fen0811452244 | m³ | Fensterarbeiten | Fensteröffnung | 7.5 | 0 | AllplanAttributes - Feuerwiderstandsklasse: 0; Sicherheitsklasse: -; g-Wert: 0,51; Material: Fensterelement; Außenliegend: yes; U-Wert: 0.9; Schallschutzklasse: -; Sonnenschutztyp: Movable
Türöffnung | H1 Ebene 0 | 1555Tür0811452269 | m³ | Trockenbauarbeiten | Türöffnung |  | 0 | AllplanAttributes - Türanschlag: DIN R
Türöffnung | H1 Ebene 0 | 1555Tür0811452258 | m³ | Trockenbauarbeiten | Türöffnung |  | 0 | AllplanAttributes - Türanschlag: DIN R
Fensteröffnung | H1 Ebene 0 | 1555Fen0811452252 | m³ | Fensterarbeiten | Fensteröffnung | 7.5 | 0 | AllplanAttributes - Feuerwiderstandsklasse: 0; Sicherheitsklasse: -; g-Wert: 0,51; U-Wert: 0.9; Schallschutzklasse: -; Sonnenschutztyp: Movable
Fensteröffnung | H1 Ebene 0 | 1555Fen0811452240 | m³ | Fensterarbeiten | Fensteröffnung | 7.5 | 0 | AllplanAttributes - Feuerwiderstandsklasse: 0; Sicherheitsklasse: -; g-Wert: 0,51; U-Wert: 0.9; Schallschutzklasse: -; Sonnenschutztyp: Movable
Fensteröffnung | H1 Ebene 0 | 1555Fen0811452245 | m³ | Fensterarbeiten | Fensteröffnung | 7.5 | 0 | AllplanAttributes - Feuerwiderstandsklasse: 0; Sicherheitsklasse: -; g-Wert: 0,51; U-Wert: 0.9; Schallschutzklasse: -; Sonnenschutztyp: Movable
Türöffnung | H1 Ebene 0 | 1555Tür0811452268 | m³ | Trockenbauarbeiten | Türöffnung |  | 0 | AllplanAttributes - Türanschlag: DIN R
Türöffnung | H1 Ebene 0 | 1555Tür0811452259 | m³ | Trockenbauarbeiten | Türöffnung |  | 0 | AllplanAttributes - Türanschlag: DIN R
Fensteröffnung | H1 Ebene 0 | 1555Fen0811452253 | m² | Fensterarbeiten | Fensteröffnung | 7.5 | 0 | AllplanAttributes - Feuerwiderstandsklasse: 0; Sicherheitsklasse: -; g-Wert: 0,51; U-Wert: 0.9; Schallschutzklasse: -; Sonnenschutztyp: Movable
Fensteröffnung | H1 Ebene 0 | 1555Fen0811452239 | m² | Fensterarbeiten | Fensteröffnung | 7.5 | 0 | AllplanAttributes - Feuerwiderstandsklasse: 0; Sicherheitsklasse: -; g-Wert: 0,51; U-Wert: 0.9; Schallschutzklasse: -; Sonnenschutztyp: Movable
Fensteröffnung | H1 Ebene 0 | 1555Fen0811452246 | m² | Fensterarbeiten | Fensteröffnung | 7.5 | 0 | AllplanAttributes - Feuerwiderstandsklasse: 0; Sicherheitsklasse: -; g-Wert: 0,51; U-Wert: 0.9; Schallschutzklasse: -; Sonnenschutztyp: Movable
Türöffnung | H1 Ebene 0 | 1555Tür0811452267 | m² | Trockenbauarbeiten | Türöffnung |  | 0 | AllplanAttributes - Türanschlag: DIN R
Türöffnung | H1 Ebene 0 | 1555Tür0811452260 | m² | Trockenbauarbeiten | Türöffnung |  | 0 | AllplanAttributes - Türanschlag: DIN R
Fensteröffnung | H1 Ebene 0 | 1555Fen0811452254 | m² | Fensterarbeiten | Fensteröffnung | 7.5 | 0 | AllplanAttributes - Feuerwiderstandsklasse: 0; Sicherheitsklasse: -; g-Wert: 0,51; U-Wert: 0.9; Schallschutzklasse: -; Sonnenschutztyp: Movable
Fensteröffnung | H1 Ebene 0 | 1555Fen0811452238 | m² | Fensterarbeiten | Fensteröffnung | 7.5 | 0 | AllplanAttributes - Feuerwiderstandsklasse: 0; Sicherheitsklasse: -; g-Wert: 0,51; U-Wert: 0.9; Schallschutzklasse: -; Sonnenschutztyp: Movable
Fensteröffnung | H1 Ebene 0 | 1555Fen0811452247 | m² | Fensterarbeiten | Fensteröffnung | 7.5 | 0 | AllplanAttributes - Feuerwiderstandsklasse: 0; Sicherheitsklasse: -; g-Wert: 0,51; U-Wert: 0.9; Schallschutzklasse: -; Sonnenschutztyp: Movable
Türöffnung | H1 Ebene 0 | 1555Tür0811452266 | m² | Trockenbauarbeiten | Türöffnung |  | 0 | AllplanAttributes - Türanschlag: DIN R
Türöffnung | H1 Ebene 0 | 1555Tür0811452261 | m² | Trockenbauarbeiten | Türöffnung |  | 0 | AllplanAttributes - Türanschlag: DIN R
Fensteröffnung | H1 Ebene 0 | 1555Fen0811452255 | m² | Fensterarbeiten | Fensteröffnung | 7.5 | 0 | AllplanAttributes - Feuerwiderstandsklasse: 0; Sicherheitsklasse: -; g-Wert: 0,51; U-Wert: 0.9; Schallschutzklasse: -; Sonnenschutztyp: Movable
Fensteröffnung | H1 Ebene 0 | 1555Fen0811452237 | m² | Fensterarbeiten | Fensteröffnung | 7.5 | 0 | AllplanAttributes - Feuerwiderstandsklasse: 0; Sicherheitsklasse: -; g-Wert: 0,51; U-Wert: 0.9; Schallschutzklasse: -; Sonnenschutztyp: Movable
Fensteröffnung | H1 Ebene 0 | 1555Fen0811452248 | m² | Fensterarbeiten | Fensteröffnung | 7.5 | 0 | AllplanAttributes - Feuerwiderstandsklasse: 0; Sicherheitsklasse: -; g-Wert: 0,51; U-Wert: 0.9; Schallschutzklasse: -; Sonnenschutztyp: Movable
Türöffnung | H1 Ebene 0 | 1555Tür0811452265 | m² | Trockenbauarbeiten | Türöffnung |  | 0 | AllplanAttributes - Türanschlag: DIN R
Türöffnung | H1 Ebene 0 | 1555Tür0811452262 | m² | Trockenbauarbeiten | Türöffnung |  | 0 | AllplanAttributes - Türanschlag: DIN R
Fensteröffnung | H1 Ebene 0 | 1555Fen0811452256 | m² | Fensterarbeiten | Fensteröffnung | 7.5 | 0 | AllplanAttributes - Feuerwiderstandsklasse: 0; Sicherheitsklasse: -; g-Wert: 0,51; U-Wert: 0.9; Schallschutzklasse: -; Sonnenschutztyp: Movable
Fensteröffnung | H1 Ebene 0 | 1555Fen0811452236 | m² | Fensterarbeiten | Fensteröffnung | 7.5 | 0 | AllplanAttributes - Feuerwiderstandsklasse: 0; Sicherheitsklasse: -; g-Wert: 0,51; U-Wert: 0.9; Schallschutzklasse: -; Sonnenschutztyp: Movable
Fensteröffnung | H1 Ebene 0 | 1555Fen0811452249 | m² | Fensterarbeiten | Fensteröffnung | 7.5 | 0 | AllplanAttributes - Feuerwiderstandsklasse: 0; Sicherheitsklasse: -; g-Wert: 0,51; U-Wert: 0.9; Schallschutzklasse: -; Sonnenschutztyp: Movable
Türöffnung | H1 Ebene 0 | 1555Tür0811452264 | m² | Trockenbauarbeiten | Türöffnung |  | 0 | AllplanAttributes - Türanschlag: DIN R
Türöffnung | H1 Ebene 0 | 1555Tür0811452263 | m² | Trockenbauarbeiten | Türöffnung |  | 0 | AllplanAttributes - Türanschlag: DIN R
Türöffnung | H1 Ebene 0 | 1555Tür0811452316 | m² | Trockenbauarbeiten | Türöffnung | 0 | AllplanAttributes - Codetext: Codetext; Türanschlag: DIN L; Positionsnummer_Text: S68; Attributset-Objekt: OpeningElement; P_ID: 1113Wa 0812742684; Feuerwiderstandsklasse: EI2 30; Rauchschutz: yes; Selbstschließend: yes; ash T_Zulage Schachttür: no; ash T_Dichtschließend: no; ash T_Feststellanlage (FSA): -; ash T_nicht abschließbar: no; W_Deckenanschluss: Gleitender Deckenanschluss Fall 01; Pset_OpeningElementCommon - FireExit: no; Reference: Codetext
Türöffnung | H1 Ebene 0 | 1555Tür0811452317 | m³ | Trockenbauarbeiten | Türöffnung |  | 0 | AllplanAttributes - Türanschlag: DIN L
Türöffnung | H1 Ebene 0 | 1555Tür0811452318 | m³ | Trockenbauarbeiten | Türöffnung |  | 0 | AllplanAttributes - Türanschlag: DIN L
Türöffnung | H1 Ebene 0 | 1555Tür0811452319 | m² | Trockenbauarbeiten | Türöffnung |  | 0 | AllplanAttributes - Türanschlag: DIN L
Türöffnung | H1 Ebene 0 | 1555Tür0811452320 | m² | Trockenbauarbeiten | Türöffnung |  | 0 | AllplanAttributes - Türanschlag: DIN L
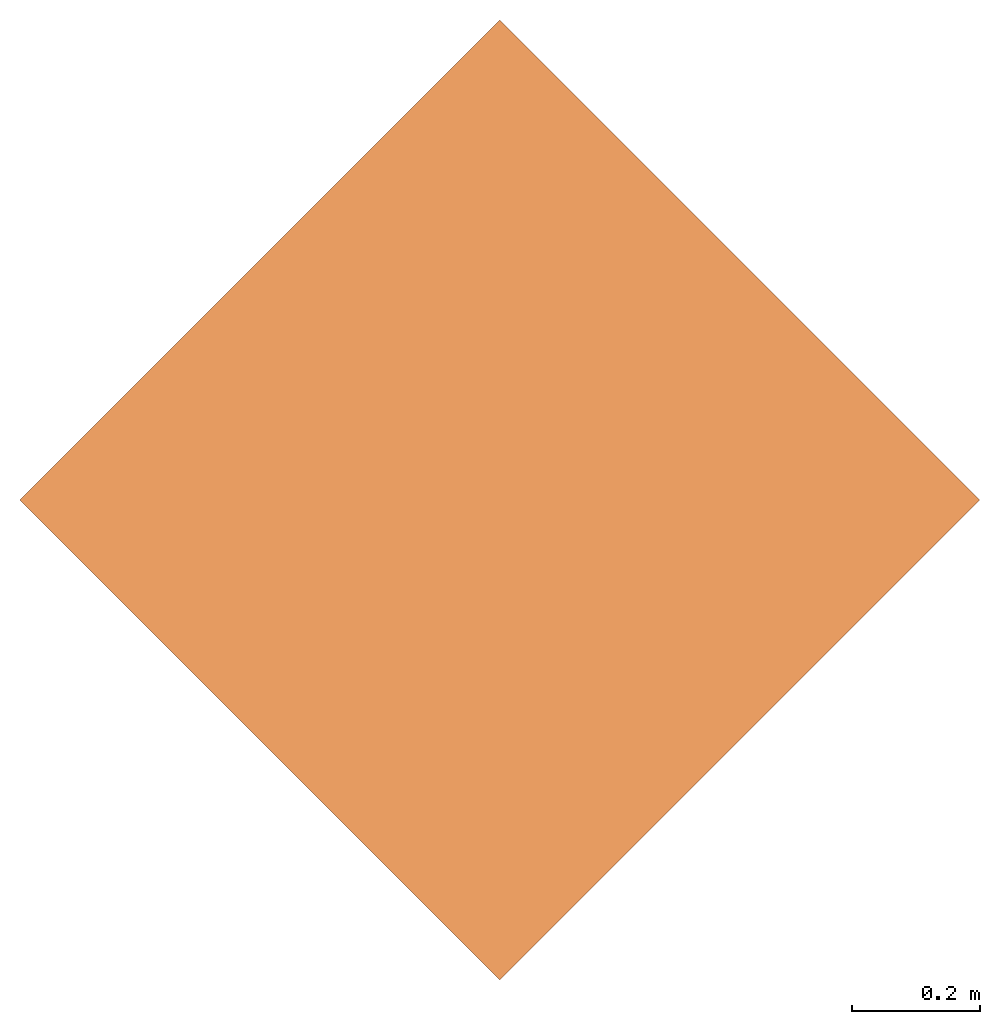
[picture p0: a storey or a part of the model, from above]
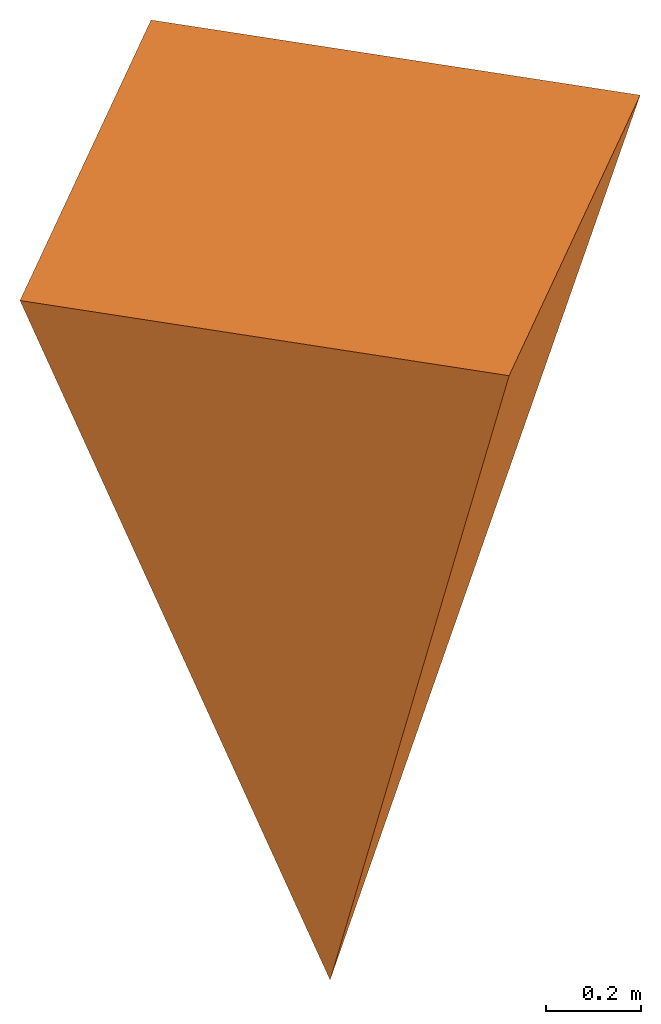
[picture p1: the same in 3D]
Properties of the parts of a building model (IFC4), part 3 of 4

# IfcOpeningElement: Opening (238)
Name | In | Allright_Bauteil_ID | Abrechnungsart | Gewerk | Objektname | OKFF | Versatz_oben = Versatz_unten
Türöffnung | H1 Ebene 0 | 1555Tür0811452321 | m² | Trockenbauarbeiten | Türöffnung |  | 0 | AllplanAttributes - Türanschlag: DIN L
Türöffnung | H1 Ebene 0 | 1555Tür0811452322 | m² | Trockenbauarbeiten | Türöffnung |  | 0 | AllplanAttributes - Türanschlag: DIN L
Wanddurchbruch | H1 Ebene 0 | 1556Wdu0000003671 | m² | Trockenbauarbeiten | WD rund UKD | 0 | 0
Wanddurchbruch | H1 Ebene 0 | 1556Wdu0000003652 | m² | Trockenbauarbeiten | WD rund UKD | 0 | 0
Wanddurchbruch | H1 Ebene 0 | 1556Wdu0000003613 | m² | Trockenbauarbeiten | WD rund UKD | 0 | 0
Wanddurchbruch | H1 Ebene 0 | 1556Wdu0000003672 | m² | Trockenbauarbeiten | WD rund UKD | 0 | 0
Wanddurchbruch | H1 Ebene 0 | 1556Wdu0000003651 | m² | Trockenbauarbeiten | WD rund UKD | 0 | 0
Wanddurchbruch | H1 Ebene 0 | 1556Wdu0000003612 | m² | Trockenbauarbeiten | WD rund UKD | 0 | 0
Wanddurchbruch | H1 Ebene 0 | 1556Wdu0000003673 | m³ | Trockenbauarbeiten | WD rund UKD | 0 | 0
Wanddurchbruch | H1 Ebene 0 | 1556Wdu0000003650 | m³ | Trockenbauarbeiten | WD rund UKD | 0 | 0
Wanddurchbruch | H1 Ebene 0 | 1556Wdu0000003611 | m³ | Trockenbauarbeiten | WD rund UKD | 0 | 0
Wanddurchbruch | H1 Ebene 0 | 1556Wdu0000003674 | m² | Trockenbauarbeiten | WD rund UKD | 0 | 0
Wanddurchbruch | H1 Ebene 0 | 1556Wdu0000003649 | m² | Trockenbauarbeiten | WD rund UKD | 0 | 0
Wanddurchbruch | H1 Ebene 0 | 1556Wdu0000003610 | m² | Trockenbauarbeiten | WD rund UKD | 0 | 0
Wanddurchbruch | H1 Ebene 0 | 1556Wdu0000003541 | m² | Trockenbauarbeiten | WD rund UKD | 0 | 0
Wanddurchbruch | H1 Ebene 0 | 1556Wdu0000003380 | m² | Trockenbauarbeiten | WD rund UKD | 0 | 0
Wanddurchbruch | H1 Ebene 0 | 1556Wdu0000003456 | m² | Trockenbauarbeiten | WD rund UKD | 0 | 0
Wanddurchbruch | H1 Ebene 0 | 1556Wdu0000003542 | m² | Betonarbeiten | WD rund UKD | 0 | 0
Wanddurchbruch | H1 Ebene 0 | 1556Wdu0000003379 | m² | Betonarbeiten | WD rund UKD | 0 | 0
Wanddurchbruch | H1 Ebene 0 | 1556Wdu0000003455 | m² | Betonarbeiten | WD rund UKD | 0 | 0
Wanddurchbruch | H1 Ebene 0 | 1556Wdu0000003543 | m³ | Wärmedämm-Verbundsysteme | WD rund UKD | 0 | 0
Wanddurchbruch | H1 Ebene 0 | 1556Wdu0000003378 | m³ | Wärmedämm-Verbundsysteme | WD rund UKD | 0 | 0
Wanddurchbruch | H1 Ebene 0 | 1556Wdu0000003454 | m³ | Wärmedämm-Verbundsysteme | WD rund UKD | 0 | 0
Wanddurchbruch | H1 Ebene 0 | 1556Wdu0000003544 | m² | Trockenbauarbeiten | WD rund UKD | 0 | 0
Wanddurchbruch | H1 Ebene 0 | 1556Wdu0000003377 | m² | Trockenbauarbeiten | WD rund UKD | 0 | 0
Wanddurchbruch | H1 Ebene 0 | 1556Wdu0000003453 | m² | Trockenbauarbeiten | WD rund UKD | 0 | 0
Wanddurchbruch | H1 Ebene 0 | 1556Wdu0000003841 | m² | Trockenbauarbeiten | WD rund UKD | 0 | 0
Wanddurchbruch | H1 Ebene 0 | 1556Wdu0000003840 | m² | Trockenbauarbeiten | WD rund UKD | 0 | 0
Wanddurchbruch | H1 Ebene 0 | 1556Wdu0000003839 | m³ | Trockenbauarbeiten | WD rund UKD | 0 | 0
Wanddurchbruch | H1 Ebene 0 | 1556Wdu0000003838 | m² | Trockenbauarbeiten | WD rund UKD | 0 | 0
Wanddurchbruch | H1 Ebene 0 | 1556Wdu0000003803 | m² | Trockenbauarbeiten | WD rund UKD | 0 | 0
Wanddurchbruch | H1 Ebene 0 | 1556Wdu0000003802 | m² | Trockenbauarbeiten | WD rund UKD | 0 | 0
Wanddurchbruch | H1 Ebene 0 | 1556Wdu0000003801 | m³ | Trockenbauarbeiten | WD rund UKD | 0 | 0
Wanddurchbruch | H1 Ebene 0 | 1556Wdu0000003800 | m² | Trockenbauarbeiten | WD rund UKD | 0 | 0
Wanddurchbruch | H1 Ebene 0 | 1556Wdu0000003935 | m² | Trockenbauarbeiten | WD rund UKD | 0 | 0
Wanddurchbruch | H1 Ebene 0 | 1556Wdu0000003934 | m² | Trockenbauarbeiten | WD rund UKD | 0 | 0
Wanddurchbruch | H1 Ebene 0 | 1556Wdu0000003933 | m³ | Trockenbauarbeiten | WD rund UKD | 0 | 0
Wanddurchbruch | H1 Ebene 0 | 1556Wdu0000003932 | m² | Trockenbauarbeiten | WD rund UKD | 0 | 0
Wanddurchbruch | H1 Ebene 0 | 1556Wdu0000004110 | m² | Trockenbauarbeiten | WD rund UKD | 0 | 0
Wanddurchbruch | H1 Ebene 0 | 1556Wdu0000004085 | m² | Trockenbauarbeiten | WD rund UKD | 0 | 0
Wanddurchbruch | H1 Ebene 0 | 1556Wdu0000004066 | m² | Trockenbauarbeiten | WD rund UKD | 0 | 0
Wanddurchbruch | H1 Ebene 0 | 1556Wdu0000004041 | m² | Trockenbauarbeiten | WD rund UKD | 0 | 0
Wanddurchbruch | H1 Ebene 0 | 1556Wdu0000004021 | m² | Trockenbauarbeiten | WD rund UKD | 0 | 0
Wanddurchbruch | H1 Ebene 0 | 1556Wdu0000004109 | m² | Trockenbauarbeiten | WD rund UKD | 0 | 0
Wanddurchbruch | H1 Ebene 0 | 1556Wdu0000004086 | m² | Trockenbauarbeiten | WD rund UKD | 0 | 0
Wanddurchbruch | H1 Ebene 0 | 1556Wdu0000004065 | m² | Trockenbauarbeiten | WD rund UKD | 0 | 0
Wanddurchbruch | H1 Ebene 0 | 1556Wdu0000004042 | m² | Trockenbauarbeiten | WD rund UKD | 0 | 0
Wanddurchbruch | H1 Ebene 0 | 1556Wdu0000004020 | m² | Trockenbauarbeiten | WD rund UKD | 0 | 0
Wanddurchbruch | H1 Ebene 0 | 1556Wdu0000004108 | m³ | Trockenbauarbeiten | WD rund UKD | 0 | 0
Wanddurchbruch | H1 Ebene 0 | 1556Wdu0000004087 | m³ | Trockenbauarbeiten | WD rund UKD | 0 | 0
Wanddurchbruch | H1 Ebene 0 | 1556Wdu0000004064 | m³ | Trockenbauarbeiten | WD rund UKD | 0 | 0
Wanddurchbruch | H1 Ebene 0 | 1556Wdu0000004043 | m³ | Trockenbauarbeiten | WD rund UKD | 0 | 0
Wanddurchbruch | H1 Ebene 0 | 1556Wdu0000004019 | m³ | Trockenbauarbeiten | WD rund UKD | 0 | 0
Wanddurchbruch | H1 Ebene 0 | 1556Wdu0000004107 | m² | Trockenbauarbeiten | WD rund UKD | 0 | 0
Wanddurchbruch | H1 Ebene 0 | 1556Wdu0000004088 | m² | Trockenbauarbeiten | WD rund UKD | 0 | 0
Wanddurchbruch | H1 Ebene 0 | 1556Wdu0000004063 | m² | Trockenbauarbeiten | WD rund UKD | 0 | 0
Wanddurchbruch | H1 Ebene 0 | 1556Wdu0000004044 | m² | Trockenbauarbeiten | WD rund UKD | 0 | 0
Wanddurchbruch | H1 Ebene 0 | 1556Wdu0000004018 | m² | Trockenbauarbeiten | WD rund UKD | 0 | 0
Türöffnung | H1 Ebene 0 | 1563Tür0813612183 | m² | Trockenbauarbeiten | Türöffnung | 0 | AllplanAttributes - Codetext: Codetext; Türanschlag: -; Positionsnummer_Text: S68; Attributset-Objekt: OpeningElement; P_ID: 1113Wa 0812742684; Feuerwiderstandsklasse: EI2 30; Rauchschutz: yes; Selbstschließend: yes; ash T_Zulage Schachttür: no; ash T_Dichtschließend: no; ash T_Feststellanlage (FSA): -; ash T_nicht abschließbar: no; W_Deckenanschluss: Gleitender Deckenanschluss Fall 01; Pset_OpeningElementCommon - FireExit: no; Reference: Codetext
Türöffnung | H1 Ebene 0 | 1563Tür0813612185 | m² | Trockenbauarbeiten | Türöffnung | 0 | AllplanAttributes - Codetext: Codetext; Türanschlag: DIN L; Positionsnummer_Text: S68; Attributset-Objekt: OpeningElement; P_ID: 1113Wa 0812742684; Feuerwiderstandsklasse: EI2 30; Rauchschutz: yes; Selbstschließend: yes; ash T_Zulage Schachttür: no; ash T_Dichtschließend: no; ash T_Feststellanlage (FSA): -; ash T_nicht abschließbar: no; W_Deckenanschluss: Gleitender Deckenanschluss Fall 01; Pset_OpeningElementCommon - FireExit: no; Reference: Codetext
Türöffnung | H1 Ebene 0 | 1563Tür0813612279 | m² | Trockenbauarbeiten | Türöffnung | 0 | AllplanAttributes - Codetext: Codetext; Türanschlag: DIN R; Positionsnummer_Text: S68; Attributset-Objekt: OpeningElement; P_ID: 1113Wa 0812742684; Feuerwiderstandsklasse: EI2 30; Rauchschutz: yes; Selbstschließend: yes; ash T_Zulage Schachttür: no; ash T_Dichtschließend: no; ash T_Feststellanlage (FSA): -; ash T_nicht abschließbar: no; W_Deckenanschluss: Gleitender Deckenanschluss Fall 01; Pset_OpeningElementCommon - FireExit: no; Reference: Codetext
Türöffnung | H1 Ebene 0 | 1563Tür0813612266 | m² | Trockenbauarbeiten | Türöffnung | 0 | AllplanAttributes - Codetext: Codetext; Türanschlag: DIN L; Positionsnummer_Text: S68; Attributset-Objekt: OpeningElement; P_ID: 1113Wa 0812742684; Feuerwiderstandsklasse: EI2 30; Rauchschutz: yes; Selbstschließend: yes; ash T_Zulage Schachttür: no; ash T_Dichtschließend: no; ash T_Feststellanlage (FSA): -; ash T_nicht abschließbar: no; W_Deckenanschluss: Gleitender Deckenanschluss Fall 01; Pset_OpeningElementCommon - FireExit: no; Reference: Codetext
Türöffnung | H1 Ebene 0 | 1563Tür0813612269 | m² | Trockenbauarbeiten | Türöffnung | 0 | AllplanAttributes - Codetext: Codetext; Türanschlag: DIN R; Positionsnummer_Text: S68; Attributset-Objekt: OpeningElement; P_ID: 1113Wa 0812742684; Feuerwiderstandsklasse: EI2 30; Rauchschutz: yes; Selbstschließend: yes; ash T_Zulage Schachttür: no; ash T_Dichtschließend: no; ash T_Feststellanlage (FSA): -; ash T_nicht abschließbar: no; W_Deckenanschluss: Gleitender Deckenanschluss Fall 01; Pset_OpeningElementCommon - FireExit: no; Reference: Codetext
Türöffnung | H1 Ebene 0 | 1563Tür0813612272 | m² | Trockenbauarbeiten | Türöffnung | 0 | AllplanAttributes - Codetext: Codetext; Türanschlag: DIN L; Positionsnummer_Text: S68; Attributset-Objekt: OpeningElement; P_ID: 1113Wa 0812742684; Feuerwiderstandsklasse: EI2 30; Rauchschutz: yes; Selbstschließend: yes; ash T_Zulage Schachttür: no; ash T_Dichtschließend: no; ash T_Feststellanlage (FSA): -; ash T_nicht abschließbar: no; W_Deckenanschluss: Gleitender Deckenanschluss Fall 01; Pset_OpeningElementCommon - FireExit: no; Reference: Codetext
Türöffnung | H1 Ebene 0 | 1563Tür0813612276 | m² | Trockenbauarbeiten | Türöffnung | 0 | AllplanAttributes - Codetext: Codetext; Türanschlag: DIN L; Positionsnummer_Text: S68; Attributset-Objekt: OpeningElement; P_ID: 1113Wa 0812742684; Feuerwiderstandsklasse: EI2 30; Rauchschutz: yes; Selbstschließend: yes; ash T_Zulage Schachttür: no; ash T_Dichtschließend: no; ash T_Feststellanlage (FSA): -; ash T_nicht abschließbar: no; W_Deckenanschluss: Gleitender Deckenanschluss Fall 01; Pset_OpeningElementCommon - FireExit: no; Reference: Codetext
Türöffnung | H1 Ebene 0 | 1563Tür0813612227 | m² | Trockenbauarbeiten | Türöffnung | 0 | AllplanAttributes - Codetext: Codetext; Türanschlag: DIN L; Positionsnummer_Text: S68; Attributset-Objekt: OpeningElement; P_ID: 1113Wa 0812742684; Feuerwiderstandsklasse: EI2 30; Rauchschutz: yes; Selbstschließend: yes; ash T_Zulage Schachttür: no; ash T_Dichtschließend: no; ash T_Feststellanlage (FSA): -; ash T_nicht abschließbar: no; W_Deckenanschluss: Gleitender Deckenanschluss Fall 01; Pset_OpeningElementCommon - FireExit: no; Reference: Codetext
Türöffnung | H1 Ebene 0 | 1563Tür0813612223 | m² | Trockenbauarbeiten | Türöffnung | 0 | AllplanAttributes - Codetext: Codetext; Türanschlag: DIN L; Positionsnummer_Text: S68; Attributset-Objekt: OpeningElement; P_ID: 1113Wa 0812742684; Feuerwiderstandsklasse: EI2 30; Rauchschutz: yes; Selbstschließend: yes; ash T_Zulage Schachttür: no; ash T_Dichtschließend: no; ash T_Feststellanlage (FSA): -; ash T_nicht abschließbar: no; W_Deckenanschluss: Gleitender Deckenanschluss Fall 01; Pset_OpeningElementCommon - FireExit: no; Reference: Codetext
Türöffnung | H1 Ebene 0 | 1563Tür0813612262 | m² | Trockenbauarbeiten | Türöffnung | 0 | AllplanAttributes - Codetext: Codetext; Türanschlag: DIN R; Positionsnummer_Text: S68; Attributset-Objekt: OpeningElement; P_ID: 1113Wa 0812742684; Feuerwiderstandsklasse: EI2 30; Rauchschutz: yes; Selbstschließend: yes; ash T_Zulage Schachttür: no; ash T_Dichtschließend: no; ash T_Feststellanlage (FSA): -; ash T_nicht abschließbar: no; W_Deckenanschluss: Gleitender Deckenanschluss Fall 01; Pset_OpeningElementCommon - FireExit: no; Reference: Codetext
Türöffnung | H1 Ebene 0 | 1563Tür0813612250 | m² | Trockenbauarbeiten | Türöffnung | 0 | AllplanAttributes - Codetext: Codetext; Türanschlag: DIN R; Positionsnummer_Text: S68; Attributset-Objekt: OpeningElement; P_ID: 1113Wa 0812742684; Feuerwiderstandsklasse: EI2 30; Rauchschutz: yes; Selbstschließend: yes; ash T_Zulage Schachttür: no; ash T_Dichtschließend: no; ash T_Feststellanlage (FSA): -; ash T_nicht abschließbar: no; W_Deckenanschluss: Gleitender Deckenanschluss Fall 01; Pset_OpeningElementCommon - FireExit: no; Reference: Codetext
Türöffnung | H1 Ebene 0 | 1563Tür0813612246 | m² | Trockenbauarbeiten | Türöffnung | 0 | AllplanAttributes - Codetext: Codetext; Türanschlag: DIN L; Positionsnummer_Text: S68; Attributset-Objekt: OpeningElement; P_ID: 1113Wa 0812742684; Feuerwiderstandsklasse: EI2 30; Rauchschutz: yes; Selbstschließend: yes; ash T_Zulage Schachttür: no; ash T_Dichtschließend: no; ash T_Feststellanlage (FSA): -; ash T_nicht abschließbar: no; W_Deckenanschluss: Gleitender Deckenanschluss Fall 01; Pset_OpeningElementCommon - FireExit: no; Reference: Codetext
Türöffnung | H1 Ebene 0 | 1563Tür0813612243 | m² | Trockenbauarbeiten | Türöffnung | 0 | AllplanAttributes - Codetext: Codetext; Türanschlag: DIN L; Positionsnummer_Text: S68; Attributset-Objekt: OpeningElement; P_ID: 1113Wa 0812742684; Feuerwiderstandsklasse: EI2 30; Rauchschutz: yes; Selbstschließend: yes; ash T_Zulage Schachttür: no; ash T_Dichtschließend: no; ash T_Feststellanlage (FSA): -; ash T_nicht abschließbar: no; W_Deckenanschluss: Gleitender Deckenanschluss Fall 01; Pset_OpeningElementCommon - FireExit: no; Reference: Codetext
Türöffnung | H1 Ebene 0 | 1563Tür0813612240 | m² | Trockenbauarbeiten | Türöffnung | 0 | AllplanAttributes - Codetext: Codetext; Türanschlag: DIN L; Positionsnummer_Text: S68; Attributset-Objekt: OpeningElement; P_ID: 1113Wa 0812742684; Feuerwiderstandsklasse: EI2 30; Rauchschutz: yes; Selbstschließend: yes; ash T_Zulage Schachttür: no; ash T_Dichtschließend: no; ash T_Feststellanlage (FSA): -; ash T_nicht abschließbar: no; W_Deckenanschluss: Gleitender Deckenanschluss Fall 01; Pset_OpeningElementCommon - FireExit: no; Reference: Codetext
Türöffnung | H1 Ebene 0 | 1563Tür0813612219 | m² | Trockenbauarbeiten | Türöffnung | 0 | AllplanAttributes - Codetext: Codetext; Türanschlag: DIN L; Positionsnummer_Text: S68; Attributset-Objekt: OpeningElement; P_ID: 1113Wa 0812742684; Feuerwiderstandsklasse: EI2 30; Rauchschutz: yes; Selbstschließend: yes; ash T_Zulage Schachttür: no; ash T_Dichtschließend: no; ash T_Feststellanlage (FSA): -; ash T_nicht abschließbar: no; W_Deckenanschluss: Gleitender Deckenanschluss Fall 01; Pset_OpeningElementCommon - FireExit: no; Reference: Codetext
Türöffnung | H1 Ebene 0 | 1563Tür0813612215 | m² | Trockenbauarbeiten | Türöffnung | 0 | AllplanAttributes - Codetext: Codetext; Türanschlag: DIN R; Positionsnummer_Text: S68; Attributset-Objekt: OpeningElement; P_ID: 1113Wa 0812742684; Feuerwiderstandsklasse: EI2 30; Rauchschutz: yes; Selbstschließend: yes; ash T_Zulage Schachttür: no; ash T_Dichtschließend: no; ash T_Feststellanlage (FSA): -; ash T_nicht abschließbar: no; W_Deckenanschluss: Gleitender Deckenanschluss Fall 01; Pset_OpeningElementCommon - FireExit: no; Reference: Codetext
Türöffnung | H1 Ebene 0 | 1563Tür0813612200 | m² | Trockenbauarbeiten | Türöffnung | 0 | AllplanAttributes - Codetext: Codetext; Türanschlag: DIN R; Positionsnummer_Text: S68; Attributset-Objekt: OpeningElement; P_ID: 1113Wa 0812742684; Feuerwiderstandsklasse: EI2 30; Rauchschutz: yes; Selbstschließend: yes; ash T_Zulage Schachttür: no; ash T_Dichtschließend: no; ash T_Feststellanlage (FSA): -; ash T_nicht abschließbar: no; W_Deckenanschluss: Gleitender Deckenanschluss Fall 01; Pset_OpeningElementCommon - FireExit: no; Reference: Codetext
Türöffnung | H1 Ebene 0 | 1563Tür0813612204 | m² | Trockenbauarbeiten | Türöffnung | 0 | AllplanAttributes - Codetext: Codetext; Türanschlag: DIN L; Positionsnummer_Text: S68; Attributset-Objekt: OpeningElement; P_ID: 1113Wa 0812742684; Feuerwiderstandsklasse: EI2 30; Rauchschutz: yes; Selbstschließend: yes; ash T_Zulage Schachttür: no; ash T_Dichtschließend: no; ash T_Feststellanlage (FSA): -; ash T_nicht abschließbar: no; W_Deckenanschluss: Gleitender Deckenanschluss Fall 01; Pset_OpeningElementCommon - FireExit: no; Reference: Codetext
Türöffnung | H1 Ebene 0 | 1563Tür0813612208 | m² | Trockenbauarbeiten | Türöffnung | 0 | AllplanAttributes - Codetext: Codetext; Türanschlag: DIN R; Positionsnummer_Text: S68; Attributset-Objekt: OpeningElement; P_ID: 1113Wa 0812742684; Feuerwiderstandsklasse: EI2 30; Rauchschutz: yes; Selbstschließend: yes; ash T_Zulage Schachttür: no; ash T_Dichtschließend: no; ash T_Feststellanlage (FSA): -; ash T_nicht abschließbar: no; W_Deckenanschluss: Gleitender Deckenanschluss Fall 01; Pset_OpeningElementCommon - FireExit: no; Reference: Codetext
Türöffnung | H1 Ebene 0 | 1563Tür0813612211 | m² | Trockenbauarbeiten | Türöffnung | 0 | AllplanAttributes - Codetext: Codetext; Türanschlag: DIN L; Positionsnummer_Text: S68; Attributset-Objekt: OpeningElement; P_ID: 1113Wa 0812742684; Feuerwiderstandsklasse: EI2 30; Rauchschutz: yes; Selbstschließend: yes; ash T_Zulage Schachttür: no; ash T_Dichtschließend: no; ash T_Feststellanlage (FSA): -; ash T_nicht abschließbar: no; W_Deckenanschluss: Gleitender Deckenanschluss Fall 01; Pset_OpeningElementCommon - FireExit: no; Reference: Codetext
Türöffnung | H1 Ebene 0 | 1563Tür0813612193 | m² | Trockenbauarbeiten | Türöffnung | 0 | AllplanAttributes - Codetext: Codetext; Türanschlag: DIN R; Positionsnummer_Text: S68; Attributset-Objekt: OpeningElement; P_ID: 1113Wa 0812742684; Feuerwiderstandsklasse: EI2 30; Rauchschutz: yes; Selbstschließend: yes; ash T_Zulage Schachttür: no; ash T_Dichtschließend: no; ash T_Feststellanlage (FSA): -; ash T_nicht abschließbar: no; W_Deckenanschluss: Gleitender Deckenanschluss Fall 01; Pset_OpeningElementCommon - FireExit: no; Reference: Codetext
Türöffnung | H1 Ebene 0 | 1563Tür0813612197 | m² | Trockenbauarbeiten | Türöffnung | 0 | AllplanAttributes - Codetext: Codetext; Türanschlag: DIN R; Positionsnummer_Text: S68; Attributset-Objekt: OpeningElement; P_ID: 1113Wa 0812742684; Feuerwiderstandsklasse: EI2 30; Rauchschutz: yes; Selbstschließend: yes; ash T_Zulage Schachttür: no; ash T_Dichtschließend: no; ash T_Feststellanlage (FSA): -; ash T_nicht abschließbar: no; W_Deckenanschluss: Gleitender Deckenanschluss Fall 01; Pset_OpeningElementCommon - FireExit: no; Reference: Codetext
Türöffnung | H1 Ebene 0 | 1563Tür0813612189 | m² | Trockenbauarbeiten | Türöffnung | 0 | AllplanAttributes - Codetext: Codetext; Türanschlag: DIN L; Positionsnummer_Text: S68; Attributset-Objekt: OpeningElement; P_ID: 1113Wa 0812742684; Feuerwiderstandsklasse: EI2 30; Rauchschutz: yes; Selbstschließend: yes; ash T_Zulage Schachttür: no; ash T_Dichtschließend: no; ash T_Feststellanlage (FSA): -; ash T_nicht abschließbar: no; W_Deckenanschluss: Gleitender Deckenanschluss Fall 01; Pset_OpeningElementCommon - FireExit: no; Reference: Codetext
Türöffnung | H1 Ebene 0 | 1563Tür0813612237 | m² | Trockenbauarbeiten | Türöffnung | 0 | AllplanAttributes - Codetext: Codetext; Türanschlag: DIN R; Positionsnummer_Text: S68; Attributset-Objekt: OpeningElement; P_ID: 1113Wa 0812742684; Feuerwiderstandsklasse: EI2 30; Rauchschutz: yes; Selbstschließend: yes; ash T_Zulage Schachttür: no; ash T_Dichtschließend: no; ash T_Feststellanlage (FSA): -; ash T_nicht abschließbar: no; W_Deckenanschluss: Gleitender Deckenanschluss Fall 01; Pset_OpeningElementCommon - FireExit: no; Reference: Codetext
Türöffnung | H1 Ebene 0 | 1563Tür0813612234 | m² | Trockenbauarbeiten | Türöffnung | 0 | AllplanAttributes - Codetext: Codetext; Türanschlag: DIN R; Positionsnummer_Text: S68; Attributset-Objekt: OpeningElement; P_ID: 1113Wa 0812742684; Feuerwiderstandsklasse: EI2 30; Rauchschutz: yes; Selbstschließend: yes; ash T_Zulage Schachttür: no; ash T_Dichtschließend: no; ash T_Feststellanlage (FSA): -; ash T_nicht abschließbar: no; W_Deckenanschluss: Gleitender Deckenanschluss Fall 01; Pset_OpeningElementCommon - FireExit: no; Reference: Codetext
Türöffnung | H1 Ebene 0 | 1563Tür0813612230 | m² | Trockenbauarbeiten | Türöffnung | 0 | AllplanAttributes - Codetext: Codetext; Türanschlag: DIN R; Positionsnummer_Text: S68; Attributset-Objekt: OpeningElement; P_ID: 1113Wa 0812742684; Feuerwiderstandsklasse: EI2 30; Rauchschutz: yes; Selbstschließend: yes; ash T_Zulage Schachttür: no; ash T_Dichtschließend: no; ash T_Feststellanlage (FSA): -; ash T_nicht abschließbar: no; W_Deckenanschluss: Gleitender Deckenanschluss Fall 01; Pset_OpeningElementCommon - FireExit: no; Reference: Codetext
Türöffnung | H1 Ebene 0 | 1563Tür0813612258 | m² | Trockenbauarbeiten | Türöffnung | 0 | AllplanAttributes - Codetext: Codetext; Türanschlag: DIN L; Positionsnummer_Text: S68; Attributset-Objekt: OpeningElement; P_ID: 1113Wa 0812742684; Feuerwiderstandsklasse: EI2 30; Rauchschutz: yes; Selbstschließend: yes; ash T_Zulage Schachttür: no; ash T_Dichtschließend: no; ash T_Feststellanlage (FSA): -; ash T_nicht abschließbar: no; W_Deckenanschluss: Gleitender Deckenanschluss Fall 01; Pset_OpeningElementCommon - FireExit: no; Reference: Codetext
Türöffnung | H1 Ebene 0 | 1563Tür0813612254 | m² | Trockenbauarbeiten | Türöffnung | 0 | AllplanAttributes - Codetext: Codetext; Türanschlag: DIN R; Positionsnummer_Text: S68; Attributset-Objekt: OpeningElement; P_ID: 1113Wa 0812742684; Feuerwiderstandsklasse: EI2 30; Rauchschutz: yes; Selbstschließend: yes; ash T_Zulage Schachttür: no; ash T_Dichtschließend: no; ash T_Feststellanlage (FSA): -; ash T_nicht abschließbar: no; W_Deckenanschluss: Gleitender Deckenanschluss Fall 01; Pset_OpeningElementCommon - FireExit: no; Reference: Codetext

# IfcRoof (63)
In: H1 Ebene +1
Pset_RoofCommon - Status: NEW
Name | Material = AllplanAttributes, Material | 2D Interaktion | Gewerk | Spannweite = OKFF | Allright_Bauteil_ID | Abrechnungsart | Objektname | IsExternal | ThermalTransmittance (W/K/m2)
 | Schwerlast-Deckenprofil | yes | Trockenbauarbeiten | 0 | 1613Unz2005708179 | m³ | Unterzug | no | 0
 | Schwerlast-Deckenprofil | yes | Trockenbauarbeiten | 0 | 1613Unz2005708414 | m³ | Unterzug | no | 0
 | Schwerlast-Deckenprofil | yes | Trockenbauarbeiten | 0 | 1613Unz2005708408 | m³ | Unterzug | no | 0
 | Schwerlast-Deckenprofil | yes | Trockenbauarbeiten | 0 | 1613Unz2005708193 | m³ | Unterzug | no | 0
 | Schwerlast-Deckenprofil | yes | Trockenbauarbeiten | 0 | 1613Unz2005708629 | m³ | Unterzug | no | 0 | AllplanAttributes - Tragendes Bauteil: no
 | Schwerlast-Deckenprofil | yes | Trockenbauarbeiten | 0 | 1613Unz2005708625 | m³ | Unterzug | no | 0
 | Schwerlast-Deckenprofil | yes | Trockenbauarbeiten | 0 | 1613Unz2005708602 | m³ | Unterzug | no | 0
 | Schwerlast-Deckenprofil | yes | Trockenbauarbeiten | 0 | 1613Unz2005708570 | m³ | Unterzug | no | 0
 | Schwerlast-Deckenprofil | yes | Trockenbauarbeiten | 0 | 1613Unz2005708567 | m³ | Unterzug | no | 0
 | Schwerlast-Deckenprofil | yes | Trockenbauarbeiten | 0 | 1613Unz2005708565 | m³ | Unterzug | no | 0
 | Schwerlast-Deckenprofil | yes | Trockenbauarbeiten | 0 | 1613Unz2005708563 | m³ | Unterzug | no | 0
 | Schwerlast-Deckenprofil | yes | Trockenbauarbeiten | 0 | 1613Unz2005708561 | m³ | Unterzug | no | 0
 | Schwerlast-Deckenprofil | yes | Trockenbauarbeiten | 0 | 1613Unz2005708559 | m³ | Unterzug | no | 0
 | Schwerlast-Deckenprofil | yes | Trockenbauarbeiten | 0 | 1613Unz2005708557 | m³ | Unterzug | no | 0
 | Schwerlast-Deckenprofil | yes | Trockenbauarbeiten | 0 | 1613Unz2005708439 | m³ | Unterzug | no | 0
 | Schwerlast-Deckenprofil | yes | Trockenbauarbeiten | 0 | 1613Unz2005708437 | m³ | Unterzug | no | 0
 | Schwerlast-Deckenprofil | yes | Trockenbauarbeiten | 0 | 1613Unz2005708435 | m³ | Unterzug | no | 0
 | Schwerlast-Deckenprofil | yes | Trockenbauarbeiten | 0 | 1613Unz2005708433 | m³ | Unterzug | no | 0
 | Schwerlast-Deckenprofil | yes | Trockenbauarbeiten | 0 | 1613Unz2005708412 | m³ | Unterzug | no | 0
 | Schwerlast-Deckenprofil | yes | Trockenbauarbeiten | 0 | 1613Unz2005708410 | m³ | Unterzug | no | 0
 | Schwerlast-Deckenprofil | yes | Trockenbauarbeiten | 0 | 1613Unz2005708339 | m³ | Unterzug | no | 0
 | Schwerlast-Deckenprofil | yes | Trockenbauarbeiten | 0 | 1613Unz2005708335 | m³ | Unterzug | no | 0 | AllplanAttributes - Tragendes Bauteil: no
 | Schwerlast-Deckenprofil | yes | Trockenbauarbeiten | 0 | 1613Unz2005708296 | m³ | Unterzug | no | 0
 | Schwerlast-Deckenprofil | yes | Trockenbauarbeiten | 0 | 1613Unz2005708294 | m³ | Unterzug | no | 0
 | Schwerlast-Deckenprofil | yes | Trockenbauarbeiten | 0 | 1613Unz2005708292 | m³ | Unterzug | no | 0
 | Schwerlast-Deckenprofil | yes | Trockenbauarbeiten | 0 | 1613Unz2005708290 | m³ | Unterzug | no | 0
 | Schwerlast-Deckenprofil | yes | Trockenbauarbeiten | 0 | 1613Unz2005708268 | m³ | Unterzug | no | 0
 | Schwerlast-Deckenprofil | yes | Trockenbauarbeiten | 0 | 1613Unz2005708258 | m³ | Unterzug | no | 0
 | Schwerlast-Deckenprofil | yes | Trockenbauarbeiten | 0 | 1613Unz2005708256 | m³ | Unterzug | no | 0
 | Schwerlast-Deckenprofil | yes | Trockenbauarbeiten | 0 | 1613Unz2005708244 | m³ | Unterzug | no | 0
 | Schwerlast-Deckenprofil | yes | Trockenbauarbeiten | 0 | 1613Unz2005708242 | m³ | Unterzug | no | 0
 | Schwerlast-Deckenprofil | yes | Trockenbauarbeiten | 0 | 1613Unz2005708240 | m³ | Unterzug | no | 0
 | Schwerlast-Deckenprofil | yes | Trockenbauarbeiten | 0 | 1613Unz2005708191 | m³ | Unterzug | no | 0
 | Schwerlast-Deckenprofil | yes | Trockenbauarbeiten | 0 | 1613Unz2005708189 | m³ | Unterzug | no | 0
 | Schwerlast-Deckenprofil | yes | Trockenbauarbeiten | 0 | 1613Unz2005708165 | m³ | Unterzug | no | 0
 | Schwerlast-Deckenprofil | yes | Trockenbauarbeiten | 0 | 1613Unz2005708317 | m³ | Unterzug | no | 0
 | Schwerlast-Deckenprofil | yes | Trockenbauarbeiten | 0 | 1613Unz2005708319 | m³ | Unterzug | no | 0
 | Schwerlast-Deckenprofil | yes | Trockenbauarbeiten | 0 | 1613Unz2005708623 | m³ | Unterzug | no | 0
 | Schwerlast-Deckenprofil | yes | Trockenbauarbeiten | 0 | 1613Unz2005708315 | m³ | Unterzug | no | 0
 | Schwerlast-Deckenprofil | yes | Trockenbauarbeiten | 0 | 1613Unz2005708309 | m³ | Unterzug | no | 0
 | Schwerlast-Deckenprofil | yes | Trockenbauarbeiten | 0 | 1613Unz2005708307 | m³ | Unterzug | no | 0
 | Schwerlast-Deckenprofil | yes | Trockenbauarbeiten | 0 | 1613Unz2005708609 | m³ | Unterzug | no | 0 | AllplanAttributes - Tragendes Bauteil: no
 | Schwerlast-Deckenprofil | yes | Trockenbauarbeiten | 0 | 1613Unz2005708305 | m³ | Unterzug | no | 0
 | Schwerlast-Deckenprofil | yes | Trockenbauarbeiten | 0 | 1613Unz2005708303 | m³ | Unterzug | no | 0
 | Schwerlast-Deckenprofil | yes | Trockenbauarbeiten | 0 | 1613Unz2005708300 | m³ | Unterzug | no | 0
 | Schwerlast-Deckenprofil | yes | Trockenbauarbeiten | 0 | 1613Unz2005708298 | m³ | Unterzug | no | 0
 | Schwerlast-Deckenprofil | yes | Trockenbauarbeiten | 0 | 1613Unz2005708167 | m³ | Unterzug | no | 0
 | Schwerlast-Deckenprofil | yes | Trockenbauarbeiten | 0 | 1613Unz2005708169 | m³ | Unterzug | no | 0
 | Schwerlast-Deckenprofil | yes | Trockenbauarbeiten | 0 | 1613Unz2005708171 | m³ | Unterzug | no | 0
 |  |  |  |  | 1613Hbt2005711865 | m | Stahl-, Holzbauteil allgemein | AllplanAttributes - Schichtnummer: 1
 |  |  |  |  | 1613Hbt2005711868 | m | Stahl-, Holzbauteil allgemein | AllplanAttributes - Schichtnummer: 1
 |  |  |  |  | 1613Hbt2005711871 | m | Stahl-, Holzbauteil allgemein | AllplanAttributes - Schichtnummer: 1
 |  |  |  |  | 1613Hbt2005711874 | m | Stahl-, Holzbauteil allgemein | AllplanAttributes - Schichtnummer: 1
 |  |  |  |  | 1613Hbt2005711877 | m | Stahl-, Holzbauteil allgemein | AllplanAttributes - Schichtnummer: 1
 | Dachhaut | no | Betonarbeiten |  | 1614De 0000003114 | m³ | Decke | no | 0 | AllplanAttributes - Tragendes Bauteil: no; Pset_RoofCommon - FireRating: REI 90-A1
 | Dachhaut | no | Betonarbeiten |  | 1614De 0000003118 | m³ | Decke | no | 0 | AllplanAttributes - Tragendes Bauteil: no; Pset_RoofCommon - FireRating: REI 90-A1
 | Dachhaut | no | Betonarbeiten |  | 1614De 0000003155 | m³ | Decke | no | 0 | AllplanAttributes - Tragendes Bauteil: no; Pset_RoofCommon - FireRating: REI 90-A1
 | Dachhaut | no | Betonarbeiten |  | 1614De 0000002843 | m³ | Decke | no | 0 | AllplanAttributes - Tragendes Bauteil: no; Pset_RoofCommon - FireRating: REI 90-A1
 | Dachhaut | no | Betonarbeiten |  | 1614De 0000002838 | m³ | Decke | no | 0 | AllplanAttributes - Tragendes Bauteil: no; Pset_RoofCommon - FireRating: REI 90-A1
 | Dachhaut | no | Betonarbeiten |  | 1614De 0000002847 | m³ | Decke | no | 0 | AllplanAttributes - Tragendes Bauteil: no; Pset_RoofCommon - FireRating: REI 90-A1
 | Dachhaut | no | Betonarbeiten |  | 1614De 0000002851 | m³ | Decke | no | 0 | AllplanAttributes - Tragendes Bauteil: no; Pset_RoofCommon - FireRating: REI 90-A1
 | Dachhaut | no | Betonarbeiten |  | 1614De 0000003151 | m³ | Decke | no | 0 | AllplanAttributes - Tragendes Bauteil: no; Pset_RoofCommon - FireRating: REI 90-A1
 | Dachhaut | no | Betonarbeiten |  | 1614De 0000002832 | m³ | Decke | no | 0 | AllplanAttributes - Tragendes Bauteil: no; Pset_RoofCommon - FireRating: REI 90-A1

# IfcSlab (6)
AllplanAttributes - 2D Interaktion: yes; Abrechnungsart: m²
Pset_SlabCommon - Status: NEW
Name | In | PredefinedType | Material = AllplanAttributes, Material | Gewerk | Allright_Bauteil_ID | Objektname | ProductionYear = ThermalTransmittance (W/K/m2) | LoadBearing | IsExternal | FireRating | Combustible = Compartmentation
 | H1 Ebene +1 | FLOOR | H | Zimmer- und Holzbauarbeiten | 1614De 0000002712 | Decke | 0 | yes | no | - | no
 | H1 Ebene 0 | FLOOR | H | Zimmer- und Holzbauarbeiten | 1564De 0000004176 | Decke | 0 | yes | no | - | no
 | H1 Ebene 0 | FLOOR | H | Zimmer- und Holzbauarbeiten | 1564De 0000004170 | Decke | 0 | yes | no | - | no
 | H1 Ebene 0 | FLOOR | H | Zimmer- und Holzbauarbeiten | 1564De 0000004235 | Decke | 0 | yes | no | - | no
 | H1 Gründung | BASESLAB | STB | Betonarbeiten | 1512PFu0000001970 | Bodenplatte |  | yes | yes | AllplanAttributes - ash D_Detailverweis: BP; ash D_Plannummer: D1860
 | H1 Gründung | BASESLAB | BP-DE | Wärmedämm-Verbundsysteme | 1512PFu0000002019 | Plattenfundament | 0 | no | yes |  | no | AllplanAttributes - ash D_Detailverweis: BP; ash D_Plannummer: D1860

# IfcWall (252)
AllplanAttributes - 2D Interaktion: yes; Objektname: Wand
Pset_WallCommon - Status: NEW; FireRating: 0
Name | In | Material = AllplanAttributes, Material | Allright_Bauteil_ID | Codetext = Reference | Abrechnungsart | Gewerk | Bezeichnung | Typ = SurfaceSpreadOfFlame | Sicherheitsklasse | Brandschutzklasse | OKFF | Sonnenschutztyp | g-Wert | P_ID | LoadBearing | IsExternal | ThermalTransmittance (W/K/m2) | Combustible = Compartmentation | AcousticRating
 | H1 Ebene +1 | WA-LB | 1605Wa 0000068151 | Codetext | m² | Trockenbauarbeiten | Außenwand 7-Schalig | 0 | - | A | 3.75 | Movable | 0,51 | 1155HWa0000192367 | no | yes | 0.9 | no | 35
 | H1 Ebene +1 | WA-HD | 1605Wa 0000068154 | Codetext | m³ | Zimmer- und Holzbauarbeiten | Außenwand 7-Schalig | 0 | - | A | 3.75 | Movable | 0,51 | 1155HWa0000192367 | no | yes | 0.9 | no | 35 | AllplanAttributes - ash W_laufende Nr. Statik: 2 (W 2.0/ 2.1/ 2.2)
 | H1 Ebene +1 | WA-DL | 1605Wa 0000068149 | Codetext | m³ | Zimmer- und Holzbauarbeiten | Außenwand 7-Schalig | 0 | - | A | 3.75 | Movable | 0,51 | 1155HWa0000192367 | no | yes | 0.9 | no | 35
 | H1 Ebene +1 | WA-LB | 1605Wa 0000068158 | Codetext | m² | Trockenbauarbeiten | Außenwand 7-Schalig | 0 | - | A | 3.75 | Movable | 0,51 | 1155HWa0000192367 | no | yes | 0.9 | no | 35
 | H1 Ebene +1 | WA-KL | 1605Wa 0000068156 | Codetext | m² | Zimmer- und Holzbauarbeiten | Außenwand 7-Schalig | 0 | - | A | 3.75 | Movable | 0,51 | 1155HWa0000192367 | no | yes | 0.9 | no | 35
 | H1 Ebene +1 | WA-TL | 1605Wa 0000068166 | Codetext | m² | Zimmer- und Holzbauarbeiten | Außenwand 7-Schalig | 0 | - | A | 3.75 | Movable | 0,51 | 1155HWa0000192367 | no | yes | 0.9 | no | 35
 | H1 Ebene +1 | WA-HS | 1605Wa 0000068164 | Codetext | m² | Zimmer- und Holzbauarbeiten | Außenwand 7-Schalig | 0 | - | A | 3.75 | Movable | 0,51 | 1155HWa0000192367 | no | yes | 0.9 | no | 35
 | H1 Ebene +1 | WA-LB | 1605Wa 0000068147 | Codetext | m² | Trockenbauarbeiten | Außenwand 7-Schalig | 0 | - | A | 3.75 | Movable | 0,51 | 1155HWa0000192367 | no | yes | 0.9 | no | 35
 | H1 Ebene +1 | WA-HD | 1605Wa 0000068160 | Codetext | m³ | Zimmer- und Holzbauarbeiten | Außenwand 7-Schalig | 0 | - | A | 3.75 | Movable | 0,51 | 1155HWa0000192367 | no | yes | 0.9 | no | 35 | AllplanAttributes - ash W_laufende Nr. Statik: 2 (W 2.0/ 2.1/ 2.2)
 | H1 Ebene +1 | WA-DL | 1605Wa 0000068162 | Codetext | m³ | Zimmer- und Holzbauarbeiten | Außenwand 7-Schalig | 0 | - | A | 3.75 | Movable | 0,51 | 1155HWa0000192367 | no | yes | 0.9 | no | 35
 | H1 Ebene +1 | WA-LB | 1605Wa 0000068168 | Codetext | m² | Trockenbauarbeiten | Außenwand 7-Schalig | 0 | - | A | 3.75 | Movable | 0,51 | 1155HWa0000192367 | no | yes | 0.9 | no | 35
 | H1 Ebene +1 | WA-KL | 1605Wa 0000068170 | Codetext | m² | Zimmer- und Holzbauarbeiten | Außenwand 7-Schalig | 0 | - | A | 3.75 | Movable | 0,51 | 1155HWa0000192367 | no | yes | 0.9 | no | 35
 | H1 Ebene +1 | WA-TL | 1605Wa 0000068172 | Codetext | m² | Zimmer- und Holzbauarbeiten | Außenwand 7-Schalig | 0 | - | A | 3.75 | Movable | 0,51 | 1155HWa0000192367 | no | yes | 0.9 | no | 35
 | H1 Ebene +1 | WA-HS | 1605Wa 0000068174 | Codetext | m² | Zimmer- und Holzbauarbeiten | Außenwand 7-Schalig | 0 | - | A | 3.75 | Movable | 0,51 | 1155HWa0000192367 | no | yes | 0.9 | no | 35
 | H1 Ebene +1 | WA-LB | 1605Wa 0000068112 | Codetext | m² | Trockenbauarbeiten | Außenwand 7-Schalig | 0 | - | A | 3.75 | Movable | 0,51 | 1155HWa0000192367 | no | yes | 0.9 | no | 35
 | H1 Ebene +1 | WA-HD | 1605Wa 0000068103 | Codetext | m³ | Zimmer- und Holzbauarbeiten | Außenwand 7-Schalig | 0 | - | A | 3.75 | Movable | 0,51 | 1155HWa0000192367 | no | yes | 0.9 | no | 35 | AllplanAttributes - ash W_laufende Nr. Statik: 2 (W 2.0/ 2.1/ 2.2)
 | H1 Ebene +1 | WA-DL | 1605Wa 0000068101 | Codetext | m³ | Zimmer- und Holzbauarbeiten | Außenwand 7-Schalig | 0 | - | A | 3.75 | Movable | 0,51 | 1155HWa0000192367 | no | yes | 0.9 | no | 35
 | H1 Ebene +1 | WA-LB | 1605Wa 0000068099 | Codetext | m² | Trockenbauarbeiten | Außenwand 7-Schalig | 0 | - | A | 3.75 | Movable | 0,51 | 1155HWa0000192367 | no | yes | 0.9 | no | 35
 | H1 Ebene +1 | WA-KL | 1605Wa 0000068097 | Codetext | m² | Zimmer- und Holzbauarbeiten | Außenwand 7-Schalig | 0 | - | A | 3.75 | Movable | 0,51 | 1155HWa0000192367 | no | yes | 0.9 | no | 35
 | H1 Ebene +1 | WA-TL | 1605Wa 0000068095 | Codetext | m² | Zimmer- und Holzbauarbeiten | Außenwand 7-Schalig | 0 | - | A | 3.75 | Movable | 0,51 | 1155HWa0000192367 | no | yes | 0.9 | no | 35
 | H1 Ebene +1 | WA-HS | 1605Wa 0000068093 | Codetext | m² | Zimmer- und Holzbauarbeiten | Außenwand 7-Schalig | 0 | - | A | 3.75 | Movable | 0,51 | 1155HWa0000192367 | no | yes | 0.9 | no | 35
 | H1 Ebene +1 | WA-LB | 1605Wa 0000068057 | Codetext | m² | Trockenbauarbeiten | Außenwand 7-Schalig | 0 | - | A | 3.75 | Movable | 0,51 | 1155HWa0000192367 | no | yes | 0.9 | no | 35
 | H1 Ebene +1 | WA-HD | 1605Wa 0000068059 | Codetext | m³ | Zimmer- und Holzbauarbeiten | Außenwand 7-Schalig | 0 | - | A | 3.75 | Movable | 0,51 | 1155HWa0000192367 | no | yes | 0.9 | no | 35 | AllplanAttributes - ash W_laufende Nr. Statik: 2 (W 2.0/ 2.1/ 2.2)
 | H1 Ebene +1 | WA-DL | 1605Wa 0000068061 | Codetext | m³ | Zimmer- und Holzbauarbeiten | Außenwand 7-Schalig | 0 | - | A | 3.75 | Movable | 0,51 | 1155HWa0000192367 | no | yes | 0.9 | no | 35
 | H1 Ebene +1 | WA-LB | 1605Wa 0000068063 | Codetext | m² | Trockenbauarbeiten | Außenwand 7-Schalig | 0 | - | A | 3.75 | Movable | 0,51 | 1155HWa0000192367 | no | yes | 0.9 | no | 35
 | H1 Ebene +1 | WA-KL | 1605Wa 0000068065 | Codetext | m² | Zimmer- und Holzbauarbeiten | Außenwand 7-Schalig | 0 | - | A | 3.75 | Movable | 0,51 | 1155HWa0000192367 | no | yes | 0.9 | no | 35
 | H1 Ebene +1 | WA-TL | 1605Wa 0000068067 | Codetext | m² | Zimmer- und Holzbauarbeiten | Außenwand 7-Schalig | 0 | - | A | 3.75 | Movable | 0,51 | 1155HWa0000192367 | no | yes | 0.9 | no | 35
 | H1 Ebene +1 | WA-HS | 1605Wa 0000068069 | Codetext | m² | Zimmer- und Holzbauarbeiten | Außenwand 7-Schalig | 0 | - | A | 3.75 | Movable | 0,51 | 1155HWa0000192367 | no | yes | 0.9 | no | 35
 | H1 Ebene +1 | WA-LB | 1605Wa 0000068190 | Codetext | m² | Trockenbauarbeiten | Außenwand 7-Schalig | 0 | - | A | 3.75 | Movable | 0,51 | 1155HWa0000192367 | no | yes | 0.9 | no | 35
 | H1 Ebene +1 | WA-HD | 1605Wa 0000068183 | Codetext | m³ | Zimmer- und Holzbauarbeiten | Außenwand 7-Schalig | 0 | - | A | 3.75 | Movable | 0,51 | 1155HWa0000192367 | no | yes | 0.9 | no | 35 | AllplanAttributes - ash W_laufende Nr. Statik: 2 (W 2.0/ 2.1/ 2.2)
 | H1 Ebene +1 | WA-DL | 1605Wa 0000068194 | Codetext | m³ | Zimmer- und Holzbauarbeiten | Außenwand 7-Schalig | 0 | - | A | 3.75 | Movable | 0,51 | 1155HWa0000192367 | no | yes | 0.9 | no | 35
 | H1 Ebene +1 | WA-LB | 1605Wa 0000068196 | Codetext | m² | Trockenbauarbeiten | Außenwand 7-Schalig | 0 | - | A | 3.75 | Movable | 0,51 | 1155HWa0000192367 | no | yes | 0.9 | no | 35
 | H1 Ebene +1 | WA-KL | 1605Wa 0000068233 | Codetext | m² | Zimmer- und Holzbauarbeiten | Außenwand 7-Schalig | 0 | - | A | 3.75 | Movable | 0,51 | 1155HWa0000192367 | no | yes | 0.9 | no | 35
 | H1 Ebene +1 | WA-TL | 1605Wa 0000068231 | Codetext | m² | Zimmer- und Holzbauarbeiten | Außenwand 7-Schalig | 0 | - | A | 3.75 | Movable | 0,51 | 1155HWa0000192367 | no | yes | 0.9 | no | 35
 | H1 Ebene +1 | WA-HS | 1605Wa 0000068229 | Codetext | m² | Zimmer- und Holzbauarbeiten | Außenwand 7-Schalig | 0 | - | A | 3.75 | Movable | 0,51 | 1155HWa0000192367 | no | yes | 0.9 | no | 35
 | H1 Ebene +1 | WA-LB | 1605Wa 0000068178 | Codetext | m² | Trockenbauarbeiten | Außenwand 7-Schalig | 0 | - | A | 3.75 | Movable | 0,51 | 1155HWa0000192367 | no | yes | 0.9 | no | 35
 | H1 Ebene +1 | WA-HD | 1605Wa 0000068192 | Codetext | m³ | Zimmer- und Holzbauarbeiten | Außenwand 7-Schalig | 0 | - | A | 3.75 | Movable | 0,51 | 1155HWa0000192367 | no | yes | 0.9 | no | 35 | AllplanAttributes - ash W_laufende Nr. Statik: 2 (W 2.0/ 2.1/ 2.2)
 | H1 Ebene +1 | WA-DL | 1605Wa 0000068227 | Codetext | m³ | Zimmer- und Holzbauarbeiten | Außenwand 7-Schalig | 0 | - | A | 3.75 | Movable | 0,51 | 1155HWa0000192367 | no | yes | 0.9 | no | 35
 | H1 Ebene +1 | WA-LB | 1605Wa 0000068225 | Codetext | m² | Trockenbauarbeiten | Außenwand 7-Schalig | 0 | - | A | 3.75 | Movable | 0,51 | 1155HWa0000192367 | no | yes | 0.9 | no | 35
 | H1 Ebene +1 | WA-KL | 1605Wa 0000068223 | Codetext | m² | Zimmer- und Holzbauarbeiten | Außenwand 7-Schalig | 0 | - | A | 3.75 | Movable | 0,51 | 1155HWa0000192367 | no | yes | 0.9 | no | 35
 | H1 Ebene +1 | WA-TL | 1605Wa 0000068221 | Codetext | m² | Zimmer- und Holzbauarbeiten | Außenwand 7-Schalig | 0 | - | A | 3.75 | Movable | 0,51 | 1155HWa0000192367 | no | yes | 0.9 | no | 35
 | H1 Ebene +1 | WA-HS | 1605Wa 0000068219 | Codetext | m² | Zimmer- und Holzbauarbeiten | Außenwand 7-Schalig | 0 | - | A | 3.75 | Movable | 0,51 | 1155HWa0000192367 | no | yes | 0.9 | no | 35
 | H1 Ebene +1 | WA-LB | 1605Wa 0000068081 | Codetext | m² | Trockenbauarbeiten | Außenwand 7-Schalig | 0 | - | A | 3.75 | Movable | 0,51 | 1155HWa0000192367 | no | yes | 0.9 | no | 35
 | H1 Ebene +1 | WA-HD | 1605Wa 0000068071 | Codetext | m³ | Zimmer- und Holzbauarbeiten | Außenwand 7-Schalig | 0 | - | A | 3.75 | Movable | 0,51 | 1155HWa0000192367 | no | yes | 0.9 | no | 35 | AllplanAttributes - ash W_laufende Nr. Statik: 2 (W 2.0/ 2.1/ 2.2)
 | H1 Ebene +1 | WA-DL | 1605Wa 0000068083 | Codetext | m³ | Zimmer- und Holzbauarbeiten | Außenwand 7-Schalig | 0 | - | A | 3.75 | Movable | 0,51 | 1155HWa0000192367 | no | yes | 0.9 | no | 35
 | H1 Ebene +1 | WA-LB | 1605Wa 0000068085 | Codetext | m² | Trockenbauarbeiten | Außenwand 7-Schalig | 0 | - | A | 3.75 | Movable | 0,51 | 1155HWa0000192367 | no | yes | 0.9 | no | 35
 | H1 Ebene +1 | WA-KL | 1605Wa 0000068087 | Codetext | m² | Zimmer- und Holzbauarbeiten | Außenwand 7-Schalig | 0 | - | A | 3.75 | Movable | 0,51 | 1155HWa0000192367 | no | yes | 0.9 | no | 35
 | H1 Ebene +1 | WA-TL | 1605Wa 0000068089 | Codetext | m² | Zimmer- und Holzbauarbeiten | Außenwand 7-Schalig | 0 | - | A | 3.75 | Movable | 0,51 | 1155HWa0000192367 | no | yes | 0.9 | no | 35
 | H1 Ebene +1 | WA-HS | 1605Wa 0000068091 | Codetext | m² | Zimmer- und Holzbauarbeiten | Außenwand 7-Schalig | 0 | - | A | 3.75 | Movable | 0,51 | 1155HWa0000192367 | no | yes | 0.9 | no | 35
 | H1 Ebene +1 | WA-LB | 1605Wa 0000068137 | Codetext | m² | Trockenbauarbeiten | Außenwand 7-Schalig | 0 | - | A | 3.75 | Movable | 0,51 | 1155HWa0000192367 | no | yes | 0.9 | no | 35
 | H1 Ebene +1 | WA-HD | 1605Wa 0000068118 | Codetext | m³ | Zimmer- und Holzbauarbeiten | Außenwand 7-Schalig | 0 | - | A | 3.75 | Movable | 0,51 | 1155HWa0000192367 | no | yes | 0.9 | no | 35 | AllplanAttributes - ash W_laufende Nr. Statik: 2 (W 2.0/ 2.1/ 2.2)
 | H1 Ebene +1 | WA-DL | 1605Wa 0000068128 | Codetext | m³ | Zimmer- und Holzbauarbeiten | Außenwand 7-Schalig | 0 | - | A | 3.75 | Movable | 0,51 | 1155HWa0000192367 | no | yes | 0.9 | no | 35
 | H1 Ebene +1 | WA-LB | 1605Wa 0000068120 | Codetext | m² | Trockenbauarbeiten | Außenwand 7-Schalig | 0 | - | A | 3.75 | Movable | 0,51 | 1155HWa0000192367 | no | yes | 0.9 | no | 35
 | H1 Ebene +1 | WA-KL | 1605Wa 0000068122 | Codetext | m² | Zimmer- und Holzbauarbeiten | Außenwand 7-Schalig | 0 | - | A | 3.75 | Movable | 0,51 | 1155HWa0000192367 | no | yes | 0.9 | no | 35
 | H1 Ebene +1 | WA-TL | 1605Wa 0000068124 | Codetext | m² | Zimmer- und Holzbauarbeiten | Außenwand 7-Schalig | 0 | - | A | 3.75 | Movable | 0,51 | 1155HWa0000192367 | no | yes | 0.9 | no | 35
 | H1 Ebene +1 | WA-HS | 1605Wa 0000068126 | Codetext | m² | Zimmer- und Holzbauarbeiten | Außenwand 7-Schalig | 0 | - | A | 3.75 | Movable | 0,51 | 1155HWa0000192367 | no | yes | 0.9 | no | 35
 | H1 Ebene +1 | WA-LB | 1605Wa 0000068202 | Codetext | m² | Trockenbauarbeiten | Außenwand 7-Schalig | 0 | - | A | 3.75 | Movable | 0,51 | 1155HWa0000192367 | no | yes | 0.9 | no | 35
 | H1 Ebene +1 | WA-HD | 1605Wa 0000068205 | Codetext | m³ | Zimmer- und Holzbauarbeiten | Außenwand 7-Schalig | 0 | - | A | 3.75 | Movable | 0,51 | 1155HWa0000192367 | no | yes | 0.9 | no | 35 | AllplanAttributes - ash W_laufende Nr. Statik: 2 (W 2.0/ 2.1/ 2.2)
 | H1 Ebene +1 | WA-DL | 1605Wa 0000068213 | Codetext | m³ | Zimmer- und Holzbauarbeiten | Außenwand 7-Schalig | 0 | - | A | 3.75 | Movable | 0,51 | 1155HWa0000192367 | no | yes | 0.9 | no | 35
 | H1 Ebene +1 | WA-LB | 1605Wa 0000068215 | Codetext | m² | Trockenbauarbeiten | Außenwand 7-Schalig | 0 | - | A | 3.75 | Movable | 0,51 | 1155HWa0000192367 | no | yes | 0.9 | no | 35
 | H1 Ebene +1 | WA-KL | 1605Wa 0000068207 | Codetext | m² | Zimmer- und Holzbauarbeiten | Außenwand 7-Schalig | 0 | - | A | 3.75 | Movable | 0,51 | 1155HWa0000192367 | no | yes | 0.9 | no | 35
 | H1 Ebene +1 | WA-TL | 1605Wa 0000068209 | Codetext | m² | Zimmer- und Holzbauarbeiten | Außenwand 7-Schalig | 0 | - | A | 3.75 | Movable | 0,51 | 1155HWa0000192367 | no | yes | 0.9 | no | 35
 | H1 Ebene +1 | WA-HS | 1605Wa 0000068211 | Codetext | m² | Zimmer- und Holzbauarbeiten | Außenwand 7-Schalig | 0 | - | A | 3.75 | Movable | 0,51 | 1155HWa0000192367 | no | yes | 0.9 | no | 35
 | H1 Ebene +1 | WA-LB | 1605Wa 0000068051 | Codetext | m² | Trockenbauarbeiten | Außenwand 7-Schalig | 0 | - | A | 3.75 | Movable | 0,51 | 1155HWa0000192367 | no | yes | 0.9 | no | 35
 | H1 Ebene +1 | WA-HD | 1605Wa 0000068045 | Codetext | m³ | Zimmer- und Holzbauarbeiten | Außenwand 7-Schalig | 0 | - | A | 3.75 | Movable | 0,51 | 1155HWa0000192367 | no | yes | 0.9 | no | 35 | AllplanAttributes - ash W_laufende Nr. Statik: 2 (W 2.0/ 2.1/ 2.2)
 | H1 Ebene +1 | WA-DL | 1605Wa 0000068039 | Codetext | m³ | Zimmer- und Holzbauarbeiten | Außenwand 7-Schalig | 0 | - | A | 3.75 | Movable | 0,51 | 1155HWa0000192367 | no | yes | 0.9 | no | 35
 | H1 Ebene +1 | WA-LB | 1605Wa 0000068139 | Codetext | m² | Trockenbauarbeiten | Außenwand 7-Schalig | 0 | - | A | 3.75 | Movable | 0,51 | 1155HWa0000192367 | no | yes | 0.9 | no | 35
 | H1 Ebene +1 | WA-KL | 1605Wa 0000068141 | Codetext | m² | Zimmer- und Holzbauarbeiten | Außenwand 7-Schalig | 0 | - | A | 3.75 | Movable | 0,51 | 1155HWa0000192367 | no | yes | 0.9 | no | 35
 | H1 Ebene +1 | WA-TL | 1605Wa 0000068143 | Codetext | m² | Zimmer- und Holzbauarbeiten | Außenwand 7-Schalig | 0 | - | A | 3.75 | Movable | 0,51 | 1155HWa0000192367 | no | yes | 0.9 | no | 35
 | H1 Ebene +1 | WA-HS | 1605Wa 0000068145 | Codetext | m² | Zimmer- und Holzbauarbeiten | Außenwand 7-Schalig | 0 | - | A | 3.75 | Movable | 0,51 | 1155HWa0000192367 | no | yes | 0.9 | no | 35
 | H1 Ebene +1 | WI-LB | 1613Wa 2005707917 |  | m² | Trockenbauarbeiten | Innenwand 1-Schalig |  | - |  | 0 |  |  | 1113HWa0812440867 |  |  |  |  | 0 | AllplanAttributes - W_Deckenanschluss: Gleitender Deckenanschluss Fall 01; ash_W_Trockenbau_Qualitäten: 1b
 | H1 Ebene +1 | WI-LB | 1613Wa 2005708351 |  | m² | Trockenbauarbeiten | Innenwand 1-Schalig |  | - |  | 0 |  |  | 1113HWa0812440867 |  |  |  |  | 0 | AllplanAttributes - W_Deckenanschluss: Gleitender Deckenanschluss Fall 01; ash_W_Trockenbau_Qualitäten: 1b
 | H1 Ebene +1 | WI-LB | 1613Wa 2005707919 |  | m² | Trockenbauarbeiten | Innenwand 1-Schalig |  | - |  | 0 |  |  | 1113HWa0812440867 |  |  |  |  | 0 | AllplanAttributes - W_Deckenanschluss: Gleitender Deckenanschluss Fall 01; ash_W_Trockenbau_Qualitäten: 1b
 | H1 Ebene +1 | WI-LB | 1613Wa 2005707937 |  | m² | Trockenbauarbeiten | Innenwand 1-Schalig |  | - |  | 0 |  |  | 1113HWa0812440867 |  |  |  |  | 0 | AllplanAttributes - W_Deckenanschluss: Gleitender Deckenanschluss Fall 01; ash_W_Trockenbau_Qualitäten: 1b
 | H1 Ebene +1 | WI-LB | 1613Wa 2005707921 |  | m² | Trockenbauarbeiten | Innenwand 1-Schalig |  | - |  | 0 |  |  | 1113HWa0812440867 |  |  |  |  | 0 | AllplanAttributes - W_Deckenanschluss: Gleitender Deckenanschluss Fall 01; ash_W_Trockenbau_Qualitäten: 1b
 | H1 Ebene +1 | WI-LB | 1613Wa 2005707926 |  | m² | Trockenbauarbeiten | Innenwand 1-Schalig |  | - |  | 0 |  |  | 1113HWa0812440867 |  |  |  |  | 0 | AllplanAttributes - W_Deckenanschluss: Gleitender Deckenanschluss Fall 01; ash_W_Trockenbau_Qualitäten: 1b
 | H1 Ebene +1 | WI-LB | 1613Wa 2005708374 |  | m² | Trockenbauarbeiten | Innenwand 1-Schalig |  | - |  | 0 |  |  | 1113HWa0812440867 | no |  |  |  | 0 | AllplanAttributes - W_Deckenanschluss: Gleitender Deckenanschluss Fall 01; ash_W_Trockenbau_Qualitäten: 1b
 | H1 Ebene +1 | WI-HW 60 | 1613Wa 2005708382 |  | m² | Zimmer- und Holzbauarbeiten | Innenwand 1-Schalig |  | - |  | 0 |  |  | 1113HWa0812443023 | no |  |  |  | 47
 | H1 Ebene +1 | WI-HW 60 | 1613Wa 2005711601 |  | m² | Zimmer- und Holzbauarbeiten | Innenwand 1-Schalig |  | - |  | 0 |  |  | 1113HWa0812443023 | no |  |  |  | 47
 | H1 Ebene +1 | WA-LB | 1614Wa 0000002739 | Codetext | m² | Trockenbauarbeiten | Außenwand 7-Schalig | 0 | - | A | 3.75 | Movable | 0,51 | 1155HWa0000192367 | no | yes | 0.9 | no | 35
 | H1 Ebene +1 | WA-HD | 1614Wa 0000002740 | Codetext | m³ | Zimmer- und Holzbauarbeiten | Außenwand 7-Schalig | 0 | - | A | 3.75 | Movable | 0,51 | 1155HWa0000192367 | no | yes | 0.9 | no | 35 | AllplanAttributes - ash W_laufende Nr. Statik: 2 (W 2.0/ 2.1/ 2.2)
 | H1 Ebene +1 | WA-DL | 1614Wa 0000002741 | Codetext | m³ | Zimmer- und Holzbauarbeiten | Außenwand 7-Schalig | 0 | - | A | 3.75 | Movable | 0,51 | 1155HWa0000192367 | no | yes | 0.9 | no | 35
 | H1 Ebene +1 | WA-LB | 1614Wa 0000002742 | Codetext | m² | Trockenbauarbeiten | Außenwand 7-Schalig | 0 | - | A | 3.75 | Movable | 0,51 | 1155HWa0000192367 | no | yes | 0.9 | no | 35
 | H1 Ebene +1 | WA-KL | 1614Wa 0000002743 | Codetext | m² | Zimmer- und Holzbauarbeiten | Außenwand 7-Schalig | 0 | - | A | 3.75 | Movable | 0,51 | 1155HWa0000192367 | no | yes | 0.9 | no | 35
 | H1 Ebene +1 | WA-TL | 1614Wa 0000002744 | Codetext | m² | Zimmer- und Holzbauarbeiten | Außenwand 7-Schalig | 0 | - | A | 3.75 | Movable | 0,51 | 1155HWa0000192367 | no | yes | 0.9 | no | 35
 | H1 Ebene +1 | WA-HS | 1614Wa 0000002745 | Codetext | m² | Zimmer- und Holzbauarbeiten | Außenwand 7-Schalig | 0 | - | A | 3.75 | Movable | 0,51 | 1155HWa0000192367 | no | yes | 0.9 | no | 35
 | H1 Ebene 0 | WA-LB | 1555Wa 0811452376 | Codetext | m² | Trockenbauarbeiten | Außenwand 7-Schalig | 0 | - | A | 3.75 | Movable | 0,51 | 1155HWa0000192367 | no | yes | 0.9 | no | 35
 | H1 Ebene 0 | WA-HD | 1555Wa 0811452375 | Codetext | m³ | Zimmer- und Holzbauarbeiten | Außenwand 7-Schalig | 0 | - | A | 3.75 | Movable | 0,51 | 1155HWa0000192367 | no | yes | 0.9 | no | 35 | AllplanAttributes - ash W_laufende Nr. Statik: 2 (W 2.0/ 2.1/ 2.2)
 | H1 Ebene 0 | WA-DL | 1555Wa 0811452374 | Codetext | m³ | Zimmer- und Holzbauarbeiten | Außenwand 7-Schalig | 0 | - | A | 3.75 | Movable | 0,51 | 1155HWa0000192367 | no | yes | 0.9 | no | 35
 | H1 Ebene 0 | WA-LB | 1555Wa 0811452370 | Codetext | m² | Trockenbauarbeiten | Außenwand 7-Schalig | 0 | - | A | 3.75 | Movable | 0,51 | 1155HWa0000192367 | no | yes | 0.9 | no | 35
 | H1 Ebene 0 | WA-KL | 1555Wa 0811452371 | Codetext | m² | Zimmer- und Holzbauarbeiten | Außenwand 7-Schalig | 0 | - | A | 3.75 | Movable | 0,51 | 1155HWa0000192367 | no | yes | 0.9 | no | 35
 | H1 Ebene 0 | WA-TL | 1555Wa 0811452372 | Codetext | m² | Zimmer- und Holzbauarbeiten | Außenwand 7-Schalig | 0 | - | A | 3.75 | Movable | 0,51 | 1155HWa0000192367 | no | yes | 0.9 | no | 35
 | H1 Ebene 0 | WA-HS | 1555Wa 0811452373 | Codetext | m² | Zimmer- und Holzbauarbeiten | Außenwand 7-Schalig | 0 | - | A | 3.75 | Movable | 0,51 | 1155HWa0000192367 | no | yes | 0.9 | no | 35
 | H1 Ebene 0 | WA-LB | 1555Wa 0811452385 | Codetext | m² | Trockenbauarbeiten | Außenwand 7-Schalig | 0 | - | A | 3.75 | Movable | 0,51 | 1155HWa0000192367 | no | yes | 0.9 | no | 35
 | H1 Ebene 0 | WA-HD | 1555Wa 0811452386 | Codetext | m³ | Zimmer- und Holzbauarbeiten | Außenwand 7-Schalig | 0 | - | A | 3.75 | Movable | 0,51 | 1155HWa0000192367 | no | yes | 0.9 | no | 35 | AllplanAttributes - ash W_laufende Nr. Statik: 2 (W 2.0/ 2.1/ 2.2)
 | H1 Ebene 0 | WA-DL | 1555Wa 0811452391 | Codetext | m³ | Zimmer- und Holzbauarbeiten | Außenwand 7-Schalig | 0 | - | A | 3.75 | Movable | 0,51 | 1155HWa0000192367 | no | yes | 0.9 | no | 35
 | H1 Ebene 0 | WA-LB | 1555Wa 0811452390 | Codetext | m² | Trockenbauarbeiten | Außenwand 7-Schalig | 0 | - | A | 3.75 | Movable | 0,51 | 1155HWa0000192367 | no | yes | 0.9 | no | 35
 | H1 Ebene 0 | WA-KL | 1555Wa 0811452389 | Codetext | m² | Zimmer- und Holzbauarbeiten | Außenwand 7-Schalig | 0 | - | A | 3.75 | Movable | 0,51 | 1155HWa0000192367 | no | yes | 0.9 | no | 35
 | H1 Ebene 0 | WA-TL | 1555Wa 0811452388 | Codetext | m² | Zimmer- und Holzbauarbeiten | Außenwand 7-Schalig | 0 | - | A | 3.75 | Movable | 0,51 | 1155HWa0000192367 | no | yes | 0.9 | no | 35
 | H1 Ebene 0 | WA-HS | 1555Wa 0811452387 | Codetext | m² | Zimmer- und Holzbauarbeiten | Außenwand 7-Schalig | 0 | - | A | 3.75 | Movable | 0,51 | 1155HWa0000192367 | no | yes | 0.9 | no | 35
 | H1 Ebene 0 | WA-LB | 1555Wa 0811452384 | Codetext | m² | Trockenbauarbeiten | Außenwand 7-Schalig | 0 | - | A | 3.75 | Movable | 0,51 | 1155HWa0000192367 | no | yes | 0.9 | no | 35
 | H1 Ebene 0 | WA-HD | 1555Wa 0811452395 | Codetext | m³ | Zimmer- und Holzbauarbeiten | Außenwand 7-Schalig | 0 | - | A | 3.75 | Movable | 0,51 | 1155HWa0000192367 | no | yes | 0.9 | no | 35 | AllplanAttributes - ash W_laufende Nr. Statik: 2 (W 2.0/ 2.1/ 2.2)
 | H1 Ebene 0 | WA-DL | 1555Wa 0811452392 | Codetext | m³ | Zimmer- und Holzbauarbeiten | Außenwand 7-Schalig | 0 | - | A | 3.75 | Movable | 0,51 | 1155HWa0000192367 | no | yes | 0.9 | no | 35
 | H1 Ebene 0 | WA-LB | 1555Wa 0811452397 | Codetext | m² | Trockenbauarbeiten | Außenwand 7-Schalig | 0 | - | A | 3.75 | Movable | 0,51 | 1155HWa0000192367 | no | yes | 0.9 | no | 35
 | H1 Ebene 0 | WA-KL | 1555Wa 0811452393 | Codetext | m² | Zimmer- und Holzbauarbeiten | Außenwand 7-Schalig | 0 | - | A | 3.75 | Movable | 0,51 | 1155HWa0000192367 | no | yes | 0.9 | no | 35
 | H1 Ebene 0 | WA-TL | 1555Wa 0811452396 | Codetext | m² | Zimmer- und Holzbauarbeiten | Außenwand 7-Schalig | 0 | - | A | 3.75 | Movable | 0,51 | 1155HWa0000192367 | no | yes | 0.9 | no | 35
 | H1 Ebene 0 | WA-HS | 1555Wa 0811452394 | Codetext | m² | Zimmer- und Holzbauarbeiten | Außenwand 7-Schalig | 0 | - | A | 3.75 | Movable | 0,51 | 1155HWa0000192367 | no | yes | 0.9 | no | 35
 | H1 Ebene 0 | WA-LB | 1555Wa 0811452363 | Codetext | m² | Trockenbauarbeiten | Außenwand 7-Schalig | 0 | - | A | 3.75 | Movable | 0,51 | 1155HWa0000192367 | no | yes | 0.9 | no | 35
 | H1 Ebene 0 | WA-HD | 1555Wa 0811452369 | Codetext | m³ | Zimmer- und Holzbauarbeiten | Außenwand 7-Schalig | 0 | - | A | 3.75 | Movable | 0,51 | 1155HWa0000192367 | no | yes | 0.9 | no | 35 | AllplanAttributes - ash W_laufende Nr. Statik: 2 (W 2.0/ 2.1/ 2.2)
 | H1 Ebene 0 | WA-DL | 1555Wa 0811452368 | Codetext | m³ | Zimmer- und Holzbauarbeiten | Außenwand 7-Schalig | 0 | - | A | 3.75 | Movable | 0,51 | 1155HWa0000192367 | no | yes | 0.9 | no | 35
 | H1 Ebene 0 | WA-LB | 1555Wa 0811452367 | Codetext | m² | Trockenbauarbeiten | Außenwand 7-Schalig | 0 | - | A | 3.75 | Movable | 0,51 | 1155HWa0000192367 | no | yes | 0.9 | no | 35
 | H1 Ebene 0 | WA-KL | 1555Wa 0811452364 | Codetext | m² | Zimmer- und Holzbauarbeiten | Außenwand 7-Schalig | 0 | - | A | 3.75 | Movable | 0,51 | 1155HWa0000192367 | no | yes | 0.9 | no | 35
 | H1 Ebene 0 | WA-TL | 1555Wa 0811452365 | Codetext | m² | Zimmer- und Holzbauarbeiten | Außenwand 7-Schalig | 0 | - | A | 3.75 | Movable | 0,51 | 1155HWa0000192367 | no | yes | 0.9 | no | 35
 | H1 Ebene 0 | WA-HS | 1555Wa 0811452366 | Codetext | m² | Zimmer- und Holzbauarbeiten | Außenwand 7-Schalig | 0 | - | A | 3.75 | Movable | 0,51 | 1155HWa0000192367 | no | yes | 0.9 | no | 35
 | H1 Ebene 0 | WA-LB | 1555Wa 0811456278 | Codetext | m² | Trockenbauarbeiten | Außenwand 7-Schalig | 0 | - | A | 3.75 | Movable | 0,51 | 1155HWa0000192367 | no | yes | 0.9 | no | 35
 | H1 Ebene 0 | WA-HD | 1555Wa 0811456277 | Codetext | m³ | Zimmer- und Holzbauarbeiten | Außenwand 7-Schalig | 0 | - | A | 3.75 | Movable | 0,51 | 1155HWa0000192367 | no | yes | 0.9 | no | 35 | AllplanAttributes - ash W_laufende Nr. Statik: 2 (W 2.0/ 2.1/ 2.2)
 | H1 Ebene 0 | WA-DL | 1555Wa 0811456276 | Codetext | m³ | Zimmer- und Holzbauarbeiten | Außenwand 7-Schalig | 0 | - | A | 3.75 | Movable | 0,51 | 1155HWa0000192367 | no | yes | 0.9 | no | 35
 | H1 Ebene 0 | WA-LB | 1555Wa 0811456275 | Codetext | m² | Trockenbauarbeiten | Außenwand 7-Schalig | 0 | - | A | 3.75 | Movable | 0,51 | 1155HWa0000192367 | no | yes | 0.9 | no | 35
 | H1 Ebene 0 | WA-KL | 1555Wa 0811456274 | Codetext | m² | Zimmer- und Holzbauarbeiten | Außenwand 7-Schalig | 0 | - | A | 3.75 | Movable | 0,51 | 1155HWa0000192367 | no | yes | 0.9 | no | 35
 | H1 Ebene 0 | WA-TL | 1555Wa 0811456273 | Codetext | m² | Zimmer- und Holzbauarbeiten | Außenwand 7-Schalig | 0 | - | A | 3.75 | Movable | 0,51 | 1155HWa0000192367 | no | yes | 0.9 | no | 35
 | H1 Ebene 0 | WA-HS | 1555Wa 0811456272 | Codetext | m² | Zimmer- und Holzbauarbeiten | Außenwand 7-Schalig | 0 | - | A | 3.75 | Movable | 0,51 | 1155HWa0000192367 | no | yes | 0.9 | no | 35
 | H1 Ebene 0 | WA-HS | 1555Wa 0811452408 |  | m² | Trockenbauarbeiten | Installationswand |  | - |  | 0 |  |  | 1113HWa0814145504 | no |  |  |  | 0 | AllplanAttributes - W_Deckenanschluss: Gleitender Deckenanschluss Fall 01; ash_W_Trockenbau_Qualitäten: 2
 | H1 Ebene 0 | WA-HS | 1555Wa 0811452409 |  | m² | Trockenbauarbeiten | Installationswand |  | - |  | 0 |  |  | 1113HWa0814145504 | no |  |  |  | 0 | AllplanAttributes - W_Deckenanschluss: Gleitender Deckenanschluss Fall 01; ash_W_Trockenbau_Qualitäten: 2
 | H1 Ebene 0 | WA-LB | 1555Wa 0811452341 | Codetext | m² | Trockenbauarbeiten | Außenwand 7-Schalig | 0 | - | A | 3.75 | Movable | 0,51 | 1155HWa0000192367 | no | yes | 0.9 | no | 35
 | H1 Ebene 0 | WA-HD | 1555Wa 0811452340 | Codetext | m³ | Zimmer- und Holzbauarbeiten | Außenwand 7-Schalig | 0 | - | A | 3.75 | Movable | 0,51 | 1155HWa0000192367 | no | yes | 0.9 | no | 35 | AllplanAttributes - ash W_laufende Nr. Statik: 2 (W 2.0/ 2.1/ 2.2)
 | H1 Ebene 0 | WA-DL | 1555Wa 0811452339 | Codetext | m³ | Zimmer- und Holzbauarbeiten | Außenwand 7-Schalig | 0 | - | A | 3.75 | Movable | 0,51 | 1155HWa0000192367 | no | yes | 0.9 | no | 35
 | H1 Ebene 0 | WA-LB | 1555Wa 0811452338 | Codetext | m² | Trockenbauarbeiten | Außenwand 7-Schalig | 0 | - | A | 3.75 | Movable | 0,51 | 1155HWa0000192367 | no | yes | 0.9 | no | 35
 | H1 Ebene 0 | WA-KL | 1555Wa 0811452337 | Codetext | m² | Zimmer- und Holzbauarbeiten | Außenwand 7-Schalig | 0 | - | A | 3.75 | Movable | 0,51 | 1155HWa0000192367 | no | yes | 0.9 | no | 35
 | H1 Ebene 0 | WA-TL | 1555Wa 0811452336 | Codetext | m² | Zimmer- und Holzbauarbeiten | Außenwand 7-Schalig | 0 | - | A | 3.75 | Movable | 0,51 | 1155HWa0000192367 | no | yes | 0.9 | no | 35
 | H1 Ebene 0 | WA-HS | 1555Wa 0811452335 | Codetext | m² | Zimmer- und Holzbauarbeiten | Außenwand 7-Schalig | 0 | - | A | 3.75 | Movable | 0,51 | 1155HWa0000192367 | no | yes | 0.9 | no | 35
 | H1 Ebene 0 | WA-LB | 1555Wa 0811452377 | Codetext | m² | Trockenbauarbeiten | Außenwand 7-Schalig | 0 | - | A | 3.75 | Movable | 0,51 | 1155HWa0000192367 | no | yes | 0.9 | no | 35
 | H1 Ebene 0 | WA-HD | 1555Wa 0811452378 | Codetext | m³ | Zimmer- und Holzbauarbeiten | Außenwand 7-Schalig | 0 | - | A | 3.75 | Movable | 0,51 | 1155HWa0000192367 | no | yes | 0.9 | no | 35 | AllplanAttributes - ash W_laufende Nr. Statik: 2 (W 2.0/ 2.1/ 2.2)
 | H1 Ebene 0 | WA-DL | 1555Wa 0811452383 | Codetext | m³ | Zimmer- und Holzbauarbeiten | Außenwand 7-Schalig | 0 | - | A | 3.75 | Movable | 0,51 | 1155HWa0000192367 | no | yes | 0.9 | no | 35
 | H1 Ebene 0 | WA-LB | 1555Wa 0811452382 | Codetext | m² | Trockenbauarbeiten | Außenwand 7-Schalig | 0 | - | A | 3.75 | Movable | 0,51 | 1155HWa0000192367 | no | yes | 0.9 | no | 35
 | H1 Ebene 0 | WA-KL | 1555Wa 0811452381 | Codetext | m² | Zimmer- und Holzbauarbeiten | Außenwand 7-Schalig | 0 | - | A | 3.75 | Movable | 0,51 | 1155HWa0000192367 | no | yes | 0.9 | no | 35
 | H1 Ebene 0 | WA-TL | 1555Wa 0811452380 | Codetext | m² | Zimmer- und Holzbauarbeiten | Außenwand 7-Schalig | 0 | - | A | 3.75 | Movable | 0,51 | 1155HWa0000192367 | no | yes | 0.9 | no | 35
 | H1 Ebene 0 | WA-HS | 1555Wa 0811452379 | Codetext | m² | Zimmer- und Holzbauarbeiten | Außenwand 7-Schalig | 0 | - | A | 3.75 | Movable | 0,51 | 1155HWa0000192367 | no | yes | 0.9 | no | 35
 | H1 Ebene 0 | WA-LB | 1555Wa 0811452346 | Codetext | m² | Trockenbauarbeiten | Außenwand 7-Schalig | 0 | - | A | 3.75 | Movable | 0,51 | 1155HWa0000192367 | no | yes | 0.9 | no | 35
 | H1 Ebene 0 | WA-HD | 1555Wa 0811452347 | Codetext | m³ | Zimmer- und Holzbauarbeiten | Außenwand 7-Schalig | 0 | - | A | 3.75 | Movable | 0,51 | 1155HWa0000192367 | no | yes | 0.9 | no | 35 | AllplanAttributes - ash W_laufende Nr. Statik: 2 (W 2.0/ 2.1/ 2.2)
 | H1 Ebene 0 | WA-DL | 1555Wa 0811452348 | Codetext | m³ | Zimmer- und Holzbauarbeiten | Außenwand 7-Schalig | 0 | - | A | 3.75 | Movable | 0,51 | 1155HWa0000192367 | no | yes | 0.9 | no | 35
 | H1 Ebene 0 | WA-LB | 1555Wa 0811452349 | Codetext | m² | Trockenbauarbeiten | Außenwand 7-Schalig | 0 | - | A | 3.75 | Movable | 0,51 | 1155HWa0000192367 | no | yes | 0.9 | no | 35
 | H1 Ebene 0 | WA-KL | 1555Wa 0811452350 | Codetext | m² | Zimmer- und Holzbauarbeiten | Außenwand 7-Schalig | 0 | - | A | 3.75 | Movable | 0,51 | 1155HWa0000192367 | no | yes | 0.9 | no | 35
 | H1 Ebene 0 | WA-TL | 1555Wa 0811452351 | Codetext | m² | Zimmer- und Holzbauarbeiten | Außenwand 7-Schalig | 0 | - | A | 3.75 | Movable | 0,51 | 1155HWa0000192367 | no | yes | 0.9 | no | 35
 | H1 Ebene 0 | WA-HS | 1555Wa 0811452352 | Codetext | m² | Zimmer- und Holzbauarbeiten | Außenwand 7-Schalig | 0 | - | A | 3.75 | Movable | 0,51 | 1155HWa0000192367 | no | yes | 0.9 | no | 35
 | H1 Ebene 0 | WA-LB | 1555Wa 0811452342 | Codetext | m² | Trockenbauarbeiten | Außenwand 7-Schalig | 0 | - | A | 3.75 | Movable | 0,51 | 1155HWa0000192367 | no | yes | 0.9 | no | 35
 | H1 Ebene 0 | WA-HD | 1555Wa 0811452343 | Codetext | m³ | Zimmer- und Holzbauarbeiten | Außenwand 7-Schalig | 0 | - | A | 3.75 | Movable | 0,51 | 1155HWa0000192367 | no | yes | 0.9 | no | 35 | AllplanAttributes - ash W_laufende Nr. Statik: 2 (W 2.0/ 2.1/ 2.2)
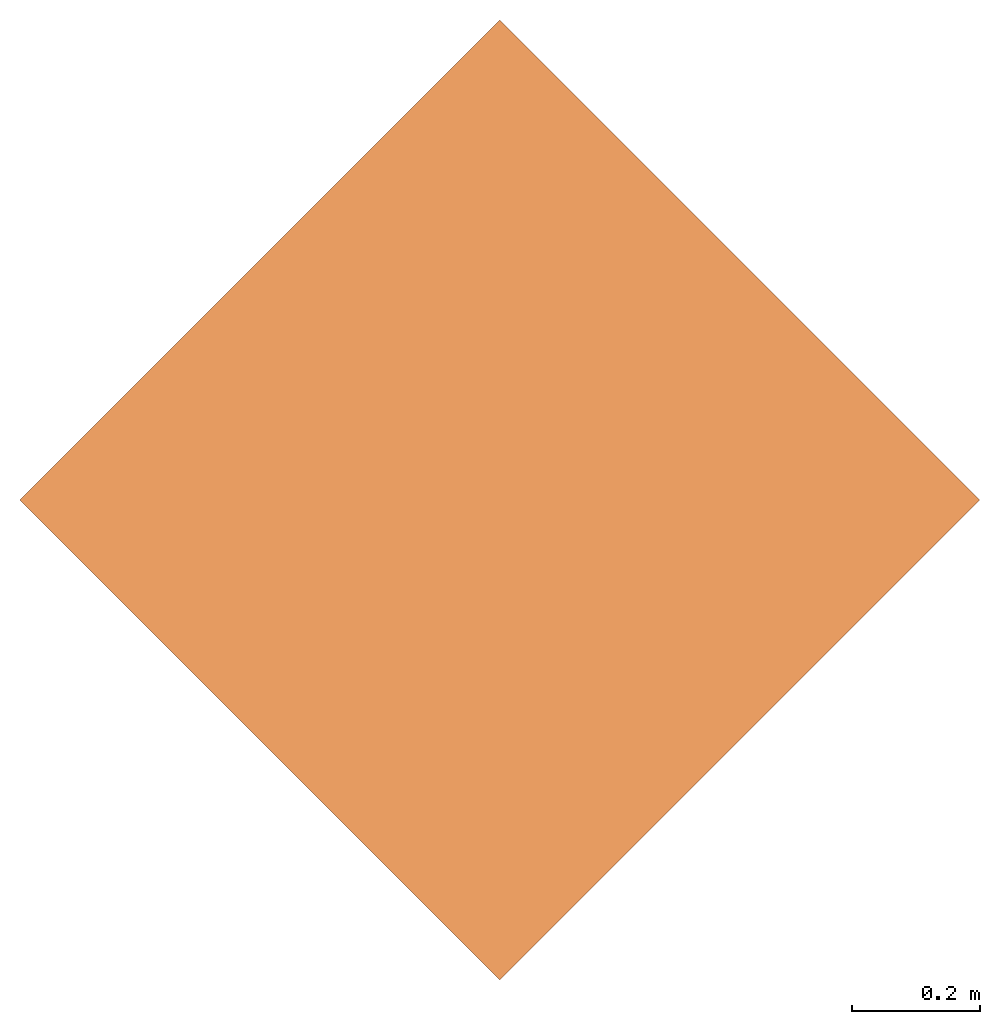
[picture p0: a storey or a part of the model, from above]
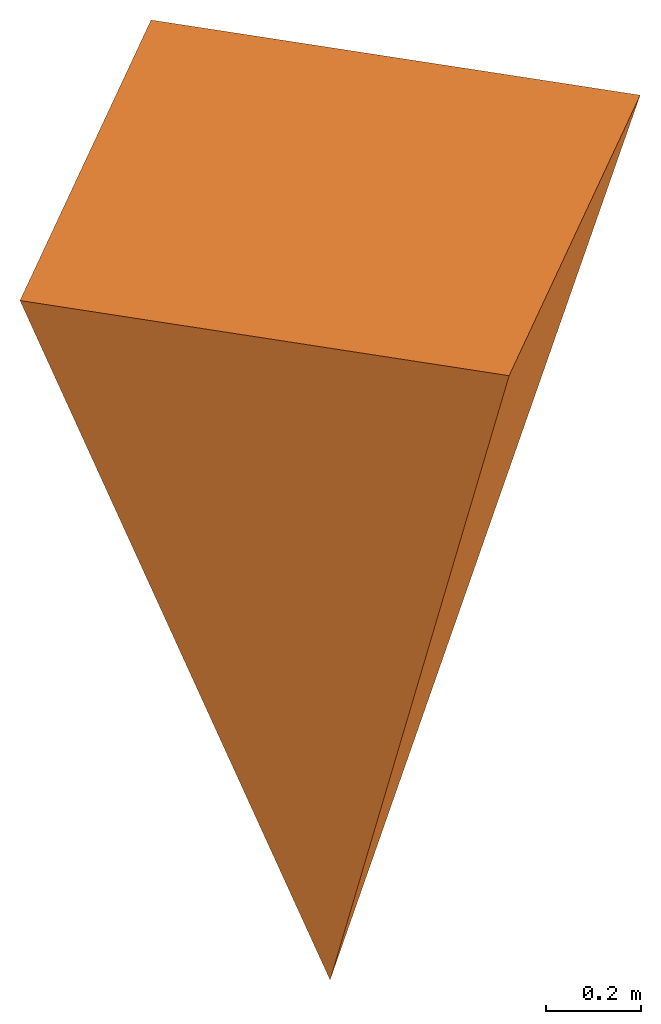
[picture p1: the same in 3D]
Properties of the parts of a building model (IFC4), part 4 of 4

# IfcWall (252)
Name | In | Material = AllplanAttributes, Material | Allright_Bauteil_ID | Codetext = Reference | Abrechnungsart | Gewerk | Bezeichnung | Typ = SurfaceSpreadOfFlame | Sicherheitsklasse | Brandschutzklasse | OKFF | Sonnenschutztyp | g-Wert | P_ID | LoadBearing | IsExternal | ThermalTransmittance (W/K/m2) | Combustible = Compartmentation | AcousticRating
 | H1 Ebene 0 | WA-DL | 1555Wa 0811452344 | Codetext | m³ | Zimmer- und Holzbauarbeiten | Außenwand 7-Schalig | 0 | - | A | 3.75 | Movable | 0,51 | 1155HWa0000192367 | no | yes | 0.9 | no | 35
 | H1 Ebene 0 | WA-LB | 1555Wa 0811452345 | Codetext | m² | Trockenbauarbeiten | Außenwand 7-Schalig | 0 | - | A | 3.75 | Movable | 0,51 | 1155HWa0000192367 | no | yes | 0.9 | no | 35
 | H1 Ebene 0 | WA-KL | 1555Wa 0811452357 | Codetext | m² | Zimmer- und Holzbauarbeiten | Außenwand 7-Schalig | 0 | - | A | 3.75 | Movable | 0,51 | 1155HWa0000192367 | no | yes | 0.9 | no | 35
 | H1 Ebene 0 | WA-TL | 1555Wa 0811452356 | Codetext | m² | Zimmer- und Holzbauarbeiten | Außenwand 7-Schalig | 0 | - | A | 3.75 | Movable | 0,51 | 1155HWa0000192367 | no | yes | 0.9 | no | 35
 | H1 Ebene 0 | WA-HS | 1555Wa 0811452358 | Codetext | m² | Zimmer- und Holzbauarbeiten | Außenwand 7-Schalig | 0 | - | A | 3.75 | Movable | 0,51 | 1155HWa0000192367 | no | yes | 0.9 | no | 35
 | H1 Ebene 0 | WA-LB | 1556Wa 0000003012 | Codetext | m² | Trockenbauarbeiten | Außenwand 2-Schalig | 0 |  | A |  |  |  | 1556HWa0000000763 |  | yes | 0 | no | 0
 | H1 Ebene 0 | WA-STB | 1556Wa 0000003013 | Codetext | m² | Betonarbeiten | Außenwand 2-Schalig | 0 |  | A |  |  |  | 1556HWa0000000763 |  | yes | 0 | no | 0
 | H1 Ebene 0 | WA-DE | 1556Wa 0000003014 | Codetext | m³ | Wärmedämm-Verbundsysteme | Außenwand 2-Schalig | 0 |  | A |  |  |  | 1556HWa0000000763 |  | yes | 0 | no | 0
 | H1 Ebene 0 | WA-LB | 1556Wa 0000003015 | Codetext | m² | Trockenbauarbeiten | Außenwand 2-Schalig | 0 |  | A |  |  |  | 1556HWa0000000763 |  | yes | 0 | no | 0
 | H1 Ebene 0 | WA-LB | 1556Wa 0000003222 | Codetext | m² | Trockenbauarbeiten | Außenwand 2-Schalig | 0 |  | A |  |  |  | 1556HWa0000000763 |  | yes | 0 | no | 0
 | H1 Ebene 0 | WA-STB | 1556Wa 0000003223 | Codetext | m² | Betonarbeiten | Außenwand 2-Schalig | 0 |  | A |  |  |  | 1556HWa0000000763 |  | yes | 0 | no | 0
 | H1 Ebene 0 | WA-DE | 1556Wa 0000003224 | Codetext | m³ | Wärmedämm-Verbundsysteme | Außenwand 2-Schalig | 0 |  | A |  |  |  | 1556HWa0000000763 |  | yes | 0 | no | 0
 | H1 Ebene 0 | WA-LB | 1556Wa 0000003225 | Codetext | m² | Trockenbauarbeiten | Außenwand 2-Schalig | 0 |  | A |  |  |  | 1556HWa0000000763 |  | yes | 0 | no | 0
 | H1 Ebene 0 | WA-LB | 1556Wa 0000003300 | Codetext | m² | Trockenbauarbeiten | Außenwand 2-Schalig | 0 |  | A |  |  |  | 1556HWa0000000763 |  | yes | 0 | no | 0
 | H1 Ebene 0 | WA-STB | 1556Wa 0000003301 | Codetext | m² | Betonarbeiten | Außenwand 2-Schalig | 0 |  | A |  |  |  | 1556HWa0000000763 |  | yes | 0 | no | 0
 | H1 Ebene 0 | WA-DE | 1556Wa 0000003302 | Codetext | m³ | Wärmedämm-Verbundsysteme | Außenwand 2-Schalig | 0 |  | A |  |  |  | 1556HWa0000000763 |  | yes | 0 | no | 0
 | H1 Ebene 0 | WA-LB | 1556Wa 0000003303 | Codetext | m² | Trockenbauarbeiten | Außenwand 2-Schalig | 0 |  | A |  |  |  | 1556HWa0000000763 |  | yes | 0 | no | 0
 | H1 Ebene 0 | WA-LB | 1556Wa 0000003339 | Codetext | m² | Trockenbauarbeiten | Außenwand 2-Schalig | 0 |  | A |  |  |  | 1556HWa0000000763 |  | yes | 0 | no | 0
 | H1 Ebene 0 | WA-STB | 1556Wa 0000003340 | Codetext | m² | Betonarbeiten | Außenwand 2-Schalig | 0 |  | A |  |  |  | 1556HWa0000000763 |  | yes | 0 | no | 0
 | H1 Ebene 0 | WA-DE | 1556Wa 0000003341 | Codetext | m³ | Wärmedämm-Verbundsysteme | Außenwand 2-Schalig | 0 |  | A |  |  |  | 1556HWa0000000763 |  | yes | 0 | no | 0
 | H1 Ebene 0 | WA-LB | 1556Wa 0000003342 | Codetext | m² | Trockenbauarbeiten | Außenwand 2-Schalig | 0 |  | A |  |  |  | 1556HWa0000000763 |  | yes | 0 | no | 0
 | H1 Ebene 0 | WA-LB | 1556Wa 0000003138 | Codetext | m² | Trockenbauarbeiten | Außenwand 2-Schalig | 0 |  | A |  |  |  | 1556HWa0000000763 |  | yes | 0 | no | 0
 | H1 Ebene 0 | WA-STB | 1556Wa 0000003139 | Codetext | m² | Betonarbeiten | Außenwand 2-Schalig | 0 |  | A |  |  |  | 1556HWa0000000763 |  | yes | 0 | no | 0
 | H1 Ebene 0 | WA-DE | 1556Wa 0000003140 | Codetext | m³ | Wärmedämm-Verbundsysteme | Außenwand 2-Schalig | 0 |  | A |  |  |  | 1556HWa0000000763 |  | yes | 0 | no | 0
 | H1 Ebene 0 | WA-LB | 1556Wa 0000003141 | Codetext | m² | Trockenbauarbeiten | Außenwand 2-Schalig | 0 |  | A |  |  |  | 1556HWa0000000763 |  | yes | 0 | no | 0
 | H1 Ebene 0 | WA-LB | 1556Wa 0000003124 | Codetext | m² | Trockenbauarbeiten | Außenwand 2-Schalig | 0 |  | A |  |  |  | 1556HWa0000000763 |  | yes | 0 | no | 0
 | H1 Ebene 0 | WA-STB | 1556Wa 0000003125 | Codetext | m² | Betonarbeiten | Außenwand 2-Schalig | 0 |  | A |  |  |  | 1556HWa0000000763 |  | yes | 0 | no | 0
 | H1 Ebene 0 | WA-DE | 1556Wa 0000003126 | Codetext | m³ | Wärmedämm-Verbundsysteme | Außenwand 2-Schalig | 0 |  | A |  |  |  | 1556HWa0000000763 |  | yes | 0 | no | 0
 | H1 Ebene 0 | WA-LB | 1556Wa 0000003127 | Codetext | m² | Trockenbauarbeiten | Außenwand 2-Schalig | 0 |  | A |  |  |  | 1556HWa0000000763 |  | yes | 0 | no | 0
 | H1 Ebene 0 | WA-LB | 1556Wa 0000003079 | Codetext | m² | Trockenbauarbeiten | Außenwand 2-Schalig | 0 |  | A |  |  |  | 1556HWa0000000763 |  | yes | 0 | no | 0
 | H1 Ebene 0 | WA-STB | 1556Wa 0000003080 | Codetext | m² | Betonarbeiten | Außenwand 2-Schalig | 0 |  | A |  |  |  | 1556HWa0000000763 |  | yes | 0 | no | 0
 | H1 Ebene 0 | WA-DE | 1556Wa 0000003081 | Codetext | m³ | Wärmedämm-Verbundsysteme | Außenwand 2-Schalig | 0 |  | A |  |  |  | 1556HWa0000000763 |  | yes | 0 | no | 0
 | H1 Ebene 0 | WA-LB | 1556Wa 0000003082 | Codetext | m² | Trockenbauarbeiten | Außenwand 2-Schalig | 0 |  | A |  |  |  | 1556HWa0000000763 |  | yes | 0 | no | 0
 | H1 Ebene 0 | WA-LB | 1556Wa 0000003191 | Codetext | m² | Trockenbauarbeiten | Außenwand 2-Schalig | 0 |  | A |  |  |  | 1556HWa0000000763 |  | yes | 0 | no | 0
 | H1 Ebene 0 | WA-STB | 1556Wa 0000003192 | Codetext | m² | Betonarbeiten | Außenwand 2-Schalig | 0 |  | A |  |  |  | 1556HWa0000000763 |  | yes | 0 | no | 0
 | H1 Ebene 0 | WA-DE | 1556Wa 0000003193 | Codetext | m³ | Wärmedämm-Verbundsysteme | Außenwand 2-Schalig | 0 |  | A |  |  |  | 1556HWa0000000763 |  | yes | 0 | no | 0
 | H1 Ebene 0 | WA-LB | 1556Wa 0000003194 | Codetext | m² | Trockenbauarbeiten | Außenwand 2-Schalig | 0 |  | A |  |  |  | 1556HWa0000000763 |  | yes | 0 | no | 0
 | H1 Ebene 0 | WA-LB | 1556Wa 0000003261 | Codetext | m² | Trockenbauarbeiten | Außenwand 2-Schalig | 0 |  | A |  |  |  | 1556HWa0000000763 |  | yes | 0 | no | 0
 | H1 Ebene 0 | WA-STB | 1556Wa 0000003262 | Codetext | m² | Betonarbeiten | Außenwand 2-Schalig | 0 |  | A |  |  |  | 1556HWa0000000763 |  | yes | 0 | no | 0
 | H1 Ebene 0 | WA-DE | 1556Wa 0000003263 | Codetext | m³ | Wärmedämm-Verbundsysteme | Außenwand 2-Schalig | 0 |  | A |  |  |  | 1556HWa0000000763 |  | yes | 0 | no | 0
 | H1 Ebene 0 | WA-LB | 1556Wa 0000003264 | Codetext | m² | Trockenbauarbeiten | Außenwand 2-Schalig | 0 |  | A |  |  |  | 1556HWa0000000763 |  | yes | 0 | no | 0
 | H1 Ebene 0 | WI-HW 60 | 1563Wa 0813612487 |  | m² | Zimmer- und Holzbauarbeiten | Innenwand 1-Schalig |  | - |  | 0 |  |  | 1113HWa0812443023 | no |  |  |  | 47
 | H1 Ebene 0 | WI-IW | 1563Wa 0813612481 |  | m² | Trockenbauarbeiten | Installationswand |  | - |  | 0 |  |  | 1113HWa0814145504 | no |  |  |  | 0 | AllplanAttributes - W_Deckenanschluss: Gleitender Deckenanschluss Fall 01; ash_W_Trockenbau_Qualitäten: 2
 | H1 Ebene 0 | Installationsraum | 1563Wa 0813612451 |  | m² | Trockenbauarbeiten | Installationswand |  | - |  | 0 |  |  | 1113HWa0814145504 |  |  |  |  | 0
 | H1 Ebene 0 | WI-IW | 1563Wa 0813612449 |  | m² | Trockenbauarbeiten | Installationswand |  | - |  | 0 |  |  | 1113HWa0814145504 |  |  |  |  | 0 | AllplanAttributes - W_Deckenanschluss: Gleitender Deckenanschluss Fall 01; ash_W_Trockenbau_Qualitäten: 2
 | H1 Ebene 0 | Installationsraum | 1563Wa 0813612444 |  | m² | Trockenbauarbeiten | Installationswand |  | - |  | 0 |  |  | 1113HWa0814145504 |  |  |  |  | 0
 | H1 Ebene 0 | WI-IW | 1563Wa 0813612362 |  | m² | Trockenbauarbeiten | Installationswand |  | - |  | 0 |  |  | 1113HWa0814145504 |  |  |  |  | 0 | AllplanAttributes - W_Deckenanschluss: Gleitender Deckenanschluss Fall 01; ash_W_Trockenbau_Qualitäten: 2
 | H1 Ebene 0 | WI-IW | 1563Wa 0813612494 |  | m² | Trockenbauarbeiten | Installationswand |  | - |  | 0 |  |  | 1113HWa0814145504 | no |  |  |  | 0 | AllplanAttributes - W_Deckenanschluss: Gleitender Deckenanschluss Fall 01; ash_W_Trockenbau_Qualitäten: 2
 | H1 Ebene 0 | WI-IW | 1563Wa 0813612458 |  | m² | Trockenbauarbeiten | Installationswand |  | - |  | 0 |  |  | 1113HWa0814145504 | no |  |  |  | 0 | AllplanAttributes - W_Deckenanschluss: Gleitender Deckenanschluss Fall 01; ash_W_Trockenbau_Qualitäten: 2
 | H1 Ebene 0 | Installationsraum | 1563Wa 0813612455 |  | m² | Trockenbauarbeiten | Installationswand |  | - |  | 0 |  |  | 1113HWa0814145504 | no |  |  |  | 0
 | H1 Ebene 0 | WI-IW | 1563Wa 0813612453 |  | m² | Trockenbauarbeiten | Installationswand |  | - |  | 0 |  |  | 1113HWa0814145504 | no |  |  |  | 0 | AllplanAttributes - W_Deckenanschluss: Gleitender Deckenanschluss Fall 01; ash_W_Trockenbau_Qualitäten: 2
 | H1 Ebene 0 | WI-LB | 1563Wa 0813612369 |  | m² | Trockenbauarbeiten | Innenwand 1-Schalig |  | - |  | 0 |  |  | 1113HWa0812440867 | no |  |  |  | 0 | AllplanAttributes - W_Deckenanschluss: Gleitender Deckenanschluss Fall 01; ash_W_Trockenbau_Qualitäten: 1b
 | H1 Ebene 0 | WI-IW | 1563Wa 0813612364 |  | m² | Trockenbauarbeiten | Installationswand |  | - |  | 0 |  |  | 1113HWa0814145504 |  |  |  |  | 0 | AllplanAttributes - W_Deckenanschluss: Gleitender Deckenanschluss Fall 01; ash_W_Trockenbau_Qualitäten: 2
 | H1 Ebene 0 | Installationsraum | 1563Wa 0813612446 |  | m² | Trockenbauarbeiten | Installationswand |  | - |  | 0 |  |  | 1113HWa0814145504 |  |  |  |  | 0
 | H1 Ebene 0 | WI-IW | 1563Wa 0813612367 |  | m² | Trockenbauarbeiten | Installationswand |  | - |  | 0 |  |  | 1113HWa0814145504 |  |  |  |  | 0 | AllplanAttributes - W_Deckenanschluss: Gleitender Deckenanschluss Fall 01; ash_W_Trockenbau_Qualitäten: 2
 | H1 Ebene 0 | WI-IW | 1563Wa 0813612475 |  | m² | Trockenbauarbeiten | Installationswand |  | - |  | 0 |  |  | 1113HWa0814145504 | no |  |  |  | 0 | AllplanAttributes - W_Deckenanschluss: Gleitender Deckenanschluss Fall 01; ash_W_Trockenbau_Qualitäten: 2
 | H1 Ebene 0 | WI-IW | 1563Wa 0813612289 |  | m² | Trockenbauarbeiten | Installationswand |  | - |  | 0 |  |  | 1113HWa0814145504 |  |  |  |  | 0 | AllplanAttributes - W_Deckenanschluss: Gleitender Deckenanschluss Fall 01; ash_W_Trockenbau_Qualitäten: 2
 | H1 Ebene 0 | WI-IW | 1563Wa 0813612286 |  | m² | Trockenbauarbeiten | Installationswand |  | - |  | 0 |  |  | 1113HWa0814145504 | no |  |  |  | 0 | AllplanAttributes - W_Deckenanschluss: Gleitender Deckenanschluss Fall 01; ash_W_Trockenbau_Qualitäten: 2
 | H1 Ebene 0 | WI-IW | 1563Wa 0813612440 |  | m² | Trockenbauarbeiten | Installationswand |  | - |  | 0 |  |  | 1113HWa0814145504 | no |  |  |  | 0 | AllplanAttributes - W_Deckenanschluss: Gleitender Deckenanschluss Fall 01; ash_W_Trockenbau_Qualitäten: 2
 | H1 Ebene 0 | WI-IW | 1563Wa 0813612388 |  | m² | Trockenbauarbeiten | Installationswand |  | - |  | 0 |  |  | 1113HWa0814145504 | no |  |  |  | 0 | AllplanAttributes - W_Deckenanschluss: Gleitender Deckenanschluss Fall 01; ash_W_Trockenbau_Qualitäten: 2
 | H1 Ebene 0 | Installationsraum | 1563Wa 0813612291 |  | m² | Trockenbauarbeiten | Installationswand |  | - |  | 0 |  |  | 1113HWa0814145504 | no |  |  |  | 0
 | H1 Ebene 0 | WI-IW | 1563Wa 0813612391 |  | m² | Trockenbauarbeiten | Installationswand |  | - |  | 0 |  |  | 1113HWa0814145504 | no |  |  |  | 0 | AllplanAttributes - W_Deckenanschluss: Gleitender Deckenanschluss Fall 01; ash_W_Trockenbau_Qualitäten: 2
 | H1 Ebene 0 | Installationsraum | 1563Wa 0813612318 |  | m² | Trockenbauarbeiten | Installationswand |  | - |  | 0 |  |  | 1113HWa0814145504 | no |  |  |  | 0
 | H1 Ebene 0 | WI-IW | 1563Wa 0813612305 |  | m² | Trockenbauarbeiten | Installationswand |  | - |  | 0 |  |  | 1113HWa0814145504 |  |  |  |  | 0 | AllplanAttributes - W_Deckenanschluss: Gleitender Deckenanschluss Fall 01; ash_W_Trockenbau_Qualitäten: 2
 | H1 Ebene 0 | WI-IW | 1563Wa 0813612425 |  | m² | Trockenbauarbeiten | Installationswand |  | - |  | 0 |  |  | 1113HWa0814145504 |  |  |  |  | 0 | AllplanAttributes - W_Deckenanschluss: Gleitender Deckenanschluss Fall 01; ash_W_Trockenbau_Qualitäten: 2
 | H1 Ebene 0 | WI-IW | 1563Wa 0813612413 |  | m² | Trockenbauarbeiten | Installationswand |  | - |  | 0 |  |  | 1113HWa0814145504 |  |  |  |  | 0 | AllplanAttributes - W_Deckenanschluss: Gleitender Deckenanschluss Fall 01; ash_W_Trockenbau_Qualitäten: 2
 | H1 Ebene 0 | WI-IW | 1563Wa 0813612302 |  | m² | Trockenbauarbeiten | Installationswand |  | - |  | 0 |  |  | 1113HWa0814145504 | no |  |  |  | 0 | AllplanAttributes - W_Deckenanschluss: Gleitender Deckenanschluss Fall 01; ash_W_Trockenbau_Qualitäten: 2
 | H1 Ebene 0 | Installationsraum | 1563Wa 0813612313 |  | m² | Trockenbauarbeiten | Installationswand |  | - |  | 0 |  |  | 1113HWa0814145504 | no |  |  |  | 0
 | H1 Ebene 0 | WI-IW | 1563Wa 0813612434 |  | m² | Trockenbauarbeiten | Installationswand |  | - |  | 0 |  |  | 1113HWa0814145504 |  |  |  |  | 0 | AllplanAttributes - W_Deckenanschluss: Gleitender Deckenanschluss Fall 01; ash_W_Trockenbau_Qualitäten: 2
 | H1 Ebene 0 | WI-IW | 1563Wa 0813612321 |  | m² | Trockenbauarbeiten | Installationswand |  | - |  | 0 |  |  | 1113HWa0814145504 | no |  |  |  | 0 | AllplanAttributes - W_Deckenanschluss: Gleitender Deckenanschluss Fall 01; ash_W_Trockenbau_Qualitäten: 2
 | H1 Ebene 0 | WI-IW | 1563Wa 0813612324 |  | m² | Trockenbauarbeiten | Installationswand |  | - |  | 0 |  |  | 1113HWa0814145504 | no |  |  |  | 0 | AllplanAttributes - W_Deckenanschluss: Gleitender Deckenanschluss Fall 01; ash_W_Trockenbau_Qualitäten: 2
 | H1 Ebene 0 | WI-IW | 1563Wa 0813612431 |  | m² | Trockenbauarbeiten | Installationswand |  | - |  | 0 |  |  | 1113HWa0814145504 |  |  |  |  | 0 | AllplanAttributes - W_Deckenanschluss: Gleitender Deckenanschluss Fall 01; ash_W_Trockenbau_Qualitäten: 2
 | H1 Ebene 0 | WI-IW | 1563Wa 0813612428 |  | m² | Trockenbauarbeiten | Installationswand |  | - |  | 0 |  |  | 1113HWa0814145504 |  |  |  |  | 0 | AllplanAttributes - W_Deckenanschluss: Gleitender Deckenanschluss Fall 01; ash_W_Trockenbau_Qualitäten: 2
 | H1 Ebene 0 | WI-IW | 1563Wa 0813612422 |  | m² | Trockenbauarbeiten | Installationswand |  | - |  | 0 |  |  | 1113HWa0814145504 |  |  |  |  | 0 | AllplanAttributes - W_Deckenanschluss: Gleitender Deckenanschluss Fall 01; ash_W_Trockenbau_Qualitäten: 2
 | H1 Ebene 0 | WI-IW | 1563Wa 0813612416 |  | m² | Trockenbauarbeiten | Installationswand |  | - |  | 0 |  |  | 1113HWa0814145504 |  |  |  |  | 0 | AllplanAttributes - W_Deckenanschluss: Gleitender Deckenanschluss Fall 01; ash_W_Trockenbau_Qualitäten: 2
 | H1 Ebene 0 | WI-IW | 1563Wa 0813612409 |  | m² | Trockenbauarbeiten | Installationswand |  | - |  | 0 |  |  | 1113HWa0814145504 |  |  |  |  | 0 | AllplanAttributes - W_Deckenanschluss: Gleitender Deckenanschluss Fall 01; ash_W_Trockenbau_Qualitäten: 2
 | H1 Ebene 0 | WI-IW | 1563Wa 0813612400 |  | m² | Trockenbauarbeiten | Installationswand |  | - |  | 0 |  |  | 1113HWa0814145504 |  |  |  |  | 0 | AllplanAttributes - W_Deckenanschluss: Gleitender Deckenanschluss Fall 01; ash_W_Trockenbau_Qualitäten: 2
 | H1 Ebene 0 | WI-IW | 1563Wa 0813612359 |  | m² | Trockenbauarbeiten | Installationswand |  | - |  | 0 |  |  | 1113HWa0814145504 |  |  |  |  | 0 | AllplanAttributes - W_Deckenanschluss: Gleitender Deckenanschluss Fall 01; ash_W_Trockenbau_Qualitäten: 2
 | H1 Ebene 0 | WI-IW | 1563Wa 0813612308 |  | m² | Trockenbauarbeiten | Installationswand |  | - |  | 0 |  |  | 1113HWa0814145504 |  |  |  |  | 0 | AllplanAttributes - W_Deckenanschluss: Gleitender Deckenanschluss Fall 01; ash_W_Trockenbau_Qualitäten: 2
 | H1 Ebene 0 | WI-IW | 1563Wa 0813612311 |  | m² | Trockenbauarbeiten | Installationswand |  | - |  | 0 |  |  | 1113HWa0814145504 |  |  |  |  | 0 | AllplanAttributes - W_Deckenanschluss: Gleitender Deckenanschluss Fall 01; ash_W_Trockenbau_Qualitäten: 2
 | H1 Ebene 0 | WI-IW | 1563Wa 0813612419 |  | m² | Trockenbauarbeiten | Installationswand |  | - |  | 0 |  |  | 1113HWa0814145504 |  |  |  |  | 0 | AllplanAttributes - W_Deckenanschluss: Gleitender Deckenanschluss Fall 01; ash_W_Trockenbau_Qualitäten: 2
 | H1 Ebene 0 | WI-IW | 1563Wa 0813612405 |  | m² | Trockenbauarbeiten | Installationswand |  | - |  | 0 |  |  | 1113HWa0814145504 | no |  |  |  | 0 | AllplanAttributes - W_Deckenanschluss: Gleitender Deckenanschluss Fall 01; ash_W_Trockenbau_Qualitäten: 2
 | H1 Ebene 0 | WI-IW | 1563Wa 0813612316 |  | m² | Trockenbauarbeiten | Installationswand |  | - |  | 0 |  |  | 1113HWa0814145504 | no |  |  |  | 0 | AllplanAttributes - W_Deckenanschluss: Gleitender Deckenanschluss Fall 01; ash_W_Trockenbau_Qualitäten: 2
 | H1 Ebene 0 | WI-IW | 1563Wa 0813612355 |  | m² | Trockenbauarbeiten | Installationswand |  | - |  | 0 |  |  | 1113HWa0814145504 |  |  |  |  | 0 | AllplanAttributes - W_Deckenanschluss: Gleitender Deckenanschluss Fall 01; ash_W_Trockenbau_Qualitäten: 2
 | H1 Ebene 0 | WI-LB | 1563Wa 0813612328 | Codetext | m² | Trockenbauarbeiten | Innenwand 1-Schalig | 0 |  | A |  |  |  |  | no | no | 0 | no | 0
 | H1 Ebene 0 | WI-LB | 1563Wa 0813612338 | Codetext | m² | Trockenbauarbeiten | Innenwand 1-Schalig | 0 |  | A |  |  |  |  | no | no | 0 | no | 0
 | H1 Ebene 0 | WI-IW | 1563Wa 0813612343 |  | m² | Trockenbauarbeiten | Installationswand |  | - |  | 0 |  |  | 1113HWa0814145504 |  |  |  |  | 0 | AllplanAttributes - W_Deckenanschluss: Gleitender Deckenanschluss Fall 01; ash_W_Trockenbau_Qualitäten: 2
 | H1 Ebene 0 | Installationsraum | 1563Wa 0813612350 |  | m² | Trockenbauarbeiten | Installationswand |  | - |  | 0 |  |  | 1113HWa0814145504 |  |  |  |  | 0
 | H1 Ebene 0 | WI-IW | 1563Wa 0813612348 |  | m² | Trockenbauarbeiten | Installationswand |  | - |  | 0 |  |  | 1113HWa0814145504 |  |  |  |  | 0 | AllplanAttributes - W_Deckenanschluss: Gleitender Deckenanschluss Fall 01; ash_W_Trockenbau_Qualitäten: 2
 | H1 Ebene 0 | WI-IW | 1563Wa 0813612331 |  | m² | Trockenbauarbeiten | Installationswand |  | - |  | 0 |  |  | 1113HWa0814145504 | no |  |  |  | 0 | AllplanAttributes - W_Deckenanschluss: Gleitender Deckenanschluss Fall 01; ash_W_Trockenbau_Qualitäten: 2
 | H1 Ebene 0 | Installationsraum | 1563Wa 0813612345 |  | m² | Trockenbauarbeiten | Installationswand |  | - |  | 0 |  |  | 1113HWa0814145504 | no |  |  |  | 0
 | H1 Ebene 0 | WI-LB | 1563Wa 0813612341 | Codetext | m² | Trockenbauarbeiten | Innenwand 1-Schalig | 0 |  | A |  |  |  |  | no | no | 0 | no | 0
 | H1 Ebene 0 | WI-LB | 1563Wa 0813612380 |  | m² | Trockenbauarbeiten | Innenwand 1-Schalig |  | - |  | 0 |  |  | 1113HWa0812440867 | no |  |  |  | 0 | AllplanAttributes - W_Deckenanschluss: Gleitender Deckenanschluss Fall 01; ash_W_Trockenbau_Qualitäten: 1b
 | H1 Ebene 0 | WI-LB | 1563Wa 0813612382 |  | m² | Trockenbauarbeiten | Innenwand 1-Schalig |  | - |  | 0 |  |  | 1113HWa0812440867 | no |  |  |  | 0 | AllplanAttributes - W_Deckenanschluss: Gleitender Deckenanschluss Fall 01; ash_W_Trockenbau_Qualitäten: 1b
 | H1 Ebene 0 | WI-LB | 1563Wa 0813612376 |  | m² | Trockenbauarbeiten | Innenwand 1-Schalig |  | - |  | 0 |  |  | 1113HWa0812440867 | no |  |  |  | 0 | AllplanAttributes - W_Deckenanschluss: Gleitender Deckenanschluss Fall 01; ash_W_Trockenbau_Qualitäten: 1b
 | H1 Ebene 0 | WI-LB | 1563Wa 0813612374 |  | m² | Trockenbauarbeiten | Innenwand 1-Schalig |  | - |  | 0 |  |  | 1113HWa0812440867 | no |  |  |  | 0 | AllplanAttributes - W_Deckenanschluss: Gleitender Deckenanschluss Fall 01; ash_W_Trockenbau_Qualitäten: 1b
 | H1 Ebene 0 | WI-LB | 1563Wa 0813612371 |  | m² | Trockenbauarbeiten | Innenwand 1-Schalig |  | - |  | 0 |  |  | 1113HWa0812440867 | no |  |  |  | 0 | AllplanAttributes - W_Deckenanschluss: Gleitender Deckenanschluss Fall 01; ash_W_Trockenbau_Qualitäten: 1b
 | H1 Ebene 0 | WI-IW | 1563Wa 0813612385 |  | m² | Trockenbauarbeiten | Installationswand |  | - |  | 0 |  |  | 1113HWa0814145504 |  |  |  |  | 0 | AllplanAttributes - W_Deckenanschluss: Gleitender Deckenanschluss Fall 01; ash_W_Trockenbau_Qualitäten: 2
 | H1 Ebene 0 | Installationsraum | 1563Wa 0813612352 |  | m² | Trockenbauarbeiten | Installationswand |  | - |  | 0 |  |  | 1113HWa0814145504 |  |  |  |  | 0
 | H1 Ebene 0 | WI-IW | 1563Wa 0813612859 |  | m² | Trockenbauarbeiten | Installationswand |  | - |  | 0 |  |  | 1113HWa0814145504 |  |  |  |  | 0 | AllplanAttributes - W_Deckenanschluss: Gleitender Deckenanschluss Fall 01; ash_W_Trockenbau_Qualitäten: 2
 | H1 Ebene 0 | Installationsraum | 1563Wa 0813612860 |  | m² | Trockenbauarbeiten | Installationswand |  | - |  | 0 |  |  | 1113HWa0814145504 |  |  |  |  | 0
 | H1 Ebene 0 | WI-IW | 1563Wa 0813612297 |  | m² | Trockenbauarbeiten | Installationswand |  | - |  | 0 |  |  | 1113HWa0814145504 |  |  |  |  | 0 | AllplanAttributes - W_Deckenanschluss: Gleitender Deckenanschluss Fall 01; ash_W_Trockenbau_Qualitäten: 2
 | H1 Ebene 0 | WI-IW | 1563Wa 0813612893 |  | m² | Trockenbauarbeiten | Installationswand |  | - |  | 0 |  |  | 1113HWa0814145504 |  |  |  |  | 0 | AllplanAttributes - W_Deckenanschluss: Gleitender Deckenanschluss Fall 01; ash_W_Trockenbau_Qualitäten: 2
 | H1 Ebene 0 | WI-IW | 1563Wa 0813612396 |  | m² | Trockenbauarbeiten | Installationswand |  | - |  | 0 |  |  | 1113HWa0814145504 | no |  |  |  | 0 | AllplanAttributes - W_Deckenanschluss: Gleitender Deckenanschluss Fall 01; ash_W_Trockenbau_Qualitäten: 2
 | H1 Ebene 0 | WI-IW | 1563Wa 0813612906 |  | m² | Trockenbauarbeiten | Installationswand |  | - |  | 0 |  |  | 1113HWa0814145504 | no |  |  |  | 0 | AllplanAttributes - W_Deckenanschluss: Gleitender Deckenanschluss Fall 01; ash_W_Trockenbau_Qualitäten: 2
 | H1 Ebene 0 | WI-IW | 1563Wa 0813613081 |  | m² | Trockenbauarbeiten | Installationswand |  | - |  | 0 |  |  | 1113HWa0814145504 |  |  |  |  | 0 | AllplanAttributes - W_Deckenanschluss: Gleitender Deckenanschluss Fall 01; ash_W_Trockenbau_Qualitäten: 2

# IfcWindow (15)
PredefinedType: WINDOW; PartitioningType: USERDEFINED
AllplanQuantities - OffsetOpeningTop: 0; OffsetOpeningLeft: 0; OffsetOpeningRight: 0
Name | In | OverallHeight (m) | OverallWidth (m) | OffsetOpeningBottom | AllplanAttributes (Fenster-SmartPart), V6 (m) = AllplanAttributes (Fenster-SmartPart), V7 (m) = AllplanAttributes (Fenster-SmartPart), V8 (m) = AllplanAttributes (Fenster-SmartPart), V9 = HeightWindowSillOutside = HeightWindowSillInside | AllplanAttributes (Fenster-SmartPart), Programmversion | AllplanAttributes (Fenster-SmartPart), Bezeichnung | AllplanAttributes (Fenster-SmartPart), Plugin_Bezeichnung | AllplanAttributes (Fenster-SmartPart), Plugin_Objektname | Glasanteil_berücksichtigen | AllplanAttributes (Fenster-SmartPart), Version | AllplanAttributes (Fenster-SmartPart), Allright_Bauteil_ID | AllplanAttributes (Fenster-SmartPart), Abrechnungsart | AllplanAttributes (Fenster-SmartPart), Objektname | GlassSurface | DeductionOpeningBottom = DeductionOpeningLeft = DeductionOpeningRight = DeductionOpeningTop
Klappladen | H1 Ebene +1 | 1.91148 | 4.702 | 0 | AllplanAttributes (Klappladen) - V6: 0 m; V7: 0 m; V8: 0 m; V9: 0; Programmversion: 2.2; Bezeichnung: Klappladen; Plugin_Bezeichnung: MainObject; Plugin_Objektname: SmartPartCompressed; Version: 3.0; Allright_Bauteil_ID: 1605Mak0000069610; Abrechnungsart: St; Objektname: Sonnenschutz; Pset_WindowCommon - IsExternal: yes; FireRating: -
Klappladen | H1 Ebene +1 | 2.53022 | 7.59727 | 0 | AllplanAttributes (Klappladen) - V6: 0 m; V7: 0 m; V8: 0 m; V9: 0; Programmversion: 2.2; Bezeichnung: Klappladen; Plugin_Bezeichnung: MainObject; Plugin_Objektname: SmartPartCompressed; Version: 3.0; Allright_Bauteil_ID: 1605Mak0000069924; Abrechnungsart: St; Objektname: Sonnenschutz; Pset_WindowCommon - IsExternal: yes; FireRating: -
Klappladen | H1 Ebene +1 | 1.70165 | 1.85 | 0 | AllplanAttributes (Klappladen) - V6: 0 m; V7: 0 m; V8: 0 m; V9: 0; Programmversion: 2.2; Bezeichnung: Klappladen; Plugin_Bezeichnung: MainObject; Plugin_Objektname: SmartPartCompressed; Version: 3.0; Allright_Bauteil_ID: 1605Mak0000070821; Abrechnungsart: St; Objektname: Sonnenschutz; Pset_WindowCommon - IsExternal: yes; FireRating: -
Klappladen | H1 Ebene +1 | 3.41562 | 1.85205 | 0 | AllplanAttributes (Klappladen) - V6: 0 m; V7: 0 m; V8: 0 m; V9: 0; Programmversion: 2.2; Bezeichnung: Klappladen; Plugin_Bezeichnung: MainObject; Plugin_Objektname: SmartPartCompressed; Version: 3.0; Allright_Bauteil_ID: 1605Mak0000071477; Abrechnungsart: St; Objektname: Sonnenschutz; Pset_WindowCommon - IsExternal: yes; FireRating: -
Klappladen | H1 Ebene +1 | 2.70215 | 1.85 | 0 | AllplanAttributes (Klappladen) - V6: 0 m; V7: 0 m; V8: 0 m; V9: 0; Programmversion: 2.2; Bezeichnung: Klappladen; Plugin_Bezeichnung: MainObject; Plugin_Objektname: SmartPartCompressed; Version: 3.0; Allright_Bauteil_ID: 1605Mak0000070616; Abrechnungsart: St; Objektname: Sonnenschutz; Pset_WindowCommon - IsExternal: yes; FireRating: -
2 x Klappladen | H1 Ebene +1 | 3.41562 | 3.1 | 0 | AllplanAttributes (Klappladen) - V6: 0 m; V7: 0 m; V8: 0 m; V9: 0; Programmversion: 2.2; Bezeichnung: Klappladen; Plugin_Bezeichnung: MainObject; Plugin_Objektname: SmartPartCompressed; Version: 3.0; Allright_Bauteil_ID: 1605Mak0000071493; Abrechnungsart: St; Objektname: Sonnenschutz; Pset_WindowCommon - IsExternal: yes; FireRating: -
Fenster-SmartPart | H1 Ebene 0 | 2.95 | 1.25 | 200 | 0 | 3.0 | Fenster-SmartPart | MainObject | SmartPartCompressed | 100 | 9.6 | 1555Mak0811452126 | St | Fenstermakro, -SmartPart | 2.8971 | 70
Fenster-SmartPart | H1 Ebene 0 | 2.95 | 1.25 | 200 | 0 | 3.0 | Fenster-SmartPart | MainObject | SmartPartCompressed | 100 | 9.6 | 1555Mak0811452123 | St | Fenstermakro, -SmartPart | 2.8971 | 70
Fenster-SmartPart | H1 Ebene 0 | 2.95 | 1.25 | 200 | 0 | 3.0 | Fenster-SmartPart | MainObject | SmartPartCompressed | 100 | 9.6 | 1555Mak0811452120 | St | Fenstermakro, -SmartPart | 2.8971 | 70
Fenster-SmartPart | H1 Ebene 0 | 2.95 | 1.25 | 200 | 0 | 3.0 | Fenster-SmartPart | MainObject | SmartPartCompressed | 100 | 9.6 | 1555Mak0811455903 | St | Fenstermakro, -SmartPart | 2.8971 | 70
Fenster-SmartPart | H1 Ebene 0 | 2.95 | 1.25 | 200 | 0 | 3.0 | Fenster-SmartPart | MainObject | SmartPartCompressed | 100 | 9.6 | 1555Mak0811455905 | St | Fenstermakro, -SmartPart | 2.8971 | 70
Fenster-SmartPart | H1 Ebene 0 | 3.85 | 1.85 | 200 | 0 | 3.0 | Fenster-SmartPart | MainObject | SmartPartCompressed | 100 | 9.6 | 1555Mak0811452228 | St | Fenstermakro, -SmartPart | 5.6277 | 80
Fenster-SmartPart | H1 Ebene 0 | 3.85 | 1.25 | 200 | 0 | 3.0 | Fenster-SmartPart | MainObject | SmartPartCompressed | 100 | 9.6 | 1555Mak0811452234 | St | Fenstermakro, -SmartPart | 3.6297 | 80
Fenster-SmartPart | H1 Ebene 0 | 3.85 | 1.25 | 200 | 0 | 3.0 | Fenster-SmartPart | MainObject | SmartPartCompressed | 100 | 9.6 | 1555Mak0811452232 | St | Fenstermakro, -SmartPart | 3.6297 | 80
